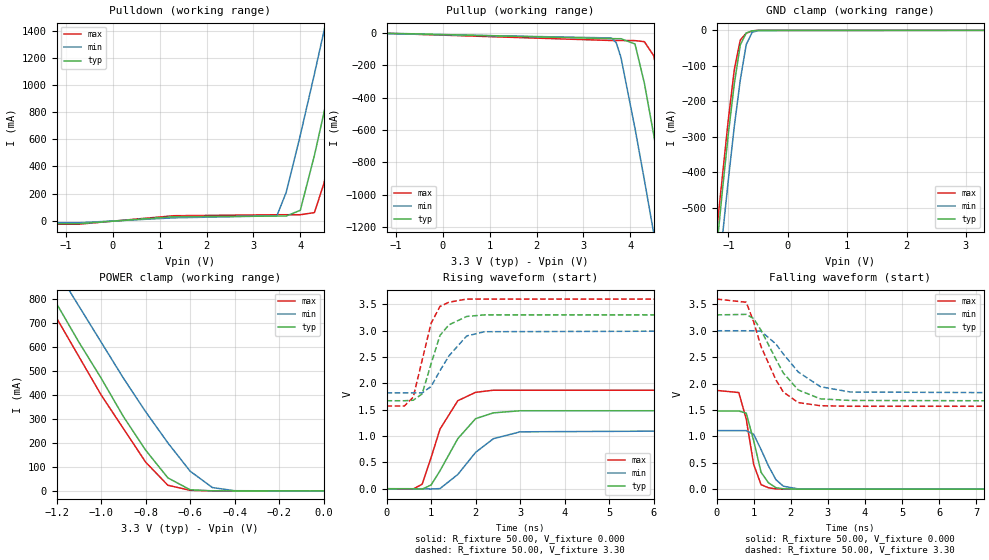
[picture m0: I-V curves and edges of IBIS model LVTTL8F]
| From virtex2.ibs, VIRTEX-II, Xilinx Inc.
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|   Model LVTTL8F
[Model]   LVTTL8F
Model_type   I/O
Polarity   Non-Inverting
Enable   Active-Low
Vinh = 2.0V
Vinl = 0.8V
Vmeas =   1.40V
Cref =  35.00pF
Rref =   1.00M
Vref =  0.000V
C_comp   7.00pF   6.00pF   8.00pF
[Temperature Range]   25.00   100.00   0.000
[Voltage Range]   3.30V   3.00V   3.60V
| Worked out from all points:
|   slope of the pulldown table from 0 to 0.495 V, typ, clamps not added: 32.6 ohm
|   slope of the pullup table from 0 to 0.495 V, typ, clamps not added: 42.6 ohm
|   GND clamp passes 1 mA (typ) near -0.57 V on its own axis
|   POWER clamp passes 1 mA (typ) near -0.52 V on its own axis
|   rising waveform, R_fixture 50.00, V_fixture 0.000: 20-80 % time 628ps typ, 738ps min, 546ps max; typ from 0 V to 1.48 V
|   rising waveform, R_fixture 50.00, V_fixture 3.30: 20-80 % time 395ps typ, 518ps min, 366ps max; typ from 1.67 V to 3.3 V
|   falling waveform, R_fixture 50.00, V_fixture 0.000: 20-80 % time 326ps typ, 463ps min, 316ps max; typ from 1.48 V to 0 V
|   falling waveform, R_fixture 50.00, V_fixture 3.30: 20-80 % time 792ps typ, 914ps min, 695ps max; typ from 3.3 V to 1.67 V
[Pulldown]
| voltage   I(typ)   I(min)   I(max)
-3.3V     -21.47mA   -14.42mA   -24.67mA
-700mV    -21.47mA   -14.42mA   -24.67mA
1.3V      29.85mA    21.41mA    36.81mA
3.5V      34.44mA    36.13mA    44.01mA
3.7V      34.53mA    210mA      44.1mA
4V        77.1mA     630mA      44.22mA
4.3V      480mA      1.08A      60mA
4.5V      790mA      1.39A      270mA
4.9V      1.44A      2.02A      900mA
5.1V      1.77A      2.33A      1.22A
5.3V      2.1A       2.65A      1.55A
6.6V      4.26A      4.71A      3.71A
[Pullup]
| voltage   I(typ)   I(min)   I(max)
-3.3V     15.18mA    8.8mA      18.53mA
3.6V      -33.89mA   -29.5mA    -45.21mA
3.7V      -34mA      -58.92mA   -45.36mA
3.8V      -34.18mA   -150mA     -45.5mA
4.1V      -66.66mA   -590mA     -45.96mA
4.3V      -310mA     -910mA     -52.6mA
4.5V      -630mA     -1.24A     -140mA
4.7V      -970mA     -1.58A     -420mA
4.9V      -1.31A     -1.92A     -750mA
5.1V      -1.66A     -2.26A     -1.1A
5.3V      -2.01A     -2.6A      -1.44A
6.6V      -4.31A     -4.84A     -3.74A
[GND_clamp]
| voltage   I(typ)   I(min)   I(max)
-3.3V     -4.3A      -4.31A     -4.26A
-1.2V     -620mA     -740mA     -570mA
-1.1V     -450mA     -580mA     -410mA
-1V       -290mA     -420mA     -250mA
-900mV    -150mA     -270mA     -110mA
-800mV    -41.03mA   -140mA     -27.28mA
-700mV    -7.6mA     -40.21mA   -8.18mA
-600mV    -1.42mA    -5.61mA    -1.62mA
-500mV    -130uA     -670uA     -130uA
3.3V      67.85pA    43.48uA    45.6pA
[POWER_clamp]
| voltage   I(typ)   I(min)   I(max)
-3.3V     4.25A      4.22A      4.2A
-1.3V     940mA      1.07A      880mA
-1.2V     780mA      920mA      720mA
-1.1V     620mA      770mA      560mA
-1V       470mA      620mA      400mA
-900mV    310mA      470mA      260mA
-800mV    170mA      330mA      120mA
-700mV    54.34mA    200mA      23.62mA
-600mV    4.76mA     82.21mA    2.52mA
-500mV    280uA      14.02mA    260uA
-400mV    16.9uA     860uA      14.85uA
0V        67.85pA    2.04nA     61.89pA
[Ramp]
| variable   typ   min   max
dV/dt_r   0.89/0.57n   0.67/0.72n   1.12/0.47n
dV/dt_f   0.98/0.74n   0.71/0.90n   1.22/0.62n
R_load = 50.00
[Rising Waveform]
R_fixture = 50.00
V_fixture = 0.000
| time   V(typ)   V(min)   V(max)
0s        0V         0V         0V
600ps     -810uV     13.1uV     -4.7mV
800ps     -8.37mV    -240uV     85.17mV
1ns       70.16mV    -5.78mV    590mV
1.2ns     340mV      2.48mV     1.13V
1.6ns     950mV      270mV      1.67V
2ns       1.33V      690mV      1.83V
2.4ns     1.44V      950mV      1.87V
3ns       1.48V      1.08V      1.87V
10ns      1.48V      1.11V      1.87V
[Rising Waveform]
R_fixture = 50.00
V_fixture = 3.30
V_fixture_min = 3.00
V_fixture_max = 3.60
| time   V(typ)   V(min)   V(max)
0s        1.67V      1.82V      1.57V
400ps     1.67V      1.82V      1.57V
600ps     1.68V      1.82V      1.74V
800ps     1.8V       1.82V      2.44V
1ns       2.37V      1.94V      3.14V
1.2ns     2.91V      2.24V      3.46V
1.4ns     3.11V      2.52V      3.54V
1.8ns     3.27V      2.9V       3.6V
2.2ns     3.3V       2.98V      3.6V
10ns      3.3V       3V         3.6V
[Falling Waveform]
R_fixture = 50.00
V_fixture = 0.000
| time   V(typ)   V(min)   V(max)
0s        1.48V      1.11V      1.87V
600ps     1.48V      1.11V      1.83V
800ps     1.44V      1.11V      1.33V
1ns       920mV      1.04V      470mV
1.2ns     320mV      750mV      85.23mV
1.4ns     120mV      440mV      26.62mV
1.6ns     28.37mV    180mV      4.57mV
1.8ns     6.29mV     56.22mV    1.09mV
2.2ns     730uV      5.4mV      220uV
10ns      2.47uV     3.89uV     1.44uV
[Falling Waveform]
R_fixture = 50.00
V_fixture = 3.30
V_fixture_min = 3.00
V_fixture_max = 3.60
| time   V(typ)   V(min)   V(max)
0s        3.3V       3V         3.6V
800ps     3.31V      3V         3.54V
1ns       3.23V      3V         3.17V
1.2ns     3.01V      2.99V      2.7V
1.6ns     2.46V      2.75V      2.07V
1.8ns     2.2V       2.56V      1.84V
2.2ns     1.88V      2.22V      1.64V
2.8ns     1.71V      1.94V      1.58V
3.6ns     1.68V      1.84V      1.57V
10ns      1.67V      1.82V      1.57V
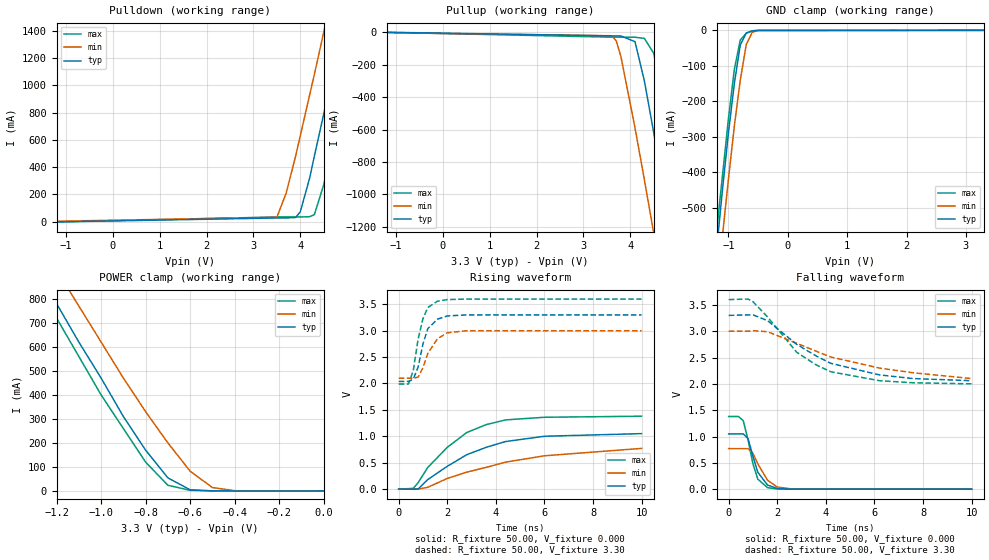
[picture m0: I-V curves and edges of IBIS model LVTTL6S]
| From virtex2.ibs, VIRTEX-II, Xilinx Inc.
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|   Model LVTTL6S
[Model]   LVTTL6S
Model_type   I/O
Polarity   Non-Inverting
Enable   Active-Low
Vinh = 2.0V
Vinl = 0.8V
Vmeas =   1.40V
Cref =  35.00pF
Rref =   1.00M
Vref =  0.000V
C_comp   7.00pF   6.00pF   8.00pF
[Temperature Range]   25.00   100.00   0.000
[Voltage Range]   3.30V   3.00V   3.60V
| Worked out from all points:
|   slope of the pulldown table from 0 to 0.495 V, typ, clamps not added: 43.1 ohm
|   slope of the pullup table from 0 to 0.495 V, typ, clamps not added: 63.8 ohm
|   GND clamp passes 1 mA (typ) near -0.57 V on its own axis
|   POWER clamp passes 1 mA (typ) near -0.52 V on its own axis
|   rising waveform, R_fixture 50.00, V_fixture 0.000: 20-80 % time 2.63ns typ, 4ns min, 1.94ns max; typ from 0 V to 1.05 V
|   rising waveform, R_fixture 50.00, V_fixture 3.30: 20-80 % time 432ps typ, 576ps min, 422ps max; typ from 2.04 V to 3.3 V
|   falling waveform, R_fixture 50.00, V_fixture 0.000: 20-80 % time 487ps typ, 573ps min, 435ps max; typ from 1.05 V to 0 V
|   falling waveform, R_fixture 50.00, V_fixture 3.30: 20-80 % time 2.79ns typ, 3.8ns min, 2.22ns max; typ from 3.3 V to 2.06 V
[Pulldown]
| voltage   I(typ)   I(min)   I(max)
-3.3V     -16.22mA   -10.87mA   -18.67mA
3.5V      25.91mA    30.57mA    33.14mA
3.7V      25.98mA    210mA      33.2mA
3.9V      29.56mA    480mA      33.26mA
4V        71.32mA    630mA      33.3mA
4.2V      320mA      930mA      35.28mA
4.3V      480mA      1.08A      50.75mA
4.5V      790mA      1.39A      270mA
4.9V      1.44A      2.01A      890mA
5.1V      1.77A      2.33A      1.22A
5.3V      2.1A       2.64A      1.54A
6.6V      4.26A      4.71A      3.71A
[Pullup]
| voltage   I(typ)   I(min)   I(max)
-3.3V     10.13mA    5.86mA     12.39mA
3.6V      -22.6mA    -21.51mA   -30.15mA
3.7V      -22.67mA   -52.6mA    -30.25mA
3.8V      -22.83mA   -150mA     -30.34mA
4.1V      -57.92mA   -590mA     -30.68mA
4.3V      -300mA     -910mA     -37.77mA
4.5V      -620mA     -1.24A     -130mA
4.7V      -960mA     -1.58A     -420mA
4.9V      -1.31A     -1.92A     -750mA
5.1V      -1.66A     -2.26A     -1.09A
5.3V      -2.01A     -2.6A      -1.44A
6.6V      -4.31A     -4.84A     -3.73A
[GND_clamp]
| voltage   I(typ)   I(min)   I(max)
-3.3V     -4.3A      -4.31A     -4.26A
-1.2V     -620mA     -740mA     -570mA
-1.1V     -450mA     -580mA     -410mA
-1V       -290mA     -420mA     -250mA
-900mV    -150mA     -270mA     -110mA
-800mV    -41.03mA   -140mA     -27.28mA
-700mV    -7.6mA     -40.21mA   -8.18mA
-600mV    -1.42mA    -5.61mA    -1.62mA
-500mV    -130uA     -670uA     -130uA
3.3V      67.85pA    43.48uA    45.6pA
[POWER_clamp]
| voltage   I(typ)   I(min)   I(max)
-3.3V     4.25A      4.22A      4.2A
-1.3V     940mA      1.07A      880mA
-1.2V     780mA      920mA      720mA
-1.1V     620mA      770mA      560mA
-1V       470mA      620mA      400mA
-900mV    310mA      470mA      260mA
-800mV    170mA      330mA      120mA
-700mV    54.34mA    200mA      23.62mA
-600mV    4.76mA     82.21mA    2.52mA
-500mV    280uA      14.02mA    260uA
-400mV    16.9uA     860uA      14.85uA
0V        67.85pA    2.04nA     61.89pA
[Ramp]
| variable   typ   min   max
dV/dt_r   0.63/2.59n   0.45/3.84n   0.83/1.93n
dV/dt_f   0.74/2.77n   0.51/3.42n   0.96/2.21n
R_load = 50.00
[Rising Waveform]
R_fixture = 50.00
V_fixture = 0.000
| time   V(typ)   V(min)   V(max)
0s        0V         0V         0V
600ps     -2.54mV    -130uV     11.29mV
800ps     1.12mV     -2.6mV     120mV
1.2ns     180mV      33.44mV    410mV
2ns       430mV      200mV      790mV
2.8ns     650mV      320mV      1.07V
3.6ns     790mV      410mV      1.22V
4.4ns     900mV      510mV      1.31V
6ns       1V         630mV      1.36V
10ns      1.05V      770mV      1.38V
[Rising Waveform]
R_fixture = 50.00
V_fixture = 3.30
V_fixture_min = 3.00
V_fixture_max = 3.60
| time   V(typ)   V(min)   V(max)
0s        2.04V      2.1V       1.99V
400ps     2.04V      2.1V       1.99V
600ps     2.08V      2.1V       2.24V
800ps     2.31V      2.12V      2.84V
1ns       2.75V      2.3V       3.23V
1.2ns     3.04V      2.57V      3.44V
1.6ns     3.22V      2.85V      3.56V
2ns       3.28V      2.96V      3.59V
2.8ns     3.3V       3V         3.6V
10ns      3.3V       3V         3.6V
[Falling Waveform]
R_fixture = 50.00
V_fixture = 0.000
| time   V(typ)   V(min)   V(max)
0s        1.05V      770mV      1.38V
400ps     1.05V      770mV      1.38V
600ps     1.05V      770mV      1.3V
800ps     960mV      770mV      930mV
1ns       620mV      680mV      480mV
1.2ns     320mV      480mV      190mV
1.6ns     78.29mV    170mV      28.18mV
2ns       11.87mV    40.34mV    2.99mV
2.6ns     1.33mV     4.3mV      900uV
10ns      23.21uV    61.06uV    9.13uV
[Falling Waveform]
R_fixture = 50.00
V_fixture = 3.30
V_fixture_min = 3.00
V_fixture_max = 3.60
| time   V(typ)   V(min)   V(max)
0s        3.3V       3V         3.6V
800ps     3.31V      3V         3.61V
1ns       3.31V      3.01V      3.56V
1.6ns     3.2V       2.99V      3.27V
2.8ns     2.75V      2.77V      2.6V
3.6ns     2.53V      2.62V      2.36V
4.2ns     2.39V      2.51V      2.23V
6.2ns     2.17V      2.3V       2.06V
7.6ns     2.1V       2.21V      2.02V
10ns      2.06V      2.1V       2V
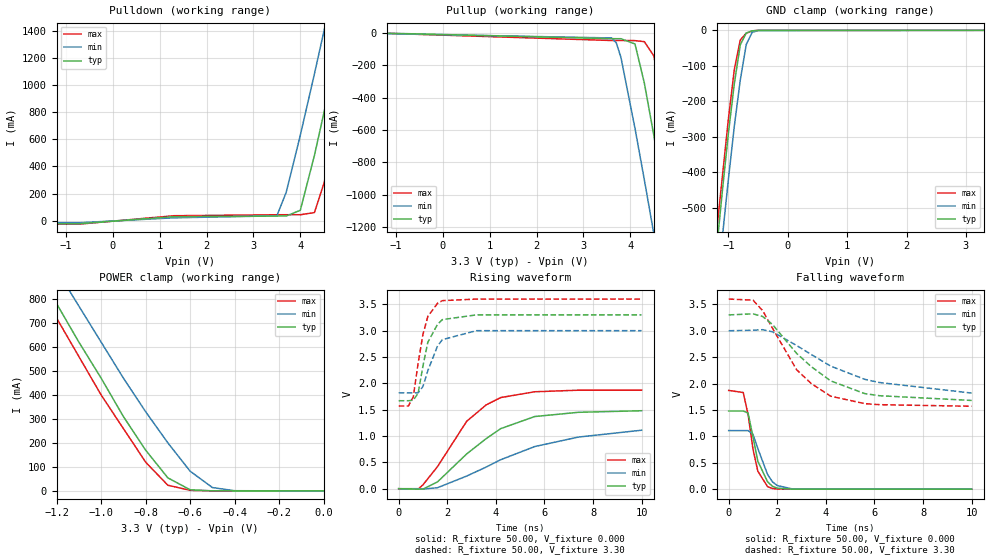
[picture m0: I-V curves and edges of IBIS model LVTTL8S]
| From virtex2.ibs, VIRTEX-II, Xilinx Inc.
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|   Model LVTTL8S
[Model]   LVTTL8S
Model_type   I/O
Polarity   Non-Inverting
Enable   Active-Low
Vinh = 2.0V
Vinl = 0.8V
Vmeas =   1.40V
Cref =  35.00pF
Rref =   1.00M
Vref =  0.000V
C_comp   7.00pF   6.00pF   8.00pF
[Temperature Range]   25.00   100.00   0.000
[Voltage Range]   3.30V   3.00V   3.60V
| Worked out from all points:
|   slope of the pulldown table from 0 to 0.495 V, typ, clamps not added: 32.6 ohm
|   slope of the pullup table from 0 to 0.495 V, typ, clamps not added: 42.6 ohm
|   GND clamp passes 1 mA (typ) near -0.57 V on its own axis
|   POWER clamp passes 1 mA (typ) near -0.52 V on its own axis
|   rising waveform, R_fixture 50.00, V_fixture 0.000: 20-80 % time 2.33ns typ, 3.65ns min, 1.81ns max; typ from 0 V to 1.48 V
|   rising waveform, R_fixture 50.00, V_fixture 3.30: 20-80 % time 546ps typ, 613ps min, 482ps max; typ from 1.67 V to 3.3 V
|   falling waveform, R_fixture 50.00, V_fixture 0.000: 20-80 % time 513ps typ, 570ps min, 425ps max; typ from 1.48 V to 0 V
|   falling waveform, R_fixture 50.00, V_fixture 3.30: 20-80 % time 2.27ns typ, 3.17ns min, 1.83ns max; typ from 3.3 V to 1.68 V
[Pulldown]
| voltage   I(typ)   I(min)   I(max)
-3.3V     -21.47mA   -14.42mA   -24.67mA
-700mV    -21.47mA   -14.42mA   -24.67mA
1.3V      29.85mA    21.41mA    36.81mA
3.5V      34.44mA    36.13mA    44.01mA
3.7V      34.53mA    210mA      44.1mA
4V        77.1mA     630mA      44.22mA
4.3V      480mA      1.08A      60mA
4.5V      790mA      1.39A      270mA
4.9V      1.44A      2.02A      900mA
5.1V      1.77A      2.33A      1.22A
5.3V      2.1A       2.65A      1.55A
6.6V      4.26A      4.71A      3.71A
[Pullup]
| voltage   I(typ)   I(min)   I(max)
-3.3V     15.18mA    8.8mA      18.53mA
3.6V      -33.89mA   -29.5mA    -45.21mA
3.7V      -34mA      -58.92mA   -45.36mA
3.8V      -34.18mA   -150mA     -45.5mA
4.1V      -66.66mA   -590mA     -45.96mA
4.3V      -310mA     -910mA     -52.6mA
4.5V      -630mA     -1.24A     -140mA
4.7V      -970mA     -1.58A     -420mA
4.9V      -1.31A     -1.92A     -750mA
5.1V      -1.66A     -2.26A     -1.1A
5.3V      -2.01A     -2.6A      -1.44A
6.6V      -4.31A     -4.84A     -3.74A
[GND_clamp]
| voltage   I(typ)   I(min)   I(max)
-3.3V     -4.3A      -4.31A     -4.26A
-1.2V     -620mA     -740mA     -570mA
-1.1V     -450mA     -580mA     -410mA
-1V       -290mA     -420mA     -250mA
-900mV    -150mA     -270mA     -110mA
-800mV    -41.03mA   -140mA     -27.28mA
-700mV    -7.6mA     -40.21mA   -8.18mA
-600mV    -1.42mA    -5.61mA    -1.62mA
-500mV    -130uA     -670uA     -130uA
3.3V      67.85pA    43.48uA    45.6pA
[POWER_clamp]
| voltage   I(typ)   I(min)   I(max)
-3.3V     4.25A      4.22A      4.2A
-1.3V     940mA      1.07A      880mA
-1.2V     780mA      920mA      720mA
-1.1V     620mA      770mA      560mA
-1V       470mA      620mA      400mA
-900mV    310mA      470mA      260mA
-800mV    170mA      330mA      120mA
-700mV    54.34mA    200mA      23.62mA
-600mV    4.76mA     82.21mA    2.52mA
-500mV    280uA      14.02mA    260uA
-400mV    16.9uA     860uA      14.85uA
0V        67.85pA    2.04nA     61.89pA
[Ramp]
| variable   typ   min   max
dV/dt_r   0.89/2.40n   0.64/3.39n   1.12/1.80n
dV/dt_f   0.97/2.37n   0.69/3.01n   1.21/1.81n
R_load = 50.00
[Rising Waveform]
R_fixture = 50.00
V_fixture = 0.000
| time   V(typ)   V(min)   V(max)
0s        0V         0V         0V
800ps     -7.93mV    -210uV     -9.09mV
1ns       -7.54mV    -6.07mV    72.8mV
1.6ns     130mV      18.15mV    420mV
2.8ns     660mV      240mV      1.28V
3.6ns     950mV      410mV      1.59V
4.2ns     1.14V      550mV      1.73V
5.6ns     1.37V      800mV      1.84V
7.4ns     1.45V      980mV      1.87V
10ns      1.48V      1.11V      1.87V
[Rising Waveform]
R_fixture = 50.00
V_fixture = 3.30
V_fixture_min = 3.00
V_fixture_max = 3.60
| time   V(typ)   V(min)   V(max)
0s        1.67V      1.82V      1.57V
400ps     1.67V      1.82V      1.57V
600ps     1.68V      1.82V      1.74V
800ps     1.81V      1.82V      2.38V
1ns       2.33V      1.94V      2.93V
1.2ns     2.78V      2.24V      3.27V
1.6ns     3.12V      2.71V      3.52V
1.8ns     3.21V      2.83V      3.57V
3.2ns     3.3V       3V         3.6V
10ns      3.3V       3V         3.6V
[Falling Waveform]
R_fixture = 50.00
V_fixture = 0.000
| time   V(typ)   V(min)   V(max)
0s        1.48V      1.11V      1.87V
600ps     1.48V      1.11V      1.83V
800ps     1.44V      1.11V      1.41V
1ns       990mV      1.04V      760mV
1.2ns     530mV      770mV      340mV
1.6ns     140mV      280mV      48.56mV
1.8ns     54.94mV    140mV      12.66mV
2ns       18.83mV    68.69mV    3.61mV
2.6ns     1.63mV     6.35mV     1.14mV
10ns      13.66uV    48.18uV    5.93uV
[Falling Waveform]
R_fixture = 50.00
V_fixture = 3.30
V_fixture_min = 3.00
V_fixture_max = 3.60
| time   V(typ)   V(min)   V(max)
0s        3.3V       3V         3.6V
1ns       3.32V      3.01V      3.58V
1.4ns     3.27V      3.02V      3.38V
1.8ns     3.12V      2.98V      3.05V
2.8ns     2.57V      2.72V      2.26V
3.4ns     2.32V      2.55V      2V
4.2ns     2.05V      2.33V      1.76V
5.6ns     1.81V      2.08V      1.62V
6.2ns     1.77V      2.02V      1.6V
10ns      1.68V      1.82V      1.57V
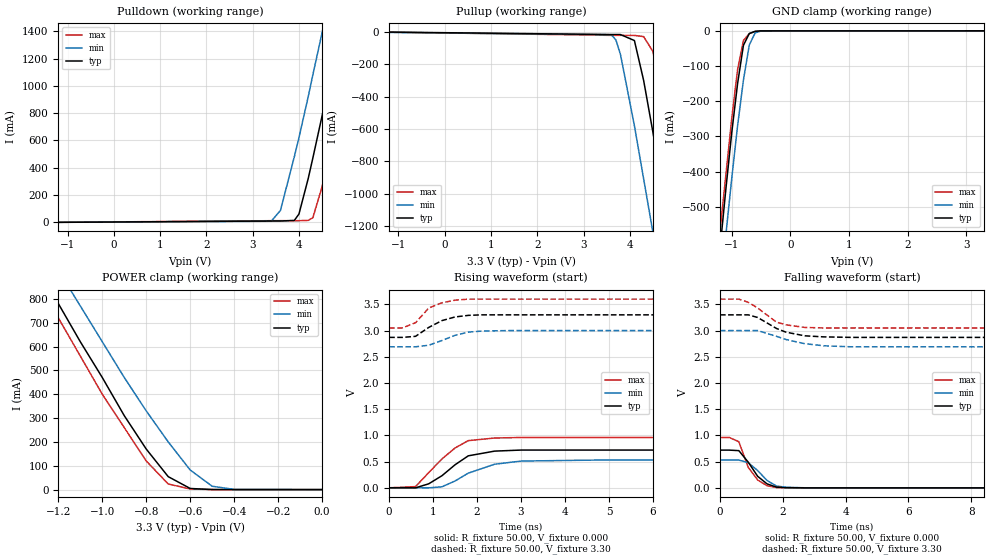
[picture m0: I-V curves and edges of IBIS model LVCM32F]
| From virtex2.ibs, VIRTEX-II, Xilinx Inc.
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|   Model LVCM32F
[Model]   LVCM32F
Model_type   I/O
Polarity   Non-Inverting
Enable   Active-Low
Vinh = 2.0V
Vinl = 0.8V
Vmeas =   1.65V
Cref =  35.00pF
Rref =   1.00M
Vref =  0.000V
C_comp   7.00pF   6.00pF   8.00pF
[Temperature Range]   25.00   100.00   0.000
[Voltage Range]   3.30V   3.00V   3.60V
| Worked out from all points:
|   slope of the pulldown table from 0 to 0.495 V, typ, clamps not added: 127 ohm
|   slope of the pullup table from 0 to 0.495 V, typ, clamps not added: 95.5 ohm
|   GND clamp passes 1 mA (typ) near -0.57 V on its own axis
|   POWER clamp passes 1 mA (typ) near -0.52 V on its own axis
|   rising waveform, R_fixture 50.00, V_fixture 0.000: 20-80 % time 708ps typ, 853ps min, 727ps max; typ from 0 V to 0.72 V
|   rising waveform, R_fixture 50.00, V_fixture 3.30: 20-80 % time 586ps typ, 633ps min, 469ps max; typ from 2.87 V to 3.3 V
|   falling waveform, R_fixture 50.00, V_fixture 0.000: 20-80 % time 575ps typ, 585ps min, 479ps max; typ from 0.72 V to 0 V
|   falling waveform, R_fixture 50.00, V_fixture 3.30: 20-80 % time 897ps typ, 1.09ns min, 764ps max; typ from 3.3 V to 2.87 V
[Pulldown]
| voltage   I(typ)   I(min)   I(max)
-3.3V     -5.48mA    -3.66mA    -6.34mA
3.4V      8.68mA     7.12mA     11.12mA
3.6V      8.7mA      86.09mA    11.15mA
3.9V      13.03mA    480mA      11.18mA
4V        59.94mA    620mA      11.2mA
4.2V      320mA      920mA      13.51mA
4.3V      470mA      1.08A      32.54mA
4.5V      780mA      1.39A      260mA
4.9V      1.43A      2.01A      880mA
5.1V      1.76A      2.32A      1.21A
5.3V      2.09A      2.64A      1.54A
6.6V      4.26A      4.7A       3.7A
[Pullup]
| voltage   I(typ)   I(min)   I(max)
-3.3V     6.76mA     3.9mA      8.28mA
3.6V      -15.07mA   -16.2mA    -20.1mA
3.7V      -15.12mA   -48.43mA   -20.17mA
3.8V      -15.26mA   -140mA     -20.23mA
4.1V      -52.21mA   -580mA     -20.5mA
4.3V      -300mA     -910mA     -27.9mA
4.5V      -620mA     -1.24A     -120mA
4.7V      -960mA     -1.58A     -410mA
4.9V      -1.3A      -1.91A     -750mA
5.1V      -1.65A     -2.25A     -1.09A
5.3V      -2A        -2.6A      -1.43A
6.6V      -4.31A     -4.84A     -3.73A
[GND_clamp]
| voltage   I(typ)   I(min)   I(max)
-3.3V     -4.3A      -4.31A     -4.26A
-1.2V     -620mA     -740mA     -570mA
-1.1V     -450mA     -580mA     -410mA
-1V       -290mA     -420mA     -250mA
-900mV    -150mA     -270mA     -110mA
-800mV    -41.03mA   -140mA     -27.28mA
-700mV    -7.6mA     -40.21mA   -8.18mA
-600mV    -1.42mA    -5.61mA    -1.62mA
-500mV    -130uA     -670uA     -130uA
3.3V      67.85pA    43.48uA    45.6pA
[POWER_clamp]
| voltage   I(typ)   I(min)   I(max)
-3.3V     4.25A      4.22A      4.2A
-1.3V     940mA      1.07A      880mA
-1.2V     780mA      920mA      720mA
-1.1V     620mA      770mA      560mA
-1V       470mA      620mA      400mA
-900mV    310mA      470mA      260mA
-800mV    170mA      330mA      120mA
-700mV    54.34mA    200mA      23.62mA
-600mV    4.76mA     82.21mA    2.52mA
-500mV    280uA      14.02mA    260uA
-400mV    16.9uA     860uA      14.85uA
0V        67.85pA    2.04nA     61.89pA
[Ramp]
| variable   typ   min   max
dV/dt_r   0.43/0.71n   0.32/0.88n   0.58/0.61n
dV/dt_f   0.26/0.94n   0.19/1.15n   0.33/0.82n
R_load = 50.00
[Rising Waveform]
R_fixture = 50.00
V_fixture = 0.000
| time   V(typ)   V(min)   V(max)
0s        0V         530nV      0V
600ps     -960uV     -37.85uV   22.46mV
900ps     76.21mV    -1.2mV     290mV
1.2ns     230mV      19.07mV    550mV
1.5ns     440mV      130mV      760mV
1.8ns     610mV      280mV      900mV
2.4ns     700mV      450mV      950mV
3ns       720mV      510mV      960mV
4.8ns     720mV      530mV      960mV
15ns      720mV      530mV      960mV
[Rising Waveform]
R_fixture = 50.00
V_fixture = 3.30
V_fixture_min = 3.00
V_fixture_max = 3.60
| time   V(typ)   V(min)   V(max)
0s        2.87V      2.69V      3.05V
300ps     2.87V      2.69V      3.05V
600ps     2.89V      2.69V      3.15V
900ps     3.06V      2.72V      3.43V
1.2ns     3.19V      2.81V      3.53V
1.5ns     3.26V      2.91V      3.58V
1.8ns     3.29V      2.97V      3.6V
2.1ns     3.3V       2.99V      3.6V
2.7ns     3.3V       3V         3.6V
15ns      3.3V       3V         3.6V
[Falling Waveform]
R_fixture = 50.00
V_fixture = 0.000
| time   V(typ)   V(min)   V(max)
0s        720mV      530mV      960mV
300ps     720mV      530mV      960mV
600ps     710mV      530mV      880mV
900ps     490mV      480mV      390mV
1.2ns     220mV      330mV      150mV
1.5ns     75.36mV    140mV      40.5mV
1.8ns     13.79mV    34.56mV    5.89mV
2.1ns     3.44mV     11.5mV     1.23mV
2.7ns     300uV      1.21mV     100uV
15ns      1.7uV      3.61uV     1.99uV
[Falling Waveform]
R_fixture = 50.00
V_fixture = 3.30
V_fixture_min = 3.00
V_fixture_max = 3.60
| time   V(typ)   V(min)   V(max)
0s        3.3V       3V         3.6V
600ps     3.3V       3V         3.6V
900ps     3.3V       3V         3.54V
1.2ns     3.25V      3V         3.43V
1.8ns     3.04V      2.89V      3.16V
2.1ns     2.97V      2.83V      3.11V
2.7ns     2.9V       2.75V      3.06V
3.3ns     2.88V      2.71V      3.05V
4.2ns     2.87V      2.69V      3.05V
15ns      2.87V      2.69V      3.05V
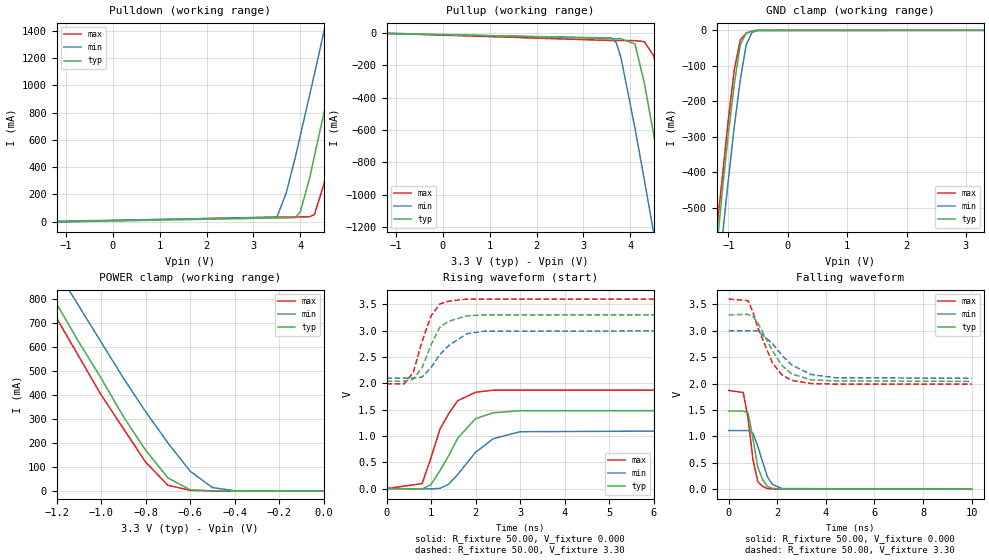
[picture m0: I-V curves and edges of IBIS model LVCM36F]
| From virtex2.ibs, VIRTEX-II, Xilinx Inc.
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|   Model LVCM36F
[Model]   LVCM36F
Model_type   I/O
Polarity   Non-Inverting
Enable   Active-Low
Vinh = 2.0V
Vinl = 0.8V
Vmeas =   1.65V
Cref =  35.00pF
Rref =   1.00M
Vref =  0.000V
C_comp   7.00pF   6.00pF   8.00pF
[Temperature Range]   25.00   100.00   0.000
[Voltage Range]   3.30V   3.00V   3.60V
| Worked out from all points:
|   slope of the pulldown table from 0 to 0.495 V, typ, clamps not added: 43.1 ohm
|   slope of the pullup table from 0 to 0.495 V, typ, clamps not added: 42.6 ohm
|   GND clamp passes 1 mA (typ) near -0.57 V on its own axis
|   POWER clamp passes 1 mA (typ) near -0.52 V on its own axis
|   rising waveform, R_fixture 50.00, V_fixture 0.000: 20-80 % time 628ps typ, 740ps min, 542ps max; typ from 0 V to 1.48 V
|   rising waveform, R_fixture 50.00, V_fixture 3.30: 20-80 % time 394ps typ, 556ps min, 365ps max; typ from 2.04 V to 3.3 V
|   falling waveform, R_fixture 50.00, V_fixture 0.000: 20-80 % time 392ps typ, 474ps min, 352ps max; typ from 1.48 V to 0 V
|   falling waveform, R_fixture 50.00, V_fixture 3.30: 20-80 % time 971ps typ, 1.11ns min, 862ps max; typ from 3.3 V to 2.04 V
[Pulldown]
| voltage   I(typ)   I(min)   I(max)
-3.3V     -16.22mA   -10.87mA   -18.67mA
3.5V      25.91mA    30.57mA    33.14mA
3.7V      25.98mA    210mA      33.2mA
3.9V      29.56mA    480mA      33.26mA
4V        71.32mA    630mA      33.3mA
4.2V      320mA      930mA      35.28mA
4.3V      480mA      1.08A      50.75mA
4.5V      790mA      1.39A      270mA
4.9V      1.44A      2.01A      890mA
5.1V      1.77A      2.33A      1.22A
5.3V      2.1A       2.64A      1.54A
6.6V      4.26A      4.71A      3.71A
[Pullup]
| voltage   I(typ)   I(min)   I(max)
-3.3V     15.18mA    8.8mA      18.53mA
3.6V      -33.89mA   -29.5mA    -45.21mA
3.7V      -34mA      -58.92mA   -45.36mA
3.8V      -34.18mA   -150mA     -45.5mA
4.1V      -66.66mA   -590mA     -45.96mA
4.3V      -310mA     -910mA     -52.6mA
4.5V      -630mA     -1.24A     -140mA
4.7V      -970mA     -1.58A     -420mA
4.9V      -1.31A     -1.92A     -750mA
5.1V      -1.66A     -2.26A     -1.1A
5.3V      -2.01A     -2.6A      -1.44A
6.6V      -4.31A     -4.84A     -3.74A
[GND_clamp]
| voltage   I(typ)   I(min)   I(max)
-3.3V     -4.3A      -4.31A     -4.26A
-1.2V     -620mA     -740mA     -570mA
-1.1V     -450mA     -580mA     -410mA
-1V       -290mA     -420mA     -250mA
-900mV    -150mA     -270mA     -110mA
-800mV    -41.03mA   -140mA     -27.28mA
-700mV    -7.6mA     -40.21mA   -8.18mA
-600mV    -1.42mA    -5.61mA    -1.62mA
-500mV    -130uA     -670uA     -130uA
3.3V      67.85pA    43.48uA    45.6pA
[POWER_clamp]
| voltage   I(typ)   I(min)   I(max)
-3.3V     4.25A      4.22A      4.2A
-1.3V     940mA      1.07A      880mA
-1.2V     780mA      920mA      720mA
-1.1V     620mA      770mA      560mA
-1V       470mA      620mA      400mA
-900mV    310mA      470mA      260mA
-800mV    170mA      330mA      120mA
-700mV    54.34mA    200mA      23.62mA
-600mV    4.76mA     82.21mA    2.52mA
-500mV    280uA      14.02mA    260uA
-400mV    16.9uA     860uA      14.85uA
0V        67.85pA    2.04nA     61.89pA
[Ramp]
| variable   typ   min   max
dV/dt_r   0.89/0.57n   0.67/0.72n   1.12/0.47n
dV/dt_f   0.75/0.93n   0.54/1.14n   0.96/0.80n
R_load = 50.00
[Rising Waveform]
R_fixture = 50.00
V_fixture = 0.000
| time   V(typ)   V(min)   V(max)
0s        0V         0V         0V
800ps     -10.44mV   -2.1mV     94.79mV
1ns       78.25mV    -6.95mV    590mV
1.2ns     340mV      5.59mV     1.13V
1.4ns     630mV      87.41mV    1.43V
1.6ns     960mV      270mV      1.67V
2ns       1.33V      690mV      1.83V
2.4ns     1.44V      950mV      1.87V
3ns       1.48V      1.08V      1.87V
10ns      1.48V      1.11V      1.87V
[Rising Waveform]
R_fixture = 50.00
V_fixture = 3.30
V_fixture_min = 3.00
V_fixture_max = 3.60
| time   V(typ)   V(min)   V(max)
0s        2.04V      2.1V       1.99V
400ps     2.04V      2.1V       1.99V
600ps     2.08V      2.1V       2.21V
800ps     2.3V       2.12V      2.8V
1ns       2.73V      2.3V       3.28V
1.2ns     3.07V      2.55V      3.51V
1.4ns     3.18V      2.72V      3.56V
1.8ns     3.28V      2.94V      3.6V
2.2ns     3.3V       2.99V      3.6V
10ns      3.3V       3V         3.6V
[Falling Waveform]
R_fixture = 50.00
V_fixture = 0.000
| time   V(typ)   V(min)   V(max)
0s        1.48V      1.11V      1.87V
600ps     1.48V      1.11V      1.83V
800ps     1.44V      1.11V      1.34V
1ns       960mV      1.06V      560mV
1.2ns     410mV      810mV      140mV
1.4ns     180mV      510mV      50.01mV
1.6ns     50.79mV    230mV      12.81mV
1.8ns     15.24mV    89.15mV    2.85mV
2.2ns     1.52mV     11.65mV    490uV
10ns      3.19uV     4.31uV     2.41uV
[Falling Waveform]
R_fixture = 50.00
V_fixture = 3.30
V_fixture_min = 3.00
V_fixture_max = 3.60
| time   V(typ)   V(min)   V(max)
0s        3.3V       3V         3.6V
800ps     3.31V      3V         3.57V
1ns       3.27V      3V         3.35V
1.2ns     3.15V      3V         3.06V
1.8ns     2.62V      2.76V      2.39V
2.2ns     2.34V      2.53V      2.16V
2.6ns     2.18V      2.35V      2.06V
3.4ns     2.07V      2.17V      2V
4.4ns     2.05V      2.11V      1.99V
10ns      2.04V      2.1V       1.99V
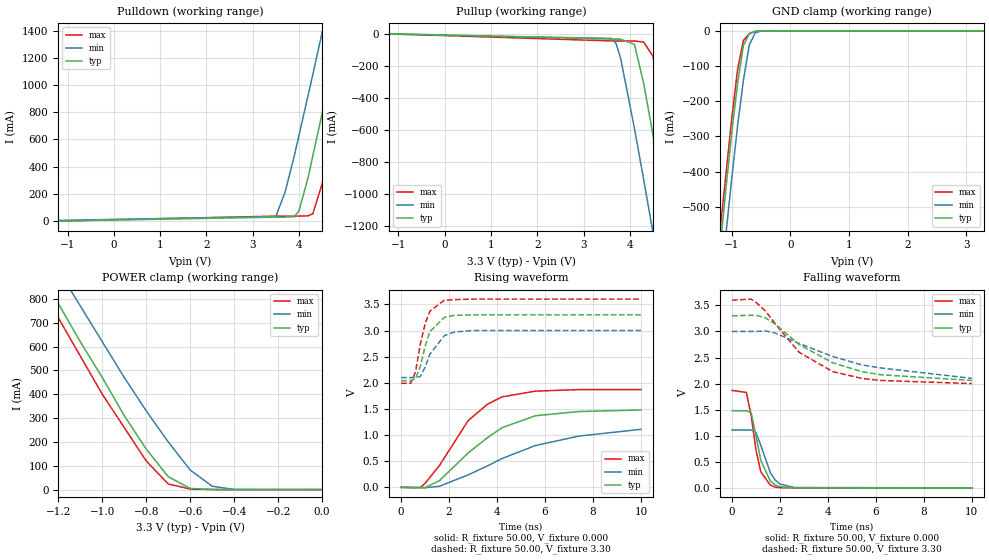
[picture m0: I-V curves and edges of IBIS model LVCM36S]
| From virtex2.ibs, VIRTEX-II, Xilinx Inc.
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|   Model LVCM36S
[Model]   LVCM36S
Model_type   I/O
Polarity   Non-Inverting
Enable   Active-Low
Vinh = 2.0V
Vinl = 0.8V
Vmeas =   1.65V
Cref =  35.00pF
Rref =   1.00M
Vref =  0.000V
C_comp   7.00pF   6.00pF   8.00pF
[Temperature Range]   25.00   100.00   0.000
[Voltage Range]   3.30V   3.00V   3.60V
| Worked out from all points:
|   slope of the pulldown table from 0 to 0.495 V, typ, clamps not added: 43.1 ohm
|   slope of the pullup table from 0 to 0.495 V, typ, clamps not added: 42.6 ohm
|   GND clamp passes 1 mA (typ) near -0.57 V on its own axis
|   POWER clamp passes 1 mA (typ) near -0.52 V on its own axis
|   rising waveform, R_fixture 50.00, V_fixture 0.000: 20-80 % time 2.33ns typ, 3.65ns min, 1.8ns max; typ from 0 V to 1.48 V
|   rising waveform, R_fixture 50.00, V_fixture 3.30: 20-80 % time 539ps typ, 622ps min, 485ps max; typ from 2.04 V to 3.3 V
|   falling waveform, R_fixture 50.00, V_fixture 0.000: 20-80 % time 488ps typ, 554ps min, 418ps max; typ from 1.48 V to 0 V
|   falling waveform, R_fixture 50.00, V_fixture 3.30: 20-80 % time 2.79ns typ, 3.8ns min, 2.22ns max; typ from 3.3 V to 2.06 V
[Pulldown]
| voltage   I(typ)   I(min)   I(max)
-3.3V     -16.22mA   -10.87mA   -18.67mA
3.5V      25.91mA    30.57mA    33.14mA
3.7V      25.98mA    210mA      33.2mA
3.9V      29.56mA    480mA      33.26mA
4V        71.32mA    630mA      33.3mA
4.2V      320mA      930mA      35.28mA
4.3V      480mA      1.08A      50.75mA
4.5V      790mA      1.39A      270mA
4.9V      1.44A      2.01A      890mA
5.1V      1.77A      2.33A      1.22A
5.3V      2.1A       2.64A      1.54A
6.6V      4.26A      4.71A      3.71A
[Pullup]
| voltage   I(typ)   I(min)   I(max)
-3.3V     15.18mA    8.8mA      18.53mA
3.6V      -33.89mA   -29.5mA    -45.21mA
3.7V      -34mA      -58.92mA   -45.36mA
3.8V      -34.18mA   -150mA     -45.5mA
4.1V      -66.66mA   -590mA     -45.96mA
4.3V      -310mA     -910mA     -52.6mA
4.5V      -630mA     -1.24A     -140mA
4.7V      -970mA     -1.58A     -420mA
4.9V      -1.31A     -1.92A     -750mA
5.1V      -1.66A     -2.26A     -1.1A
5.3V      -2.01A     -2.6A      -1.44A
6.6V      -4.31A     -4.84A     -3.74A
[GND_clamp]
| voltage   I(typ)   I(min)   I(max)
-3.3V     -4.3A      -4.31A     -4.26A
-1.2V     -620mA     -740mA     -570mA
-1.1V     -450mA     -580mA     -410mA
-1V       -290mA     -420mA     -250mA
-900mV    -150mA     -270mA     -110mA
-800mV    -41.03mA   -140mA     -27.28mA
-700mV    -7.6mA     -40.21mA   -8.18mA
-600mV    -1.42mA    -5.61mA    -1.62mA
-500mV    -130uA     -670uA     -130uA
3.3V      67.85pA    43.48uA    45.6pA
[POWER_clamp]
| voltage   I(typ)   I(min)   I(max)
-3.3V     4.25A      4.22A      4.2A
-1.3V     940mA      1.07A      880mA
-1.2V     780mA      920mA      720mA
-1.1V     620mA      770mA      560mA
-1V       470mA      620mA      400mA
-900mV    310mA      470mA      260mA
-800mV    170mA      330mA      120mA
-700mV    54.34mA    200mA      23.62mA
-600mV    4.76mA     82.21mA    2.52mA
-500mV    280uA      14.02mA    260uA
-400mV    16.9uA     860uA      14.85uA
0V        67.85pA    2.04nA     61.89pA
[Ramp]
| variable   typ   min   max
dV/dt_r   0.89/2.40n   0.64/3.39n   1.12/1.80n
dV/dt_f   0.74/2.77n   0.51/3.41n   0.96/2.21n
R_load = 50.00
[Rising Waveform]
R_fixture = 50.00
V_fixture = 0.000
| time   V(typ)   V(min)   V(max)
0s        0V         0V         0V
800ps     -9.5mV     -2.14mV    -4.19mV
1ns       -3.87mV    -7.2mV     77.09mV
1.6ns     130mV      21.52mV    420mV
2.8ns     660mV      240mV      1.28V
3.6ns     950mV      410mV      1.59V
4.2ns     1.14V      550mV      1.73V
5.6ns     1.37V      800mV      1.84V
7.4ns     1.45V      980mV      1.87V
10ns      1.48V      1.11V      1.87V
[Rising Waveform]
R_fixture = 50.00
V_fixture = 3.30
V_fixture_min = 3.00
V_fixture_max = 3.60
| time   V(typ)   V(min)   V(max)
0s        2.04V      2.1V       1.99V
400ps     2.04V      2.1V       1.99V
600ps     2.08V      2.1V       2.21V
800ps     2.31V      2.12V      2.74V
1ns       2.7V       2.3V       3.13V
1.2ns     2.98V      2.55V      3.37V
1.8ns     3.25V      2.9V       3.58V
2.2ns     3.29V      2.97V      3.59V
3ns       3.3V       3V         3.6V
10ns      3.3V       3V         3.6V
[Falling Waveform]
R_fixture = 50.00
V_fixture = 0.000
| time   V(typ)   V(min)   V(max)
0s        1.48V      1.11V      1.87V
600ps     1.48V      1.11V      1.83V
800ps     1.44V      1.11V      1.39V
1ns       1V         1.06V      730mV
1.2ns     530mV      820mV      310mV
1.6ns     130mV      290mV      51.74mV
1.8ns     54.49mV    150mV      14.4mV
2ns       19.74mV    72.33mV    4.33mV
2.6ns     1.56mV     6.92mV     930uV
10ns      24.04uV    62.1uV     10.97uV
[Falling Waveform]
R_fixture = 50.00
V_fixture = 3.30
V_fixture_min = 3.00
V_fixture_max = 3.60
| time   V(typ)   V(min)   V(max)
0s        3.3V       3V         3.6V
800ps     3.31V      3V         3.62V
1ns       3.31V      3V         3.56V
1.4ns     3.26V      3.01V      3.39V
1.8ns     3.14V      2.97V      3.15V
2.8ns     2.75V      2.77V      2.6V
4.2ns     2.4V       2.52V      2.23V
5.4ns     2.23V      2.36V      2.1V
6.2ns     2.17V      2.3V       2.06V
10ns      2.06V      2.1V       2V
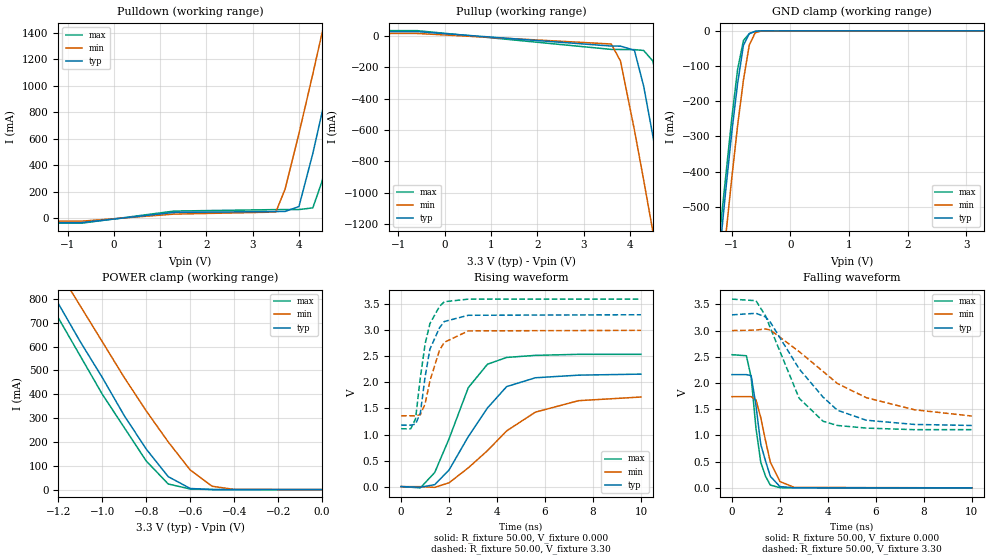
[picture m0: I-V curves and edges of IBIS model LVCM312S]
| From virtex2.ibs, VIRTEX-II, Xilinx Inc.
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|   Model LVCM312S
[Model]   LVCM312S
Model_type   I/O
Polarity   Non-Inverting
Enable   Active-Low
Vinh = 2.0V
Vinl = 0.8V
Vmeas =   1.65V
Cref =  35.00pF
Rref =   1.00M
Vref =  0.000V
C_comp   7.00pF   6.00pF   8.00pF
[Temperature Range]   25.00   100.00   0.000
[Voltage Range]   3.30V   3.00V   3.60V
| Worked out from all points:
|   slope of the pulldown table from 0 to 0.495 V, typ, clamps not added: 21.8 ohm
|   slope of the pullup table from 0 to 0.495 V, typ, clamps not added: 22.7 ohm
|   GND clamp passes 1 mA (typ) near -0.57 V on its own axis
|   POWER clamp passes 1 mA (typ) near -0.52 V on its own axis
|   rising waveform, R_fixture 50.00, V_fixture 0.000: 20-80 % time 1.84ns typ, 2.65ns min, 1.3ns max; typ from 0 V to 2.16 V
|   rising waveform, R_fixture 50.00, V_fixture 3.30: 20-80 % time 561ps typ, 625ps min, 508ps max; typ from 1.18 V to 3.3 V
|   falling waveform, R_fixture 50.00, V_fixture 0.000: 20-80 % time 509ps typ, 554ps min, 378ps max; typ from 2.16 V to 0 V
|   falling waveform, R_fixture 50.00, V_fixture 3.30: 20-80 % time 2.06ns typ, 3.11ns min, 1.39ns max; typ from 3.3 V to 1.19 V
[Pulldown]
| voltage   I(typ)   I(min)   I(max)
-3.3V     -32.1mA    -21.58mA   -36.83mA
-700mV    -32.1mA    -21.58mA   -36.83mA
1.3V      44.67mA    32.07mA    55.03mA
3.5V      51.66mA    47.4mA     66.01mA
3.7V      51.79mA    220mA      66.14mA
4V        89.06mA    640mA      66.32mA
4.3V      490mA      1.09A      79.21mA
4.5V      800mA      1.4A       280mA
4.9V      1.45A      2.02A      900mA
5.1V      1.78A      2.34A      1.23A
5.3V      2.11A      2.65A      1.56A
6.6V      4.27A      4.71A      3.72A
[Pullup]
| voltage   I(typ)   I(min)   I(max)
-3.3V     28.6mA     16.68mA    34.69mA
-600mV    28.6mA     16.68mA    34.69mA
3.6V      -63.99mA   -50.9mA    -85.36mA
3.8V      -64.43mA   -160mA     -85.91mA
4.1V      -90.87mA   -600mA     -86.68mA
4.3V      -320mA     -920mA     -92.25mA
4.5V      -640mA     -1.25A     -160mA
4.7V      -980mA     -1.59A     -440mA
4.9V      -1.32A     -1.93A     -770mA
5.1V      -1.67A     -2.27A     -1.11A
5.3V      -2.02A     -2.61A     -1.46A
6.6V      -4.32A     -4.85A     -3.75A
[GND_clamp]
| voltage   I(typ)   I(min)   I(max)
-3.3V     -4.3A      -4.31A     -4.26A
-1.2V     -620mA     -740mA     -570mA
-1.1V     -450mA     -580mA     -410mA
-1V       -290mA     -420mA     -250mA
-900mV    -150mA     -270mA     -110mA
-800mV    -41.03mA   -140mA     -27.28mA
-700mV    -7.6mA     -40.21mA   -8.18mA
-600mV    -1.42mA    -5.61mA    -1.62mA
-500mV    -130uA     -670uA     -130uA
3.3V      67.85pA    43.48uA    45.6pA
[POWER_clamp]
| voltage   I(typ)   I(min)   I(max)
-3.3V     4.25A      4.22A      4.2A
-1.3V     940mA      1.07A      880mA
-1.2V     780mA      920mA      720mA
-1.1V     620mA      770mA      560mA
-1V       470mA      620mA      400mA
-900mV    310mA      470mA      260mA
-800mV    170mA      330mA      120mA
-700mV    54.34mA    200mA      23.62mA
-600mV    4.76mA     82.21mA    2.52mA
-500mV    280uA      14.02mA    260uA
-400mV    16.9uA     860uA      14.85uA
0V        67.85pA    2.04nA     61.89pA
[Ramp]
| variable   typ   min   max
dV/dt_r   1.29/1.82n   1.03/2.65n   1.52/1.35n
dV/dt_f   1.27/2.07n   0.96/3.00n   1.50/1.44n
R_load = 50.00
[Rising Waveform]
R_fixture = 50.00
V_fixture = 0.000
| time   V(typ)   V(min)   V(max)
0s        0V         0V         0V
800ps     -11.88mV   -1.35mV    -24.42mV
1.4ns     36.64mV    -14.92mV   270mV
2ns       320mV      73.3mV     920mV
2.8ns     960mV      360mV      1.9V
3.6ns     1.51V      690mV      2.35V
4.4ns     1.92V      1.07V      2.48V
5.6ns     2.09V      1.43V      2.52V
7.4ns     2.14V      1.65V      2.54V
10ns      2.16V      1.72V      2.54V
[Rising Waveform]
R_fixture = 50.00
V_fixture = 3.30
V_fixture_min = 3.00
V_fixture_max = 3.60
| time   V(typ)   V(min)   V(max)
0s        1.18V      1.36V      1.11V
400ps     1.18V      1.36V      1.11V
600ps     1.2V       1.36V      1.3V
800ps     1.41V      1.38V      2.09V
1ns       2.11V      1.59V      2.74V
1.2ns     2.64V      2.03V      3.13V
1.6ns     3.05V      2.62V      3.46V
1.8ns     3.17V      2.77V      3.55V
2.8ns     3.29V      2.99V      3.6V
10ns      3.3V       3V         3.6V
[Falling Waveform]
R_fixture = 50.00
V_fixture = 0.000
| time   V(typ)   V(min)   V(max)
0s        2.16V      1.74V      2.54V
600ps     2.16V      1.74V      2.52V
800ps     2.14V      1.74V      2.11V
1ns       1.57V      1.68V      1.14V
1.2ns     830mV      1.34V      490mV
1.4ns     510mV      900mV      220mV
1.6ns     220mV      490mV      53.12mV
2ns       24.41mV    120mV      2.83mV
2.6ns     1.71mV     8.63mV     1.26mV
10ns      22.43uV    71.62uV    9.12uV
[Falling Waveform]
R_fixture = 50.00
V_fixture = 3.30
V_fixture_min = 3.00
V_fixture_max = 3.60
| time   V(typ)   V(min)   V(max)
0s        3.3V       3V         3.6V
1ns       3.33V      3.01V      3.57V
1.4ns     3.26V      3.03V      3.28V
1.6ns     3.16V      3.01V      3.05V
2.8ns     2.27V      2.6V       1.71V
3.8ns     1.73V      2.22V      1.27V
4.4ns     1.48V      1.99V      1.19V
5.6ns     1.29V      1.72V      1.14V
7.6ns     1.21V      1.49V      1.11V
10ns      1.19V      1.37V      1.11V
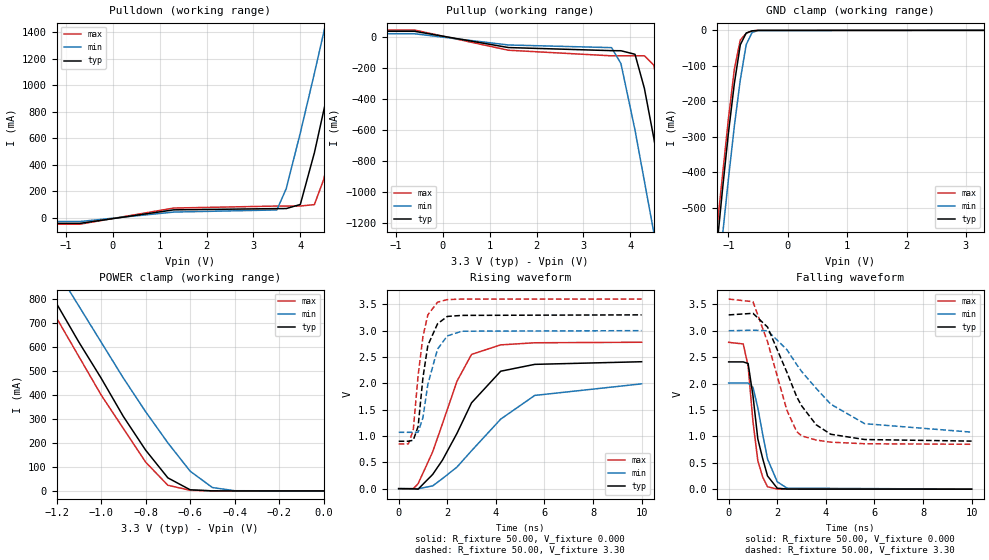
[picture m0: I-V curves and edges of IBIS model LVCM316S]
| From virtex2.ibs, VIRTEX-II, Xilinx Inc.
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|   Model LVCM316S
[Model]   LVCM316S
Model_type   I/O
Polarity   Non-Inverting
Enable   Active-Low
Vinh = 2.0V
Vinl = 0.8V
Vmeas =   1.65V
Cref =  35.00pF
Rref =   1.00M
Vref =  0.000V
C_comp   7.00pF   6.00pF   8.00pF
[Temperature Range]   25.00   100.00   0.000
[Voltage Range]   3.30V   3.00V   3.60V
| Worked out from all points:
|   slope of the pulldown table from 0 to 0.495 V, typ, clamps not added: 16.5 ohm
|   slope of the pullup table from 0 to 0.495 V, typ, clamps not added: 16.9 ohm
|   GND clamp passes 1 mA (typ) near -0.57 V on its own axis
|   POWER clamp passes 1 mA (typ) near -0.52 V on its own axis
|   rising waveform, R_fixture 50.00, V_fixture 0.000: 20-80 % time 1.76ns typ, 2.58ns min, 1.34ns max; typ from 0 V to 2.41 V
|   rising waveform, R_fixture 50.00, V_fixture 3.30: 20-80 % time 440ps typ, 542ps min, 422ps max; typ from 0.9 V to 3.3 V
|   falling waveform, R_fixture 50.00, V_fixture 0.000: 20-80 % time 511ps typ, 559ps min, 375ps max; typ from 2.41 V to 0 V
|   falling waveform, R_fixture 50.00, V_fixture 3.30: 20-80 % time 1.45ns typ, 2.18ns min, 1.04ns max; typ from 3.3 V to 0.91 V
[Pulldown]
| voltage   I(typ)   I(min)   I(max)
-3.3V     -42.66mA   -28.71mA   -48.88mA
-700mV    -42.66mA   -28.71mA   -48.88mA
1.3V      59.43mA    42.7mA     73.14mA
3.5V      68.88mA    58.81mA    88.01mA
3.7V      69.04mA    220mA      88.18mA
4V        100mA      640mA      88.42mA
4.3V      490mA      1.09A      98.99mA
4.5V      810mA      1.4A       290mA
4.9V      1.45A      2.03A      910mA
5.1V      1.78A      2.34A      1.24A
5.3V      2.11A      2.66A      1.56A
6.6V      4.28A      4.72A      3.72A
[Pullup]
| voltage   I(typ)   I(min)   I(max)
-3.3V     38.58mA    22.62mA    46.62mA
-600mV    38.58mA    22.62mA    46.62mA
1.4V      -66.48mA   -49.89mA   -83.88mA
3.6V      -86.56mA   -67.02mA   -120mA
3.8V      -87.11mA   -170mA     -120mA
4.1V      -110mA     -600mA     -120mA
4.3V      -330mA     -930mA     -120mA
4.5V      -650mA     -1.26A     -180mA
4.9V      -1.33A     -1.93A     -780mA
5.1V      -1.68A     -2.27A     -1.12A
5.3V      -2.03A     -2.61A     -1.46A
6.6V      -4.33A     -4.85A     -3.76A
[GND_clamp]
| voltage   I(typ)   I(min)   I(max)
-3.3V     -4.3A      -4.31A     -4.26A
-1.2V     -620mA     -740mA     -570mA
-1.1V     -450mA     -580mA     -410mA
-1V       -290mA     -420mA     -250mA
-900mV    -150mA     -270mA     -110mA
-800mV    -41.03mA   -140mA     -27.28mA
-700mV    -7.6mA     -40.21mA   -8.18mA
-600mV    -1.42mA    -5.61mA    -1.62mA
-500mV    -130uA     -670uA     -130uA
3.3V      67.85pA    43.48uA    45.6pA
[POWER_clamp]
| voltage   I(typ)   I(min)   I(max)
-3.3V     4.25A      4.22A      4.2A
-1.3V     940mA      1.07A      880mA
-1.2V     780mA      920mA      720mA
-1.1V     620mA      770mA      560mA
-1V       470mA      620mA      400mA
-900mV    310mA      470mA      260mA
-800mV    170mA      330mA      120mA
-700mV    54.34mA    200mA      23.62mA
-600mV    4.76mA     82.21mA    2.52mA
-500mV    280uA      14.02mA    260uA
-400mV    16.9uA     860uA      14.85uA
0V        67.85pA    2.04nA     61.89pA
[Ramp]
| variable   typ   min   max
dV/dt_r   1.45/1.75n   1.19/2.59n   1.67/1.29n
dV/dt_f   1.44/1.44n   1.15/2.23n   1.65/1.03n
R_load = 50.00
[Rising Waveform]
R_fixture = 50.00
V_fixture = 0.000
| time   V(typ)   V(min)   V(max)
0s        0V         0V         0V
600ps     -3.12mV    62.66uV    -800uV
800ps     -9.93mV    -1.91mV    93.62mV
1.4ns     270mV      52.35mV    700mV
1.8ns     540mV      190mV      1.23V
2.4ns     1.05V      410mV      2.04V
3ns       1.63V      720mV      2.55V
4.2ns     2.23V      1.32V      2.73V
5.6ns     2.36V      1.77V      2.77V
10ns      2.41V      1.99V      2.78V
[Rising Waveform]
R_fixture = 50.00
V_fixture = 3.30
V_fixture_min = 3.00
V_fixture_max = 3.60
| time   V(typ)   V(min)   V(max)
0s        900mV      1.07V      850mV
400ps     900mV      1.07V      850mV
600ps     920mV      1.07V      1.11V
800ps     1.18V      1.07V      2.15V
1ns       2.11V      1.35V      2.89V
1.2ns     2.72V      1.98V      3.3V
1.6ns     3.13V      2.65V      3.54V
2ns       3.27V      2.9V       3.59V
2.6ns     3.29V      2.99V      3.6V
10ns      3.3V       3V         3.6V
[Falling Waveform]
R_fixture = 50.00
V_fixture = 0.000
| time   V(typ)   V(min)   V(max)
0s        2.41V      2.01V      2.78V
600ps     2.41V      2.01V      2.75V
800ps     2.38V      2.01V      2.33V
1ns       1.77V      1.93V      1.28V
1.2ns     950mV      1.54V      540mV
1.4ns     580mV      1.04V      230mV
1.6ns     250mV      570mV      45.27mV
2ns       18.08mV    140mV      2.31mV
2.4ns     2.34mV     19.46mV    1.65mV
10ns      8.97uV     41.44uV    2.9uV
[Falling Waveform]
R_fixture = 50.00
V_fixture = 3.30
V_fixture_min = 3.00
V_fixture_max = 3.60
| time   V(typ)   V(min)   V(max)
0s        3.3V       3V         3.6V
1ns       3.33V      3.01V      3.55V
1.6ns     3.07V      3V         2.79V
2.4ns     2.21V      2.64V      1.49V
2.8ns     1.75V      2.36V      1.09V
3ns       1.58V      2.23V      1.01V
3.6ns     1.22V      1.91V      930mV
4.2ns     1.04V      1.61V      890mV
5.6ns     940mV      1.24V      860mV
10ns      910mV      1.08V      850mV
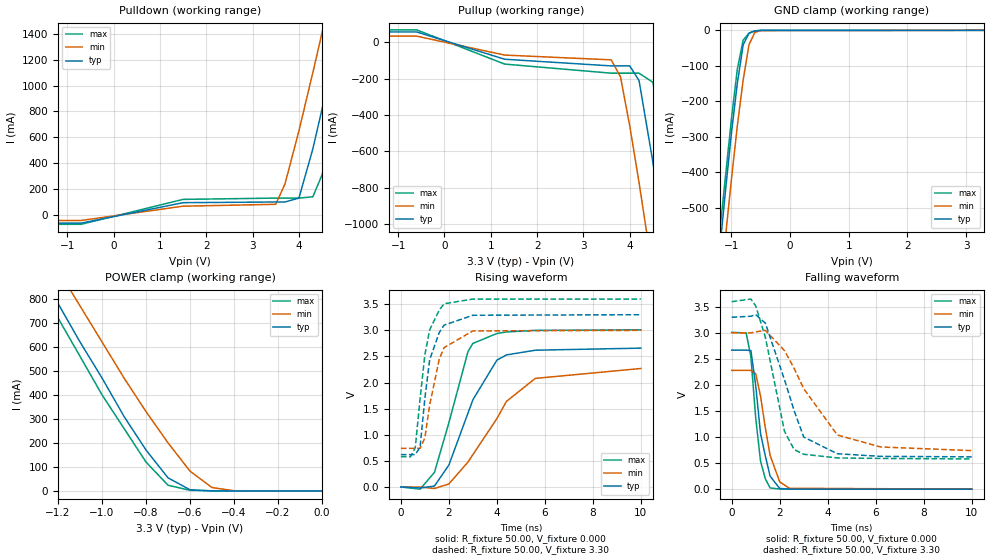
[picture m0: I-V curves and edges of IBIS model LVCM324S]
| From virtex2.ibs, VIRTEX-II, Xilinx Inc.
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|   Model LVCM324S
[Model]   LVCM324S
Model_type   I/O
Polarity   Non-Inverting
Enable   Active-Low
Vinh = 2.0V
Vinl = 0.8V
Vmeas =   1.65V
Cref =  35.00pF
Rref =   1.00M
Vref =  0.000V
C_comp   7.00pF   6.00pF   8.00pF
[Temperature Range]   25.00   100.00   0.000
[Voltage Range]   3.30V   3.00V   3.60V
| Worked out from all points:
|   slope of the pulldown table from 0 to 0.495 V, typ, clamps not added: 11.1 ohm
|   slope of the pullup table from 0 to 0.495 V, typ, clamps not added: 11.5 ohm
|   GND clamp passes 1 mA (typ) near -0.57 V on its own axis
|   POWER clamp passes 1 mA (typ) near -0.52 V on its own axis
|   rising waveform, R_fixture 50.00, V_fixture 0.000: 20-80 % time 1.39ns typ, 2.07ns min, 1.05ns max; typ from 0 V to 2.66 V
|   rising waveform, R_fixture 50.00, V_fixture 3.30: 20-80 % time 552ps typ, 609ps min, 502ps max; typ from 0.62 V to 3.3 V
|   falling waveform, R_fixture 50.00, V_fixture 0.000: 20-80 % time 498ps typ, 537ps min, 362ps max; typ from 2.67 V to 0 V
|   falling waveform, R_fixture 50.00, V_fixture 3.30: 20-80 % time 1.08ns typ, 1.77ns min, 811ps max; typ from 3.3 V to 0.62 V
[Pulldown]
| voltage   I(typ)   I(min)   I(max)
-3.3V     -63.55mA   -42.85mA   -72.64mA
-700mV    -63.55mA   -42.85mA   -72.64mA
1.5V      94.54mA    67.4mA     120mA
3.5V      100mA      82mA       130mA
3.7V      100mA      240mA      130mA
4V        130mA      650mA      130mA
4.3V      510mA      1.1A       140mA
4.5V      820mA      1.41A      310mA
4.9V      1.47A      2.04A      930mA
5.1V      1.79A      2.35A      1.25A
5.3V      2.12A      2.67A      1.58A
6.6V      4.29A      4.73A      3.74A
[Pullup]
| voltage   I(typ)   I(min)   I(max)
-3.3V     56.69mA    33.54mA    68.06mA
-600mV    56.69mA    33.54mA    68.06mA
1.3V      -93.32mA   -70.46mA   -120mA
3.6V      -130mA     -96.72mA   -170mA
3.8V      -130mA     -190mA     -170mA
4V        -130mA     -460mA     -170mA
4.2V      -210mA     -770mA     -170mA
4.5V      -660mA     -1.27A     -220mA
4.9V      -1.34A     -1.94A     -800mA
5.1V      -1.69A     -2.28A     -1.14A
5.3V      -2.04A     -2.62A     -1.48A
6.6V      -4.34A     -4.86A     -3.78A
[GND_clamp]
| voltage   I(typ)   I(min)   I(max)
-3.3V     -4.3A      -4.31A     -4.26A
-1.2V     -620mA     -740mA     -570mA
-1.1V     -450mA     -580mA     -410mA
-1V       -290mA     -420mA     -250mA
-900mV    -150mA     -270mA     -110mA
-800mV    -41.03mA   -140mA     -27.28mA
-700mV    -7.6mA     -40.21mA   -8.18mA
-600mV    -1.42mA    -5.61mA    -1.62mA
-500mV    -130uA     -670uA     -130uA
3.3V      67.85pA    43.48uA    45.6pA
[POWER_clamp]
| voltage   I(typ)   I(min)   I(max)
-3.3V     4.25A      4.22A      4.2A
-1.3V     940mA      1.07A      880mA
-1.2V     780mA      920mA      720mA
-1.1V     620mA      770mA      560mA
-1V       470mA      620mA      400mA
-900mV    310mA      470mA      260mA
-800mV    170mA      330mA      120mA
-700mV    54.34mA    200mA      23.62mA
-600mV    4.76mA     82.21mA    2.52mA
-500mV    280uA      14.02mA    260uA
-400mV    16.9uA     860uA      14.85uA
0V        67.85pA    2.04nA     61.89pA
[Ramp]
| variable   typ   min   max
dV/dt_r   1.60/1.38n   1.36/2.04n   1.81/1.05n
dV/dt_f   1.61/1.12n   1.35/1.79n   1.81/0.79n
R_load = 50.00
[Rising Waveform]
R_fixture = 50.00
V_fixture = 0.000
| time   V(typ)   V(min)   V(max)
0s        0V         0V         0V
800ps     -19.85mV   -1.25mV    -42.15mV
1.4ns     17.82mV    -29.32mV   280mV
2ns       420mV      57.55mV    1.23V
2.8ns     1.42V      480mV      2.6V
3ns       1.67V      620mV      2.75V
4ns       2.43V      1.31V      2.94V
4.4ns     2.53V      1.64V      2.97V
5.6ns     2.62V      2.08V      3V
10ns      2.66V      2.27V      3.01V
[Rising Waveform]
R_fixture = 50.00
V_fixture = 3.30
V_fixture_min = 3.00
V_fixture_max = 3.60
| time   V(typ)   V(min)   V(max)
0s        620mV      740mV      580mV
400ps     620mV      740mV      580mV
600ps     620mV      740mV      750mV
800ps     760mV      740mV      1.69V
1ns       1.7V       940mV      2.53V
1.2ns     2.44V      1.57V      3.01V
1.6ns     2.96V      2.45V      3.39V
1.8ns     3.1V       2.67V      3.51V
3ns       3.29V      2.99V      3.6V
10ns      3.3V       3V         3.6V
[Falling Waveform]
R_fixture = 50.00
V_fixture = 0.000
| time   V(typ)   V(min)   V(max)
0s        2.67V      2.28V      3.01V
600ps     2.67V      2.28V      3V
800ps     2.66V      2.28V      2.54V
1ns       1.99V      2.22V      1.37V
1.2ns     1.07V      1.79V      540mV
1.4ns     640mV      1.18V      200mV
1.6ns     250mV      650mV      23.38mV
2ns       13.27mV    140mV      2.51mV
2.4ns     2.41mV     17.31mV    1.76mV
10ns      10.93uV    52.65uV    1.9uV
[Falling Waveform]
R_fixture = 50.00
V_fixture = 3.30
V_fixture_min = 3.00
V_fixture_max = 3.60
| time   V(typ)   V(min)   V(max)
0s        3.3V       3V         3.6V
800ps     3.32V      3V         3.65V
1ns       3.35V      3.02V      3.52V
1.4ns     3.19V      3.05V      2.92V
2.2ns     2.1V       2.66V      1.11V
2.6ns     1.51V      2.32V      760mV
3ns       1V         1.93V      670mV
4.4ns     680mV      1.04V      600mV
6.2ns     630mV      810mV      590mV
10ns      620mV      740mV      580mV
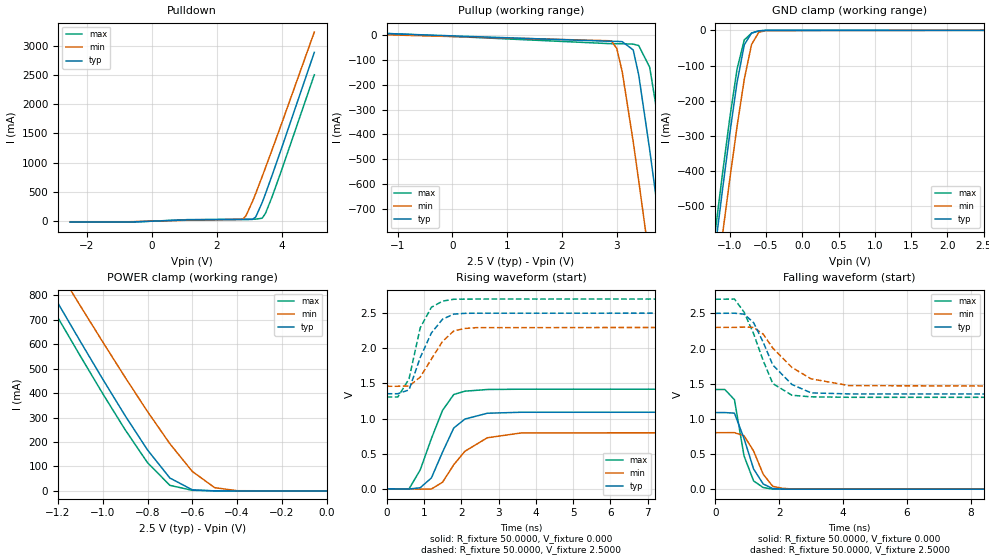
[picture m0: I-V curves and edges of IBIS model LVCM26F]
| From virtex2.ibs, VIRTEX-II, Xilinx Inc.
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|   Model LVCM26F
[Model]   LVCM26F
Model_type   I/O
Polarity   Non-Inverting
Enable   Active-Low
Vinh = 1.7V
Vinl = 0.7V
Vmeas =   1.2500V
Cref =  35.0000pF
Rref =   1.0000M
Vref =  0.000V
C_comp   7.0000pF   6.0000pF   8.0000pF
[Temperature Range]   25.0000   100.0000   0.000
[Voltage Range]   2.5000V   2.3000V   2.7000V
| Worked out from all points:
|   slope of the pulldown table from 0 to 0.375 V, typ, clamps not added: 41.5 ohm
|   slope of the pullup table from 0 to 0.375 V, typ, clamps not added: 42.4 ohm
|   GND clamp passes 1 mA (typ) near -0.57 V on its own axis
|   POWER clamp passes 1 mA (typ) near -0.52 V on its own axis
|   rising waveform, R_fixture 50.0000, V_fixture 0.000: 20-80 % time 562ps typ, 783ps min, 611ps max; typ from 0 V to 1.09 V
|   rising waveform, R_fixture 50.0000, V_fixture 2.5000: 20-80 % time 566ps typ, 623ps min, 425ps max; typ from 1.35 V to 2.5 V
|   falling waveform, R_fixture 50.0000, V_fixture 0.000: 20-80 % time 522ps typ, 528ps min, 407ps max; typ from 1.09 V to 0 V
|   falling waveform, R_fixture 50.0000, V_fixture 2.5000: 20-80 % time 810ps typ, 1.13ns min, 728ps max; typ from 2.5 V to 1.35 V
[Pulldown]
| voltage   I(typ)   I(min)   I(max)
-2.5V     -16.21mA   -10.87mA   -18.67mA
-700mV    -16.21mA   -10.87mA   -18.67mA
1.1V      20.58mA    14.86mA    25.12mA
2.8V      25.66mA    29.83mA    32.86mA
2.9V      25.71mA    91.52mA    32.91mA
3.1V      29.18mA    333.2mA    33mA
3.2V      69.77mA    472.6mA    33.21mA
3.4V      318.6mA    764mA      49.91mA
3.5V      467.1mA    913mA      133mA
3.7V      777.1mA    1.214A     410.9mA
4V        1.255A     1.673A     878.3mA
5V        2.883A     3.23A      2.5A
[Pullup]
| voltage   I(typ)   I(min)   I(max)
-2.5V     16.1mA     9.12mA     20.2mA
2.9V      -24.93mA   -22.85mA   -34.49mA
3V        -25.12mA   -53.66mA   -34.63mA
3.1V      -26.25mA   -148mA     -34.77mA
3.3V      -59.69mA   -430mA     -36.19mA
3.4V      -160.1mA   -586.4mA   -41.95mA
3.6V      -461.1mA   -910.5mA   -129mA
3.7V      -625.5mA   -1.075A    -263.3mA
3.8V      -793.6mA   -1.242A    -418.8mA
4V        -1.135A    -1.578A    -750.4mA
4.2V      -1.482A    -1.917A    -1.092A
5V        -2.889A    -3.286A    -2.494A
[GND_clamp]
| voltage   I(typ)   I(min)   I(max)
-2.5V     -2.881A    -2.936A    -2.838A
-1.2V     -617mA     -740.6mA   -570.6mA
-1.1V     -452.1mA   -579.7mA   -406.1mA
-1V       -293.4mA   -423mA     -249mA
-900mV    -148mA     -273.4mA   -110.1mA
-800mV    -41mA      -138.5mA   -27.22mA
-700mV    -7.569mA   -40.19mA   -8.128mA
-600mV    -1.403mA   -5.589mA   -1.597mA
-500mV    -127.6uA   -662.5uA   -122uA
2.5V      397.5nA    2.548uA    351.3nA
[POWER_clamp]
| voltage   I(typ)   I(min)   I(max)
-2.5V     2.874A     2.908A     2.816A
-1.3V     925.8mA    1.055A     866.1mA
-1.2V     767.5mA    905.5mA    707.7mA
-1.1V     610.9mA    756.3mA    551.2mA
-1V       456.9mA    609.1mA    397.6mA
-900mV    307.7mA    464.5mA    250.2mA
-800mV    167.5mA    324.6mA    115.6mA
-700mV    52.75mA    192.9mA    22.81mA
-600mV    4.571mA    79.88mA    2.444mA
-500mV    271.3uA    13.45mA    251.8uA
-400mV    16.93uA    820.9uA    15.04uA
0V        397.5nA    368nA      428.7nA
[Ramp]
| variable   typ   min   max
dV/dt_r   0.6534/0.6331n   0.4820/0.8027n   0.8502/0.5138n
dV/dt_f   0.6882/0.8758n   0.5046/1.1556n   0.8364/0.6892n
R_load = 50.0000
[Rising Waveform]
R_fixture = 50.0000
V_fixture = 0.000
| time   V(typ)   V(min)   V(max)
0s        11.3uV     12.6uV     11.14uV
600ps     -3.578mV   -338.4uV   -1.901mV
900ps     14.89mV    -5.59mV    268.1mV
1.2ns     153.8mV    -3.37mV    715mV
1.5ns     523.3mV    93.79mV    1.117V
1.8ns     865.2mV    342.8mV    1.342V
2.1ns     992.4mV    534.2mV    1.389V
2.7ns     1.075V     726.1mV    1.413V
3.6ns     1.089V     794.3mV    1.417V
15ns      1.089V     803.3mV    1.417V
[Rising Waveform]
R_fixture = 50.0000
V_fixture = 2.5000
V_fixture_min = 2.3000
V_fixture_max = 2.7000
| time   V(typ)   V(min)   V(max)
0s        1.353V     1.459V     1.306V
300ps     1.353V     1.459V     1.306V
600ps     1.407V     1.462V     1.564V
900ps     1.867V     1.589V     2.291V
1.2ns     2.218V     1.846V     2.583V
1.5ns     2.414V     2.098V     2.671V
1.8ns     2.486V     2.247V     2.697V
2.1ns     2.497V     2.282V     2.699V
2.4ns     2.499V     2.293V     2.7V
15ns      2.5V       2.3V       2.7V
[Falling Waveform]
R_fixture = 50.0000
V_fixture = 0.000
| time   V(typ)   V(min)   V(max)
0s        1.089V     803.3mV    1.417V
300ps     1.089V     803.3mV    1.417V
600ps     1.081V     803.5mV    1.272V
900ps     719.9mV    760.2mV    472.3mV
1.2ns     285.9mV    541.3mV    116.5mV
1.5ns     73.58mV    211.5mV    23.04mV
1.8ns     7.973mV    39.92mV    683.1uV
2.1ns     1.859mV    12.6mV     553.3uV
2.4ns     513.9uV    2.412mV    284.5uV
15ns      4.45uV     -14.4uV    4.513uV
[Falling Waveform]
R_fixture = 50.0000
V_fixture = 2.5000
V_fixture_min = 2.3000
V_fixture_max = 2.7000
| time   V(typ)   V(min)   V(max)
0s        2.5V       2.3V       2.7V
600ps     2.502V     2.3V       2.703V
900ps     2.489V     2.304V     2.519V
1.2ns     2.368V     2.301V     2.209V
1.5ns     2.088V     2.204V     1.826V
1.8ns     1.765V     2.006V     1.502V
2.4ns     1.488V     1.73V      1.335V
3ns       1.369V     1.568V     1.313V
4.2ns     1.354V     1.472V     1.306V
15ns      1.353V     1.459V     1.306V
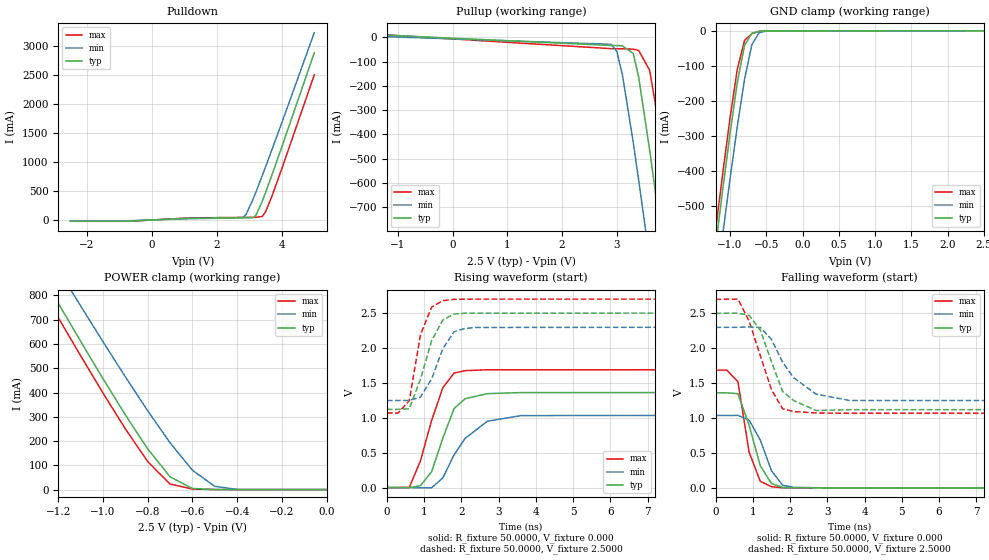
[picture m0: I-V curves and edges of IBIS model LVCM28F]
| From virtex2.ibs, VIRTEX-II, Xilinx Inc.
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|   Model LVCM28F
[Model]   LVCM28F
Model_type   I/O
Polarity   Non-Inverting
Enable   Active-Low
Vinh = 1.7V
Vinl = 0.7V
Vmeas =   1.2500V
Cref =  35.0000pF
Rref =   1.0000M
Vref =  0.000V
C_comp   7.0000pF   6.0000pF   8.0000pF
[Temperature Range]   25.0000   100.0000   0.000
[Voltage Range]   2.5000V   2.3000V   2.7000V
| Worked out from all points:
|   slope of the pulldown table from 0 to 0.375 V, typ, clamps not added: 31.3 ohm
|   slope of the pullup table from 0 to 0.375 V, typ, clamps not added: 31.2 ohm
|   GND clamp passes 1 mA (typ) near -0.57 V on its own axis
|   POWER clamp passes 1 mA (typ) near -0.52 V on its own axis
|   rising waveform, R_fixture 50.0000, V_fixture 0.000: 20-80 % time 543ps typ, 773ps min, 585ps max; typ from 0 V to 1.36 V
|   rising waveform, R_fixture 50.0000, V_fixture 2.5000: 20-80 % time 531ps typ, 537ps min, 392ps max; typ from 1.12 V to 2.5 V
|   falling waveform, R_fixture 50.0000, V_fixture 0.000: 20-80 % time 479ps typ, 506ps min, 375ps max; typ from 1.36 V to 0 V
|   falling waveform, R_fixture 50.0000, V_fixture 2.5000: 20-80 % time 565ps typ, 821ps min, 604ps max; typ from 2.5 V to 1.12 V
[Pulldown]
| voltage   I(typ)   I(min)   I(max)
-2.5V     -21.47mA   -14.42mA   -24.67mA
-700mV    -21.47mA   -14.42mA   -24.67mA
1.1V      27.29mA    19.74mA    33.24mA
2.8V      34.1mA     35.31mA    43.63mA
2.9V      34.17mA    95.43mA    43.7mA
3.1V      37.36mA    336mA      43.83mA
3.2V      75.55mA    475.3mA    44.03mA
3.4V      322.2mA    766.6mA    59.14mA
3.5V      470.5mA    915.6mA    138.9mA
3.7V      780.3mA    1.217A     415.2mA
4V        1.258A     1.675A     882.3mA
5V        2.886A     3.233A     2.504A
[Pullup]
| voltage   I(typ)   I(min)   I(max)
-2.5V     21.93mA    12.45mA    27.44mA
2.9V      -33.99mA   -29.15mA   -47.02mA
3V        -34.2mA    -58.65mA   -47.22mA
3.1V      -35.3mA    -151.4mA   -47.4mA
3.3V      -66.72mA   -432.6mA   -48.79mA
3.4V      -164.6mA   -588.9mA   -54.27mA
3.6V      -464.4mA   -912.8mA   -136.1mA
3.7V      -628.6mA   -1.078A    -268.6mA
3.8V      -796.6mA   -1.244A    -423.5mA
4V        -1.138A    -1.58A     -754.7mA
4.2V      -1.485A    -1.919A    -1.096A
5V        -2.892A    -3.288A    -2.498A
[GND_clamp]
| voltage   I(typ)   I(min)   I(max)
-2.5V     -2.881A    -2.936A    -2.838A
-1.2V     -617mA     -740.6mA   -570.6mA
-1.1V     -452.1mA   -579.7mA   -406.1mA
-1V       -293.4mA   -423mA     -249mA
-900mV    -148mA     -273.4mA   -110.1mA
-800mV    -41mA      -138.5mA   -27.22mA
-700mV    -7.569mA   -40.19mA   -8.128mA
-600mV    -1.403mA   -5.589mA   -1.597mA
-500mV    -127.6uA   -662.5uA   -122uA
2.5V      397.5nA    2.548uA    351.3nA
[POWER_clamp]
| voltage   I(typ)   I(min)   I(max)
-2.5V     2.874A     2.908A     2.816A
-1.3V     925.8mA    1.055A     866.1mA
-1.2V     767.5mA    905.5mA    707.7mA
-1.1V     610.9mA    756.3mA    551.2mA
-1V       456.9mA    609.1mA    397.6mA
-900mV    307.7mA    464.5mA    250.2mA
-800mV    167.5mA    324.6mA    115.6mA
-700mV    52.75mA    192.9mA    22.81mA
-600mV    4.571mA    79.88mA    2.444mA
-500mV    271.3uA    13.45mA    251.8uA
-400mV    16.93uA    820.9uA    15.04uA
0V        397.5nA    368nA      428.7nA
[Ramp]
| variable   typ   min   max
dV/dt_r   0.8172/0.5884n   0.6222/0.7968n   1.0122/0.4596n
dV/dt_f   0.8280/0.6344n   0.6312/0.8589n   0.9792/0.5133n
R_load = 50.0000
[Rising Waveform]
R_fixture = 50.0000
V_fixture = 0.000
| time   V(typ)   V(min)   V(max)
0s        9.398uV    10.7uV     9.175uV
600ps     -2.139mV   73.39uV    2.213mV
900ps     26.68mV    -4.363mV   383.7mV
1.2ns     228.7mV    -2.34mV    962.8mV
1.5ns     707mV      137.8mV    1.43V
1.8ns     1.131V     467.1mV    1.64V
2.1ns     1.273V     706.1mV    1.675V
2.7ns     1.346V     951.1mV    1.688V
3.6ns     1.361V     1.031V     1.687V
15ns      1.362V     1.037V     1.687V
[Rising Waveform]
R_fixture = 50.0000
V_fixture = 2.5000
V_fixture_min = 2.3000
V_fixture_max = 2.7000
| time   V(typ)   V(min)   V(max)
0s        1.12V      1.248V     1.068V
300ps     1.12V      1.248V     1.068V
600ps     1.129V     1.248V     1.246V
900ps     1.552V     1.297V     2.189V
1.2ns     2.105V     1.557V     2.586V
1.5ns     2.4V       1.989V     2.678V
1.8ns     2.487V     2.233V     2.697V
2.1ns     2.498V     2.28V      2.699V
2.4ns     2.499V     2.294V     2.7V
15ns      2.5V       2.3V       2.7V
[Falling Waveform]
R_fixture = 50.0000
V_fixture = 0.000
| time   V(typ)   V(min)   V(max)
0s        1.362V     1.037V     1.687V
300ps     1.362V     1.037V     1.687V
600ps     1.349V     1.038V     1.521V
900ps     898.2mV    971.6mV    512.9mV
1.2ns     315.9mV    686mV      93.49mV
1.5ns     63.08mV    245.9mV    16.31mV
1.8ns     6.221mV    36.76mV    1.592mV
2.1ns     678.5uV    7.669mV    39.65uV
3ns       56.92uV    140.5uV    33.45uV
15ns      2.1uV      -14.42uV   3.639uV
[Falling Waveform]
R_fixture = 50.0000
V_fixture = 2.5000
V_fixture_min = 2.3000
V_fixture_max = 2.7000
| time   V(typ)   V(min)   V(max)
0s        2.5V       2.3V       2.7V
600ps     2.502V     2.3V       2.704V
900ps     2.473V     2.306V     2.391V
1.2ns     2.261V     2.299V     1.896V
1.5ns     1.808V     2.128V     1.408V
1.8ns     1.381V     1.8V       1.134V
2.1ns     1.25V      1.576V     1.093V
2.7ns     1.108V     1.342V     1.073V
3.6ns     1.12V      1.252V     1.069V
15ns      1.12V      1.248V     1.068V
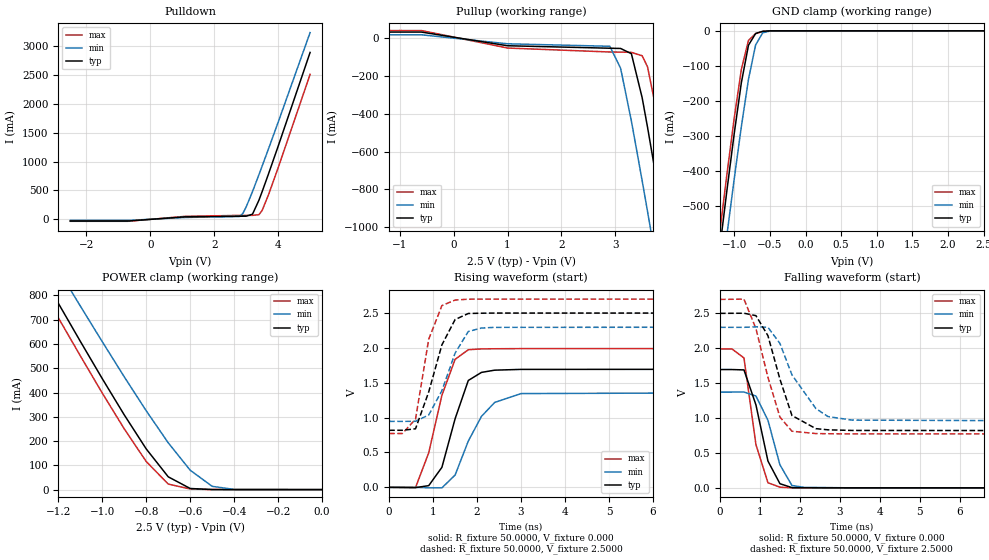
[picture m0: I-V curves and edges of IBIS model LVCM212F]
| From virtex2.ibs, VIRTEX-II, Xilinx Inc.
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|   Model LVCM212F
[Model]   LVCM212F
Model_type   I/O
Polarity   Non-Inverting
Enable   Active-Low
Vinh = 1.7V
Vinl = 0.7V
Vmeas =   1.2500V
Cref =  35.0000pF
Rref =   1.0000M
Vref =  0.000V
C_comp   7.0000pF   6.0000pF   8.0000pF
[Temperature Range]   25.0000   100.0000   0.000
[Voltage Range]   2.5000V   2.3000V   2.7000V
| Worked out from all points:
|   slope of the pulldown table from 0 to 0.375 V, typ, clamps not added: 21 ohm
|   slope of the pullup table from 0 to 0.375 V, typ, clamps not added: 20.5 ohm
|   GND clamp passes 1 mA (typ) near -0.57 V on its own axis
|   POWER clamp passes 1 mA (typ) near -0.52 V on its own axis
|   rising waveform, R_fixture 50.0000, V_fixture 0.000: 20-80 % time 481ps typ, 659ps min, 517ps max; typ from 0 V to 1.7 V
|   rising waveform, R_fixture 50.0000, V_fixture 2.5000: 20-80 % time 521ps typ, 547ps min, 371ps max; typ from 0.819 V to 2.5 V
|   falling waveform, R_fixture 50.0000, V_fixture 0.000: 20-80 % time 442ps typ, 468ps min, 356ps max; typ from 1.7 V to 0 V
|   falling waveform, R_fixture 50.0000, V_fixture 2.5000: 20-80 % time 524ps typ, 740ps min, 548ps max; typ from 2.5 V to 0.819 V
[Pulldown]
| voltage   I(typ)   I(min)   I(max)
-2.5V     -32.1mA    -21.59mA   -36.83mA
-700mV    -32.1mA    -21.59mA   -36.83mA
1.1V      40.81mA    29.56mA    49.67mA
2.8V      51.15mA    46.45mA    65.44mA
2.9V      51.25mA    103.4mA    65.54mA
3V        51.47mA    211.8mA    65.63mA
3.2V      87.53mA    480.7mA    65.92mA
3.4V      329.5mA    771.7mA    78.28mA
3.5V      477.3mA    920.6mA    151mA
3.7V      786.8mA    1.222A     424.4mA
4V        1.264A     1.68A      890.4mA
5V        2.892A     3.237A     2.511A
[Pullup]
| voltage   I(typ)   I(min)   I(max)
-2.5V     33.53mA    19.14mA    41.73mA
-600mV    33.53mA    19.14mA    41.73mA
1V        -38.92mA   -28.63mA   -51.12mA
2.9V      -52.1mA    -41.79mA   -72.07mA
3.1V      -53.39mA   -158.4mA   -72.65mA
3.3V      -81.13mA   -437.8mA   -74mA
3.5V      -314.2mA   -754.1mA   -92.11mA
3.6V      -471mA     -917.4mA   -151mA
3.8V      -802.6mA   -1.249A    -432.8mA
4V        -1.144A    -1.585A    -763.1mA
4.2V      -1.491A    -1.923A    -1.105A
5V        -2.897A    -3.292A    -2.506A
[GND_clamp]
| voltage   I(typ)   I(min)   I(max)
-2.5V     -2.881A    -2.936A    -2.838A
-1.2V     -617mA     -740.6mA   -570.6mA
-1.1V     -452.1mA   -579.7mA   -406.1mA
-1V       -293.4mA   -423mA     -249mA
-900mV    -148mA     -273.4mA   -110.1mA
-800mV    -41mA      -138.5mA   -27.22mA
-700mV    -7.569mA   -40.19mA   -8.128mA
-600mV    -1.403mA   -5.589mA   -1.597mA
-500mV    -127.6uA   -662.5uA   -122uA
2.5V      397.5nA    2.548uA    351.3nA
[POWER_clamp]
| voltage   I(typ)   I(min)   I(max)
-2.5V     2.874A     2.908A     2.816A
-1.3V     925.8mA    1.055A     866.1mA
-1.2V     767.5mA    905.5mA    707.7mA
-1.1V     610.9mA    756.3mA    551.2mA
-1V       456.9mA    609.1mA    397.6mA
-900mV    307.7mA    464.5mA    250.2mA
-800mV    167.5mA    324.6mA    115.6mA
-700mV    52.75mA    192.9mA    22.81mA
-600mV    4.571mA    79.88mA    2.444mA
-500mV    271.3uA    13.45mA    251.8uA
-400mV    16.93uA    820.9uA    15.04uA
0V        397.5nA    368nA      428.7nA
[Ramp]
| variable   typ   min   max
dV/dt_r   1.0170/0.4770n   0.8232/0.6666n   1.1940/0.3612n
dV/dt_f   1.0088/0.5396n   0.8122/0.7968n   1.1564/0.4130n
R_load = 50.0000
[Rising Waveform]
R_fixture = 50.0000
V_fixture = 0.000
| time   V(typ)   V(min)   V(max)
0s        6.981uV    8.2uV      6.726uV
600ps     -3.811mV   -142.7uV   -2.743mV
900ps     24.37mV    -6.917mV   495.5mV
1.2ns     287.3mV    -7.417mV   1.321V
1.5ns     983.5mV    176.2mV    1.836V
1.8ns     1.533V     663.2mV    1.974V
2.1ns     1.649V     1.018V     1.986V
2.4ns     1.681V     1.218V     1.988V
3ns       1.692V     1.345V     1.99V
15ns      1.695V     1.372V     1.99V
[Rising Waveform]
R_fixture = 50.0000
V_fixture = 2.5000
V_fixture_min = 2.3000
V_fixture_max = 2.7000
| time   V(typ)   V(min)   V(max)
0s        818.6mV    946.4mV    772.7mV
300ps     818.6mV    946.4mV    772.7mV
600ps     839.9mV    947.5mV    977.6mV
900ps     1.369V     1.038V     2.125V
1.2ns     2.044V     1.387V     2.607V
1.5ns     2.407V     1.925V     2.687V
1.8ns     2.494V     2.236V     2.699V
2.1ns     2.498V     2.285V     2.7V
2.4ns     2.5V       2.295V     2.7V
15ns      2.5V       2.3V       2.7V
[Falling Waveform]
R_fixture = 50.0000
V_fixture = 0.000
| time   V(typ)   V(min)   V(max)
0s        1.695V     1.372V     1.99V
300ps     1.695V     1.372V     1.99V
600ps     1.69V      1.373V     1.861V
900ps     1.188V     1.315V     618mV
1.2ns     384.1mV    968mV      73.47mV
1.5ns     59.43mV    329.7mV    9.877mV
1.8ns     3.422mV    34.41mV    764uV
2.1ns     1.245mV    7.165mV    432uV
3.3ns     73.81uV    240.1uV    10.53uV
15ns      -27.68uV   11.24uV    9.542uV
[Falling Waveform]
R_fixture = 50.0000
V_fixture = 2.5000
V_fixture_min = 2.3000
V_fixture_max = 2.7000
| time   V(typ)   V(min)   V(max)
0s        2.5V       2.3V       2.7V
600ps     2.502V     2.3V       2.704V
900ps     2.467V     2.307V     2.281V
1.2ns     2.18V      2.3V       1.584V
1.5ns     1.557V     2.069V     1.014V
1.8ns     1.037V     1.619V     811.4mV
2.4ns     848.2mV    1.136V     777.7mV
2.7ns     831.6mV    1.022V     775.4mV
3.3ns     822.5mV    970.7mV    772.9mV
15ns      818.6mV    946.4mV    772.7mV
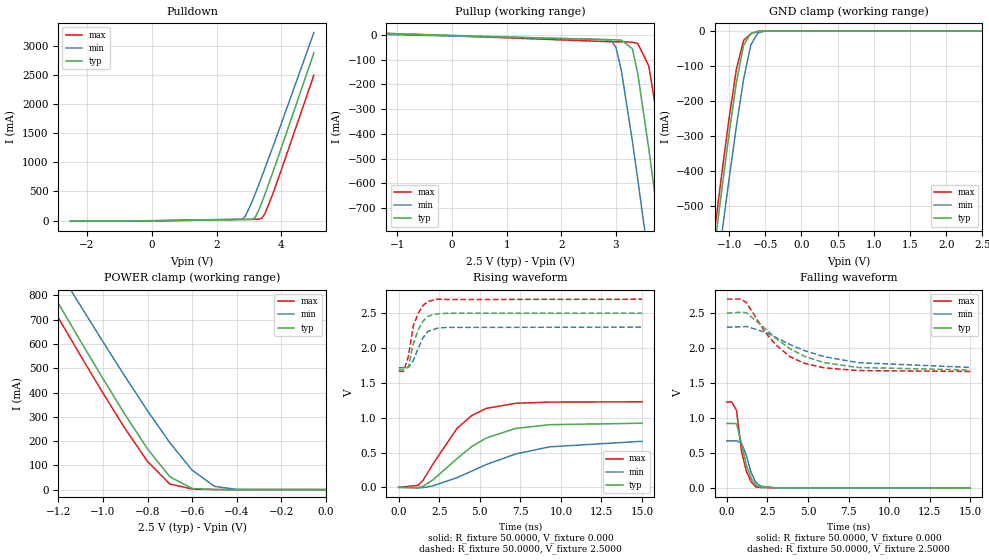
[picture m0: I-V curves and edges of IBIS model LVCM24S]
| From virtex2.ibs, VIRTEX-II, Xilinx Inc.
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|   Model LVCM24S
[Model]   LVCM24S
Model_type   I/O
Polarity   Non-Inverting
Enable   Active-Low
Vinh = 1.7V
Vinl = 0.7V
Vmeas =   1.2500V
Cref =  35.0000pF
Rref =   1.0000M
Vref =  0.000V
C_comp   7.0000pF   6.0000pF   8.0000pF
[Temperature Range]   25.0000   100.0000   0.000
[Voltage Range]   2.5000V   2.3000V   2.7000V
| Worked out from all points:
|   slope of the pulldown table from 0 to 0.375 V, typ, clamps not added: 62.4 ohm
|   slope of the pullup table from 0 to 0.375 V, typ, clamps not added: 51.8 ohm
|   GND clamp passes 1 mA (typ) near -0.57 V on its own axis
|   POWER clamp passes 1 mA (typ) near -0.52 V on its own axis
|   rising waveform, R_fixture 50.0000, V_fixture 0.000: 20-80 % time 3.12ns typ, 4.53ns min, 2.36ns max; typ from 0 V to 0.921 V
|   rising waveform, R_fixture 50.0000, V_fixture 2.5000: 20-80 % time 679ps typ, 695ps min, 599ps max; typ from 1.68 V to 2.5 V
|   falling waveform, R_fixture 50.0000, V_fixture 0.000: 20-80 % time 630ps typ, 591ps min, 528ps max; typ from 0.921 V to 0 V
|   falling waveform, R_fixture 50.0000, V_fixture 2.5000: 20-80 % time 3.05ns typ, 4.04ns min, 2.29ns max; typ from 2.5 V to 1.69 V
[Pulldown]
| voltage   I(typ)   I(min)   I(max)
-2.5V     -10.76mA   -7.231mA   -12.39mA
-700mV    -10.76mA   -7.231mA   -12.39mA
2.8V      17.05mA    24.31mA    21.82mA
2.9V      17.09mA    87.6mA     21.85mA
3.1V      20.89mA    330.3mA    21.92mA
3.2V      63.97mA    469.9mA    22.14mA
3.3V      176mA      614.3mA    24.01mA
3.4V      314.9mA    761.4mA    40.63mA
3.5V      463.7mA    910.5mA    127.1mA
3.7V      773.9mA    1.212A     406.4mA
4V        1.252A     1.67A      874.2mA
5V        2.88A      3.228A     2.496A
[Pullup]
| voltage   I(typ)   I(min)   I(max)
-2.5V     13.18mA    7.45mA     16.56mA
2.9V      -20.4mA    -19.7mA    -28.22mA
3V        -20.57mA   -51.18mA   -28.34mA
3.1V      -21.73mA   -146.2mA   -28.45mA
3.3V      -56.22mA   -428.7mA   -29.9mA
3.4V      -157.9mA   -585.2mA   -35.79mA
3.6V      -459.5mA   -909.3mA   -125.5mA
3.7V      -624mA     -1.074A    -260.7mA
3.8V      -792.1mA   -1.241A    -416.5mA
4V        -1.134A    -1.577A    -748.3mA
4.2V      -1.481A    -1.916A    -1.09A
5V        -2.888A    -3.284A    -2.493A
[GND_clamp]
| voltage   I(typ)   I(min)   I(max)
-2.5V     -2.881A    -2.936A    -2.838A
-1.2V     -617mA     -740.6mA   -570.6mA
-1.1V     -452.1mA   -579.7mA   -406.1mA
-1V       -293.4mA   -423mA     -249mA
-900mV    -148mA     -273.4mA   -110.1mA
-800mV    -41mA      -138.5mA   -27.22mA
-700mV    -7.569mA   -40.19mA   -8.128mA
-600mV    -1.403mA   -5.589mA   -1.597mA
-500mV    -127.6uA   -662.5uA   -122uA
2.5V      397.5nA    2.548uA    351.3nA
[POWER_clamp]
| voltage   I(typ)   I(min)   I(max)
-2.5V     2.874A     2.908A     2.816A
-1.3V     925.8mA    1.055A     866.1mA
-1.2V     767.5mA    905.5mA    707.7mA
-1.1V     610.9mA    756.3mA    551.2mA
-1V       456.9mA    609.1mA    397.6mA
-900mV    307.7mA    464.5mA    250.2mA
-800mV    167.5mA    324.6mA    115.6mA
-700mV    52.75mA    192.9mA    22.81mA
-600mV    4.571mA    79.88mA    2.444mA
-500mV    271.3uA    13.45mA    251.8uA
-400mV    16.93uA    820.9uA    15.04uA
0V        397.5nA    368nA      428.7nA
[Ramp]
| variable   typ   min   max
dV/dt_r   0.5524/3.1098n   0.3969/4.5254n   0.7368/2.3595n
dV/dt_f   0.4884/3.0436n   0.3462/4.0369n   0.6210/2.3154n
R_load = 50.0000
[Rising Waveform]
R_fixture = 50.0000
V_fixture = 0.000
| time   V(typ)   V(min)   V(max)
0s        14.2uV     15.29uV    14.22uV
1.2ns     -4.545mV   -7.187mV   28.56mV
1.5ns     15.83mV    -4.141mV   99.81mV
2.1ns     104.3mV    20.77mV    329.6mV
3.6ns     412.9mV    139.4mV    848.4mV
4.5ns     585.5mV    233.3mV    1.03V
5.4ns     708.5mV    327.3mV    1.134V
7.2ns     845mV      478.5mV    1.206V
9.3ns     899.6mV    581.7mV    1.224V
15ns      920.7mV    661.5mV    1.228V
[Rising Waveform]
R_fixture = 50.0000
V_fixture = 2.5000
V_fixture_min = 2.3000
V_fixture_max = 2.7000
| time   V(typ)   V(min)   V(max)
0s        1.684V     1.717V     1.665V
300ps     1.684V     1.717V     1.665V
600ps     1.734V     1.72V      1.878V
900ps     2.058V     1.819V     2.317V
1.2ns     2.259V     1.996V     2.499V
1.5ns     2.385V     2.147V     2.611V
1.8ns     2.458V     2.239V     2.668V
2.4ns     2.49V      2.285V     2.702V
3ns       2.499V     2.296V     2.697V
15ns      2.499V     2.3V       2.7V
[Falling Waveform]
R_fixture = 50.0000
V_fixture = 0.000
| time   V(typ)   V(min)   V(max)
0s        921.4mV    671.4mV    1.228V
300ps     921.4mV    671.4mV    1.228V
600ps     918.2mV    671.3mV    1.107V
900ps     639.2mV    642.6mV    526.5mV
1.2ns     329.1mV    466.6mV    238.4mV
1.5ns     136.1mV    217.2mV    85.51mV
1.8ns     33.31mV    71.94mV    12.18mV
2.1ns     12.34mV    25.48mV    5.032mV
3ns       1.232mV    424.9uV    215.4uV
15ns      20.3uV     -6.499uV   51.55uV
[Falling Waveform]
R_fixture = 50.0000
V_fixture = 2.5000
V_fixture_min = 2.3000
V_fixture_max = 2.7000
| time   V(typ)   V(min)   V(max)
0s        2.5V       2.3V       2.7V
900ps     2.513V     2.303V     2.7V
1.2ns     2.506V     2.31V      2.651V
2.4ns     2.271V     2.224V     2.215V
3ns       2.143V     2.154V     2.05V
3.9ns     1.988V     2.05V      1.875V
4.8ns     1.881V     1.962V     1.78V
6ns       1.791V     1.877V     1.717V
8.1ns     1.722V     1.791V     1.678V
15ns      1.686V     1.723V     1.665V
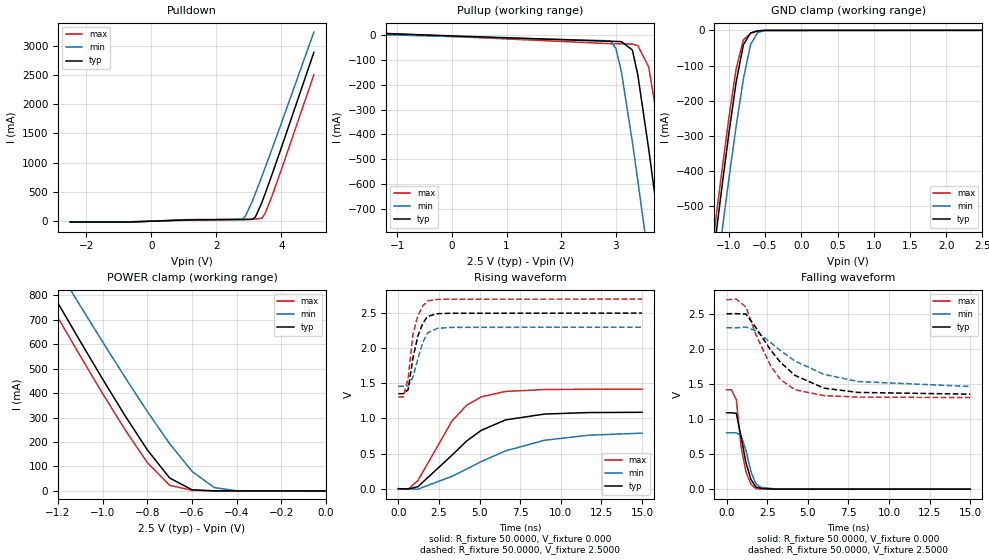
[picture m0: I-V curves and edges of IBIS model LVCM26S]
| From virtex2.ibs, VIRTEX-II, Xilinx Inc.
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|   Model LVCM26S
[Model]   LVCM26S
Model_type   I/O
Polarity   Non-Inverting
Enable   Active-Low
Vinh = 1.7V
Vinl = 0.7V
Vmeas =   1.2500V
Cref =  35.0000pF
Rref =   1.0000M
Vref =  0.000V
C_comp   7.0000pF   6.0000pF   8.0000pF
[Temperature Range]   25.0000   100.0000   0.000
[Voltage Range]   2.5000V   2.3000V   2.7000V
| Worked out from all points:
|   slope of the pulldown table from 0 to 0.375 V, typ, clamps not added: 41.5 ohm
|   slope of the pullup table from 0 to 0.375 V, typ, clamps not added: 42.4 ohm
|   GND clamp passes 1 mA (typ) near -0.57 V on its own axis
|   POWER clamp passes 1 mA (typ) near -0.52 V on its own axis
|   rising waveform, R_fixture 50.0000, V_fixture 0.000: 20-80 % time 3.22ns typ, 4.76ns min, 2.29ns max; typ from 0 V to 1.09 V
|   rising waveform, R_fixture 50.0000, V_fixture 2.5000: 20-80 % time 647ps typ, 666ps min, 544ps max; typ from 1.35 V to 2.5 V
|   falling waveform, R_fixture 50.0000, V_fixture 0.000: 20-80 % time 614ps typ, 589ps min, 502ps max; typ from 1.09 V to 0 V
|   falling waveform, R_fixture 50.0000, V_fixture 2.5000: 20-80 % time 2.55ns typ, 3.59ns min, 1.73ns max; typ from 2.5 V to 1.35 V
[Pulldown]
| voltage   I(typ)   I(min)   I(max)
-2.5V     -16.21mA   -10.87mA   -18.67mA
-700mV    -16.21mA   -10.87mA   -18.67mA
1.1V      20.58mA    14.86mA    25.12mA
2.8V      25.65mA    29.82mA    32.85mA
2.9V      25.71mA    91.52mA    32.9mA
3.1V      29.18mA    333.2mA    33mA
3.2V      69.76mA    472.6mA    33.21mA
3.4V      318.6mA    764mA      49.91mA
3.5V      467.1mA    913mA      133mA
3.7V      777.1mA    1.214A     410.9mA
4V        1.255A     1.673A     878.3mA
5V        2.883A     3.23A      2.5A
[Pullup]
| voltage   I(typ)   I(min)   I(max)
-2.5V     16.1mA     9.12mA     20.2mA
2.9V      -24.93mA   -22.85mA   -34.49mA
3V        -25.12mA   -53.65mA   -34.63mA
3.1V      -26.25mA   -148mA     -34.77mA
3.3V      -59.69mA   -430mA     -36.19mA
3.4V      -160.1mA   -586.4mA   -41.94mA
3.6V      -461.1mA   -910.5mA   -129mA
3.7V      -625.5mA   -1.075A    -263.3mA
3.8V      -793.6mA   -1.242A    -418.8mA
4V        -1.135A    -1.578A    -750.4mA
4.2V      -1.482A    -1.917A    -1.092A
5V        -2.889A    -3.286A    -2.494A
[GND_clamp]
| voltage   I(typ)   I(min)   I(max)
-2.5V     -2.881A    -2.936A    -2.838A
-1.2V     -617mA     -740.6mA   -570.6mA
-1.1V     -452.1mA   -579.7mA   -406.1mA
-1V       -293.4mA   -423mA     -249mA
-900mV    -148mA     -273.4mA   -110.1mA
-800mV    -41mA      -138.5mA   -27.22mA
-700mV    -7.569mA   -40.19mA   -8.128mA
-600mV    -1.403mA   -5.589mA   -1.597mA
-500mV    -127.6uA   -662.5uA   -122uA
2.5V      397.5nA    2.548uA    351.3nA
[POWER_clamp]
| voltage   I(typ)   I(min)   I(max)
-2.5V     2.874A     2.908A     2.816A
-1.3V     925.8mA    1.055A     866.1mA
-1.2V     767.5mA    905.5mA    707.7mA
-1.1V     610.9mA    756.3mA    551.2mA
-1V       456.9mA    609.1mA    397.6mA
-900mV    307.7mA    464.5mA    250.2mA
-800mV    167.5mA    324.6mA    115.6mA
-700mV    52.75mA    192.9mA    22.81mA
-600mV    4.571mA    79.88mA    2.444mA
-500mV    271.3uA    13.45mA    251.8uA
-400mV    16.93uA    820.9uA    15.04uA
0V        397.5nA    368nA      428.7nA
[Ramp]
| variable   typ   min   max
dV/dt_r   0.6528/3.2132n   0.4746/4.7499n   0.8502/2.3197n
dV/dt_f   0.6876/2.5334n   0.5016/3.5807n   0.8364/1.7860n
R_load = 50.0000
[Rising Waveform]
R_fixture = 50.0000
V_fixture = 0.000
| time   V(typ)   V(min)   V(max)
0s        11.3uV     12.6uV     11.14uV
600ps     -3.489mV   -329.4uV   -6.306mV
1.2ns     28.2mV     -6.482mV   115.6mV
3.3ns     477mV      176.6mV    964.3mV
4.2ns     679mV      280.2mV    1.188V
5.1ns     830.8mV    386.2mV    1.308V
6.6ns     979.8mV    538.7mV    1.385V
9ns       1.063V     690mV      1.412V
11.7ns    1.084V     761.7mV    1.416V
15ns      1.088V     791mV      1.417V
[Rising Waveform]
R_fixture = 50.0000
V_fixture = 2.5000
V_fixture_min = 2.3000
V_fixture_max = 2.7000
| time   V(typ)   V(min)   V(max)
0s        1.353V     1.459V     1.306V
300ps     1.353V     1.459V     1.306V
600ps     1.409V     1.461V     1.567V
900ps     1.865V     1.591V     2.206V
1.2ns     2.174V     1.849V     2.462V
1.5ns     2.354V     2.082V     2.602V
1.8ns     2.454V     2.22V      2.675V
2.4ns     2.492V     2.283V     2.695V
3.3ns     2.498V     2.297V     2.698V
15ns      2.5V       2.3V       2.7V
[Falling Waveform]
R_fixture = 50.0000
V_fixture = 0.000
| time   V(typ)   V(min)   V(max)
0s        1.089V     803.2mV    1.417V
300ps     1.089V     803.2mV    1.417V
600ps     1.081V     803.4mV    1.278V
900ps     739.8mV    759.6mV    593.8mV
1.2ns     372.3mV    547.9mV    243mV
1.5ns     138.4mV    250.6mV    70.96mV
1.8ns     31.51mV    76.86mV    7.566mV
2.1ns     11.09mV    26.8mV     3.143mV
3ns       413.4uV    2.809mV    815.2uV
15ns      -10.58uV   37.48uV    38.58uV
[Falling Waveform]
R_fixture = 50.0000
V_fixture = 2.5000
V_fixture_min = 2.3000
V_fixture_max = 2.7000
| time   V(typ)   V(min)   V(max)
0s        2.5V       2.3V       2.7V
600ps     2.502V     2.3V       2.71V
1.2ns     2.496V     2.312V     2.594V
1.8ns     2.305V     2.256V     2.206V
2.7ns     1.988V     2.092V     1.764V
3.3ns     1.814V     1.979V     1.566V
4.2ns     1.623V     1.828V     1.417V
6ns       1.44V      1.637V     1.333V
8.1ns     1.379V     1.534V     1.312V
15ns      1.354V     1.464V     1.306V
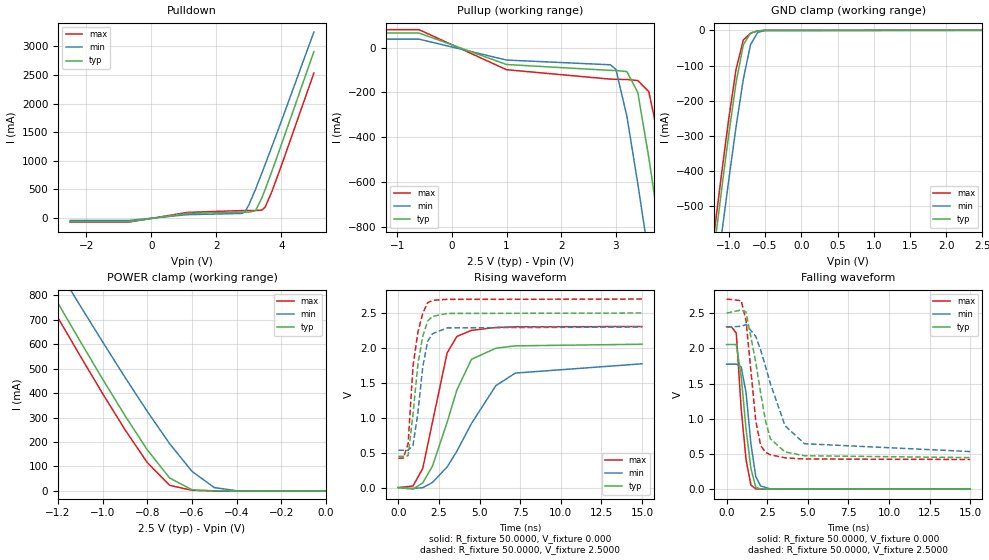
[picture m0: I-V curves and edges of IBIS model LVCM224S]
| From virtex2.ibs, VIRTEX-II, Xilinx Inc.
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|   Model LVCM224S
[Model]   LVCM224S
Model_type   I/O
Polarity   Non-Inverting
Enable   Active-Low
Vinh = 1.7V
Vinl = 0.7V
Vmeas =   1.2500V
Cref =  35.0000pF
Rref =   1.0000M
Vref =  0.000V
C_comp   7.0000pF   6.0000pF   8.0000pF
[Temperature Range]   25.0000   100.0000   0.000
[Voltage Range]   2.5000V   2.3000V   2.7000V
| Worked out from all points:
|   slope of the pulldown table from 0 to 0.375 V, typ, clamps not added: 10.7 ohm
|   slope of the pullup table from 0 to 0.375 V, typ, clamps not added: 10.6 ohm
|   GND clamp passes 1 mA (typ) near -0.57 V on its own axis
|   POWER clamp passes 1 mA (typ) near -0.52 V on its own axis
|   rising waveform, R_fixture 50.0000, V_fixture 0.000: 20-80 % time 1.73ns typ, 2.69ns min, 1.24ns max; typ from 0 V to 2.05 V
|   rising waveform, R_fixture 50.0000, V_fixture 2.5000: 20-80 % time 640ps typ, 597ps min, 555ps max; typ from 0.448 V to 2.5 V
|   falling waveform, R_fixture 50.0000, V_fixture 0.000: 20-80 % time 564ps typ, 526ps min, 479ps max; typ from 2.05 V to 0 V
|   falling waveform, R_fixture 50.0000, V_fixture 2.5000: 20-80 % time 913ps typ, 1.5ns min, 605ps max; typ from 2.5 V to 0.448 V
[Pulldown]
| voltage   I(typ)   I(min)   I(max)
-2.5V     -63.55mA   -42.86mA   -72.65mA
-700mV    -63.55mA   -42.86mA   -72.65mA
1.1V      80.91mA    58.77mA    98.16mA
2.8V      102.3mA    80.57mA    130.8mA
2.9V      102.4mA    128mA      131mA
3V        102.7mA    231.1mA    131.2mA
3.2V      125.9mA    497mA      131.6mA
3.4V      351.8mA    787.1mA    138.6mA
3.5V      497.9mA    935.8mA    190.1mA
3.7V      806.1mA    1.237A     451.4mA
4V        1.283A     1.695A     914.8mA
5V        2.91A      3.252A     2.535A
[Pullup]
| voltage   I(typ)   I(min)   I(max)
-2.5V     64.88mA    37.65mA    79.8mA
-600mV    64.88mA    37.65mA    79.8mA
1V        -75.49mA   -55.69mA   -98.73mA
2.9V      -101.8mA   -76.75mA   -140.8mA
3V        -102.3mA   -97.7mA    -141.4mA
3.2V      -107mA     -305.7mA   -142.5mA
3.4V      -200.1mA   -607.2mA   -147.1mA
3.6V      -489.3mA   -930mA     -196.2mA
3.7V      -652.2mA   -1.094A    -310mA
4V        -1.16A     -1.597A    -786.4mA
4.2V      -1.506A    -1.935A    -1.127A
5V        -2.913A    -3.304A    -2.527A
[GND_clamp]
| voltage   I(typ)   I(min)   I(max)
-2.5V     -2.881A    -2.936A    -2.838A
-1.2V     -617mA     -740.6mA   -570.6mA
-1.1V     -452.1mA   -579.7mA   -406.1mA
-1V       -293.4mA   -423mA     -249mA
-900mV    -148mA     -273.4mA   -110.1mA
-800mV    -41mA      -138.5mA   -27.22mA
-700mV    -7.569mA   -40.19mA   -8.128mA
-600mV    -1.403mA   -5.589mA   -1.597mA
-500mV    -127.6uA   -662.5uA   -122uA
2.5V      397.5nA    2.548uA    351.3nA
[POWER_clamp]
| voltage   I(typ)   I(min)   I(max)
-2.5V     2.874A     2.908A     2.816A
-1.3V     925.8mA    1.055A     866.1mA
-1.2V     767.5mA    905.5mA    707.7mA
-1.1V     610.9mA    756.3mA    551.2mA
-1V       456.9mA    609.1mA    397.6mA
-900mV    307.7mA    464.5mA    250.2mA
-800mV    167.5mA    324.6mA    115.6mA
-700mV    52.75mA    192.9mA    22.81mA
-600mV    4.571mA    79.88mA    2.444mA
-500mV    271.3uA    13.45mA    251.8uA
-400mV    16.93uA    820.9uA    15.04uA
0V        397.5nA    368nA      428.7nA
[Ramp]
| variable   typ   min   max
dV/dt_r   1.2318/1.7155n   1.0638/2.6796n   1.3842/1.2381n
dV/dt_f   1.2313/0.9134n   1.0596/1.4895n   1.3672/0.6487n
R_load = 50.0000
[Rising Waveform]
R_fixture = 50.0000
V_fixture = 0.000
| time   V(typ)   V(min)   V(max)
0s        3.831uV    4.714uV    3.644uV
900ps     -22.64mV   -11.53mV   22.71mV
1.5ns     68.03mV    -1.937mV   273.7mV
2.1ns     308.1mV    74.15mV    937.8mV
3ns       935.4mV    294.5mV    1.927V
3.6ns     1.397V     521mV      2.164V
4.5ns     1.837V     918mV      2.252V
6ns       1.996V     1.46V      2.293V
7.2ns     2.03V      1.64V      2.303V
15ns      2.053V     1.773V     2.307V
[Rising Waveform]
R_fixture = 50.0000
V_fixture = 2.5000
V_fixture_min = 2.3000
V_fixture_max = 2.7000
| time   V(typ)   V(min)   V(max)
0s        447.9mV    533.7mV    421.4mV
300ps     447.9mV    533.7mV    421.5mV
600ps     456.1mV    533.6mV    630.9mV
900ps     1.05V      603.5mV    1.737V
1.2ns     1.764V     1.069V     2.225V
1.5ns     2.166V     1.726V     2.496V
1.8ns     2.386V     2.095V     2.647V
2.1ns     2.451V     2.203V     2.682V
3ns       2.494V     2.287V     2.696V
15ns      2.5V       2.3V       2.7V
[Falling Waveform]
R_fixture = 50.0000
V_fixture = 0.000
| time   V(typ)   V(min)   V(max)
0s        2.054V     1.776V     2.307V
300ps     2.054V     1.776V     2.307V
600ps     2.054V     1.776V     2.216V
900ps     1.603V     1.738V     1.145V
1.2ns     854.5mV    1.372V     420.7mV
1.5ns     292.9mV    645.6mV    57.54mV
1.8ns     24.45mV    177.4mV    3.551mV
2.1ns     4.799mV    45.54mV    1.808mV
2.7ns     1.67mV     3.968mV    1.367mV
15ns      12.85uV    -26.84uV   -24.02uV
[Falling Waveform]
R_fixture = 50.0000
V_fixture = 2.5000
V_fixture_min = 2.3000
V_fixture_max = 2.7000
| time   V(typ)   V(min)   V(max)
0s        2.5V       2.3V       2.7V
900ps     2.545V     2.314V     2.678V
1.2ns     2.515V     2.337V     2.395V
1.8ns     1.8V       2.168V     966.8mV
2.1ns     1.365V     1.976V     620.3mV
2.4ns     970.4mV    1.742V     524.1mV
2.7ns     713.9mV    1.498V     488.6mV
3.6ns     528.7mV    900.4mV    444.6mV
4.8ns     474.6mV    645.5mV    428.6mV
15ns      447.9mV    534mV      421.4mV
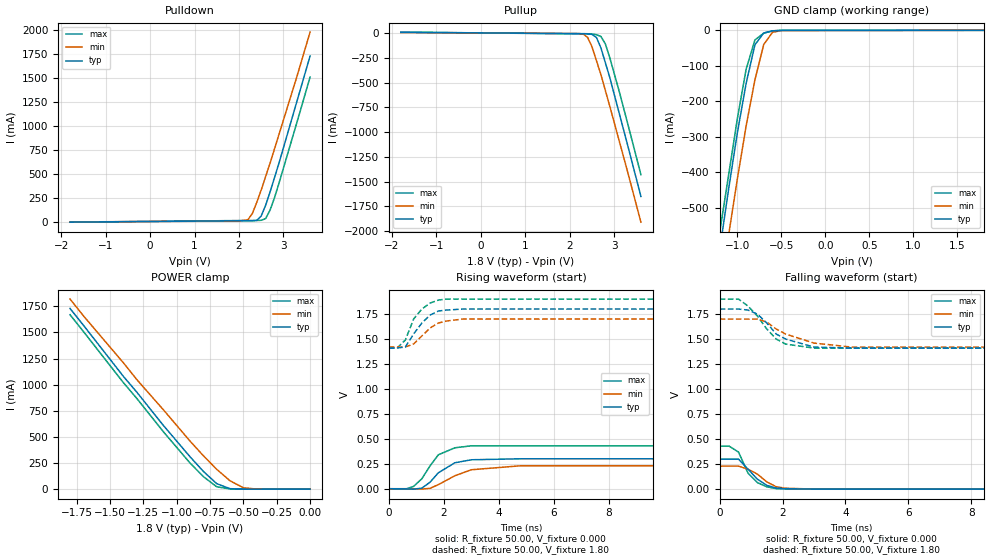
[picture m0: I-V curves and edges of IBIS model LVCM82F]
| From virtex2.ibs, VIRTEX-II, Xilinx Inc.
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|   Model LVCM82F
[Model]   LVCM82F
Model_type   I/O
Polarity   Non-Inverting
Enable   Active-Low
Vinh = 1.19V
Vinl = 0.4V
Vmeas =   0.90V
Cref =  35.00pF
Rref =   1.00M
Vref =  0.000V
C_comp   7.00pF   6.00pF   8.00pF
[Temperature Range]   25.00   100.00   0.000
[Voltage Range]   1.80V   1.70V   1.90V
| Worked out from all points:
|   slope of the pulldown table from 0 to 0.27 V, typ, clamps not added: 118 ohm
|   slope of the pullup table from 0 to 0.27 V, typ, clamps not added: 109 ohm
|   GND clamp passes 1 mA (typ) near -0.57 V on its own axis
|   POWER clamp passes 1 mA (typ) near -0.52 V on its own axis
|   rising waveform, R_fixture 50.00, V_fixture 0.000: 20-80 % time 780ps typ, 1.11ns min, 679ps max; typ from 0 V to 0.3 V
|   rising waveform, R_fixture 50.00, V_fixture 1.80: 20-80 % time 676ps typ, 707ps min, 584ps max; typ from 1.41 V to 1.8 V
|   falling waveform, R_fixture 50.00, V_fixture 0.000: 20-80 % time 611ps typ, 665ps min, 497ps max; typ from 0.3 V to 0 V
|   falling waveform, R_fixture 50.00, V_fixture 1.80: 20-80 % time 897ps typ, 1.15ns min, 792ps max; typ from 1.8 V to 1.41 V
[Pulldown]
| voltage   I(typ)   I(min)   I(max)
-1.8V     -5.48mA    -3.66mA    -6.34mA
2V        8.41mA     6.05mA     10.81mA
2.2V      8.5mA      18.77mA    10.9mA
2.3V      8.76mA     83.67mA    10.94mA
2.4V      12.68mA    200mA      11.18mA
2.5V      58.29mA    330mA      13.22mA
2.6V      170mA      470mA      31.64mA
2.7V      310mA      610mA      120mA
2.8V      460mA      760mA      250mA
2.9V      610mA      910mA      400mA
3.3V      1.25A      1.51A      1.03A
3.6V      1.73A      1.98A      1.51A
[Pullup]
| voltage   I(typ)   I(min)   I(max)
-1.8V     7.03mA     3.91mA     9.08mA
2.2V      -6.44mA    -5.43mA    -9.16mA
2.3V      -6.58mA    -10.18mA   -9.22mA
2.4V      -7.82mA    -43.74mA   -9.37mA
2.5V      -13.78mA   -140mA     -10.77mA
2.6V      -45.73mA   -280mA     -17.07mA
2.7V      -150mA     -420mA     -35.16mA
2.8V      -300mA     -580mA     -110mA
2.9V      -450mA     -740mA     -250mA
3.1V      -790mA     -1.07A     -570mA
3.3V      -1.13A     -1.4A      -910mA
3.6V      -1.65A     -1.91A     -1.43A
[GND_clamp]
| voltage   I(typ)   I(min)   I(max)
-1.8V     -1.65A     -1.74A     -1.6A
-1.2V     -620mA     -740mA     -570mA
-1.1V     -450mA     -580mA     -410mA
-1V       -290mA     -420mA     -250mA
-900mV    -150mA     -270mA     -110mA
-800mV    -40.97mA   -140mA     -27.17mA
-700mV    -7.54mA    -40.17mA   -8.08mA
-600mV    -1.39mA    -5.57mA    -1.57mA
-500mV    -120uA     -660uA     -120uA
1.8V      34.27pA    98.88nA    22.46pA
[POWER_clamp]
| voltage   I(typ)   I(min)   I(max)
-1.8V     1.73A      1.82A      1.67A
-1.7V     1.57A      1.66A      1.51A
-1.4V     1.08A      1.21A      1.02A
-1.3V     930mA      1.05A      870mA
-1.1V     610mA      760mA      550mA
-900mV    310mA      460mA      250mA
-800mV    170mA      320mA      120mA
-700mV    52.75mA    190mA      22.81mA
-600mV    4.57mA     79.88mA    2.44mA
-500mV    270uA      13.45mA    250uA
-400mV    16.38uA    820uA      14.46uA
0V        34.27pA    1.07nA     29.84pA
[Ramp]
| variable   typ   min   max
dV/dt_r   0.18/0.86n   0.14/1.09n   0.26/0.72n
dV/dt_f   0.24/0.95n   0.17/1.18n   0.29/0.77n
R_load = 50.00
[Rising Waveform]
R_fixture = 50.00
V_fixture = 0.000
| time   V(typ)   V(min)   V(max)
0s        0V         0V         0V
600ps     -960uV     -32.74uV   -4.16mV
900ps     -4.48mV    -1.61mV    23.43mV
1.2ns     5.86mV     -3.62mV    100mV
1.5ns     65.97mV    4.13mV     230mV
1.8ns     160mV      41.1mV     340mV
2.4ns     260mV      130mV      410mV
3ns       290mV      190mV      430mV
4.8ns     300mV      230mV      430mV
15ns      300mV      230mV      430mV
[Rising Waveform]
R_fixture = 50.00
V_fixture = 1.80
V_fixture_min = 1.70
V_fixture_max = 1.90
| time   V(typ)   V(min)   V(max)
0s        1.41V      1.42V      1.41V
300ps     1.41V      1.42V      1.41V
600ps     1.42V      1.42V      1.49V
900ps     1.55V      1.45V      1.7V
1.2ns     1.66V      1.53V      1.8V
1.5ns     1.74V      1.61V      1.86V
1.8ns     1.78V      1.66V      1.89V
2.1ns     1.79V      1.68V      1.9V
2.7ns     1.8V       1.7V       1.9V
15ns      1.8V       1.7V       1.9V
[Falling Waveform]
R_fixture = 50.00
V_fixture = 0.000
| time   V(typ)   V(min)   V(max)
0s        300mV      230mV      430mV
300ps     300mV      230mV      430mV
600ps     300mV      230mV      370mV
900ps     200mV      200mV      160mV
1.2ns     99.3mV     150mV      65.2mV
1.5ns     37.63mV    72.49mV    22.95mV
1.8ns     10.08mV    23.19mV    4.96mV
2.1ns     4.38mV     9.14mV     2.15mV
3ns       45.22uV    490uV      -220uV
15ns      63.99uV    -17.48uV   -9.69uV
[Falling Waveform]
R_fixture = 50.00
V_fixture = 1.80
V_fixture_min = 1.70
V_fixture_max = 1.90
| time   V(typ)   V(min)   V(max)
0s        1.8V       1.7V       1.9V
600ps     1.8V       1.7V       1.9V
900ps     1.79V      1.7V       1.83V
1.2ns     1.75V      1.7V       1.73V
1.5ns     1.66V      1.67V      1.6V
1.8ns     1.55V      1.6V       1.5V
2.1ns     1.5V       1.55V      1.45V
3ns       1.42V      1.46V      1.41V
4.2ns     1.41V      1.42V      1.41V
15ns      1.41V      1.42V      1.41V
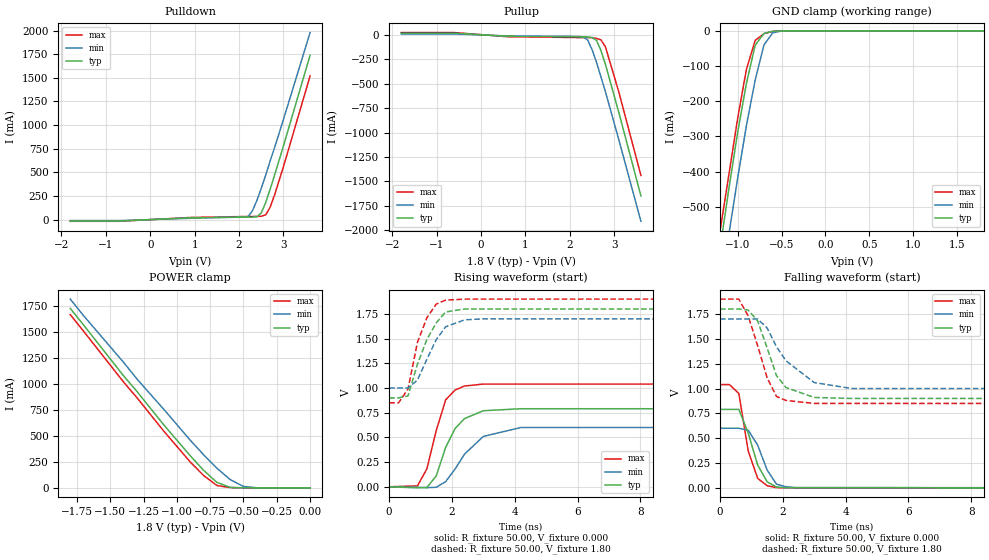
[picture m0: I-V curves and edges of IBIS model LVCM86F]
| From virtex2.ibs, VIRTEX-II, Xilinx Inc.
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|   Model LVCM86F
[Model]   LVCM86F
Model_type   I/O
Polarity   Non-Inverting
Enable   Active-Low
Vinh = 1.19V
Vinl = 0.4V
Vmeas =   0.90V
Cref =  35.00pF
Rref =   1.00M
Vref =  0.000V
C_comp   7.00pF   6.00pF   8.00pF
[Temperature Range]   25.00   100.00   0.000
[Voltage Range]   1.80V   1.70V   1.90V
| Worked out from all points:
|   slope of the pulldown table from 0 to 0.27 V, typ, clamps not added: 40.1 ohm
|   slope of the pullup table from 0 to 0.27 V, typ, clamps not added: 38.7 ohm
|   GND clamp passes 1 mA (typ) near -0.57 V on its own axis
|   POWER clamp passes 1 mA (typ) near -0.52 V on its own axis
|   rising waveform, R_fixture 50.00, V_fixture 0.000: 20-80 % time 676ps typ, 912ps min, 532ps max; typ from 0 V to 0.79 V
|   rising waveform, R_fixture 50.00, V_fixture 1.80: 20-80 % time 679ps typ, 676ps min, 531ps max; typ from 0.9 V to 1.8 V
|   falling waveform, R_fixture 50.00, V_fixture 0.000: 20-80 % time 531ps typ, 526ps min, 416ps max; typ from 0.79 V to 0 V
|   falling waveform, R_fixture 50.00, V_fixture 1.80: 20-80 % time 658ps typ, 971ps min, 639ps max; typ from 1.8 V to 0.9 V
[Pulldown]
| voltage   I(typ)   I(min)   I(max)
-1.8V     -16.21mA   -10.88mA   -18.68mA
-700mV    -16.21mA   -10.88mA   -18.68mA
900mV     18.14mA    13.2mA     21.9mA
2.2V      25.3mA     29.45mA    32.42mA
2.3V      25.57mA    91.27mA    32.53mA
2.4V      28.85mA    200mA      32.79mA
2.5V      69.55mA    330mA      34.56mA
2.6V      180mA      470mA      49.6mA
2.7V      320mA      620mA      130mA
2.8V      470mA      760mA      260mA
3V        780mA      1.06A      560mA
3.6V      1.74A      1.98A      1.52A
[Pullup]
| voltage   I(typ)   I(min)   I(max)
-1.8V     19.87mA    11.13mA    25.49mA
-600mV    19.87mA    11.13mA    25.49mA
600mV     -12.68mA   -9.53mA    -17.16mA
2.2V      -18.23mA   -14.18mA   -25.95mA
2.3V      -18.43mA   -18.65mA   -26.1mA
2.4V      -19.61mA   -50.36mA   -26.33mA
2.5V      -25.25mA   -150mA     -27.63mA
2.6V      -54.62mA   -280mA     -33.58mA
2.7V      -160mA     -430mA     -50.04mA
2.8V      -300mA     -580mA     -120mA
3.1V      -790mA     -1.07A     -580mA
3.6V      -1.65A     -1.91A     -1.44A
[GND_clamp]
| voltage   I(typ)   I(min)   I(max)
-1.8V     -1.65A     -1.74A     -1.6A
-1.2V     -620mA     -740mA     -570mA
-1.1V     -450mA     -580mA     -410mA
-1V       -290mA     -420mA     -250mA
-900mV    -150mA     -270mA     -110mA
-800mV    -40.97mA   -140mA     -27.17mA
-700mV    -7.54mA    -40.17mA   -8.08mA
-600mV    -1.39mA    -5.57mA    -1.57mA
-500mV    -120uA     -660uA     -120uA
1.8V      34.27pA    98.88nA    22.46pA
[POWER_clamp]
| voltage   I(typ)   I(min)   I(max)
-1.8V     1.73A      1.82A      1.67A
-1.7V     1.57A      1.66A      1.51A
-1.4V     1.08A      1.21A      1.02A
-1.3V     930mA      1.05A      870mA
-1.1V     610mA      760mA      550mA
-900mV    310mA      460mA      250mA
-800mV    170mA      320mA      120mA
-700mV    52.75mA    190mA      22.81mA
-600mV    4.57mA     79.88mA    2.44mA
-500mV    270uA      13.45mA    250uA
-400mV    16.38uA    820uA      14.46uA
0V        34.27pA    1.07nA     29.84pA
[Ramp]
| variable   typ   min   max
dV/dt_r   0.48/0.68n   0.36/0.87n   0.63/0.56n
dV/dt_f   0.54/0.71n   0.42/0.99n   0.63/0.56n
R_load = 50.00
[Rising Waveform]
R_fixture = 50.00
V_fixture = 0.000
| time   V(typ)   V(min)   V(max)
0s        0V         0V         0V
900ps     -11.21mV   -4.83mV    8.49mV
1.2ns     -8.4mV     -9.37mV    180mV
1.5ns     110mV      -5.23mV    570mV
1.8ns     400mV      52.38mV    880mV
2.1ns     590mV      180mV      980mV
2.4ns     690mV      330mV      1.02V
3ns       770mV      510mV      1.04V
4.2ns     790mV      600mV      1.04V
15ns      790mV      600mV      1.04V
[Rising Waveform]
R_fixture = 50.00
V_fixture = 1.80
V_fixture_min = 1.70
V_fixture_max = 1.90
| time   V(typ)   V(min)   V(max)
0s        900mV      1V         850mV
300ps     900mV      1V         850mV
600ps     920mV      1V         990mV
900ps     1.24V      1.08V      1.46V
1.2ns     1.49V      1.29V      1.71V
1.5ns     1.66V      1.49V      1.85V
1.8ns     1.77V      1.62V      1.89V
2.4ns     1.8V       1.69V      1.9V
3ns       1.8V       1.7V       1.9V
15ns      1.8V       1.7V       1.9V
[Falling Waveform]
R_fixture = 50.00
V_fixture = 0.000
| time   V(typ)   V(min)   V(max)
0s        790mV      600mV      1.04V
300ps     790mV      600mV      1.04V
600ps     790mV      600mV      950mV
900ps     550mV      580mV      370mV
1.2ns     230mV      430mV      95.72mV
1.5ns     61.49mV    180mV      21.96mV
1.8ns     8mV        37.06mV    2.31mV
2.1ns     2.39mV     10.87mV    250uV
2.4ns     1.07mV     3.7mV      280uV
15ns      10.25uV    2.52uV     10.57uV
[Falling Waveform]
R_fixture = 50.00
V_fixture = 1.80
V_fixture_min = 1.70
V_fixture_max = 1.90
| time   V(typ)   V(min)   V(max)
0s        1.8V       1.7V       1.9V
600ps     1.8V       1.7V       1.9V
900ps     1.79V      1.7V       1.73V
1.2ns     1.68V      1.7V       1.43V
1.5ns     1.41V      1.61V      1.11V
1.8ns     1.13V      1.42V      920mV
2.1ns     1.01V      1.28V      880mV
3ns       910mV      1.06V      850mV
4.2ns     900mV      1V         850mV
15ns      900mV      1V         850mV
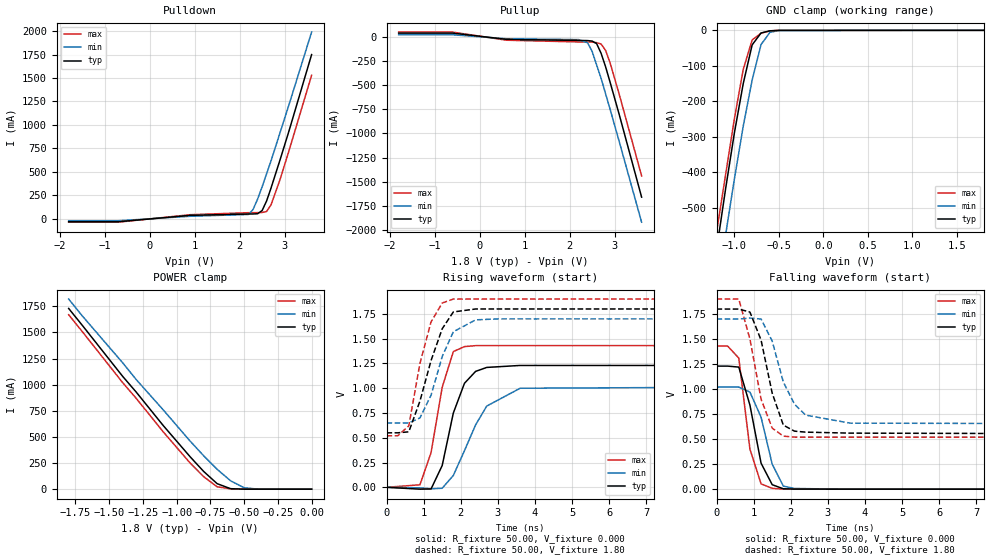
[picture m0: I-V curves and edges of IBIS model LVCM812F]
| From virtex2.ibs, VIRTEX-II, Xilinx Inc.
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|   Model LVCM812F
[Model]   LVCM812F
Model_type   I/O
Polarity   Non-Inverting
Enable   Active-Low
Vinh = 1.19V
Vinl = 0.4V
Vmeas =   0.90V
Cref =  35.00pF
Rref =   1.00M
Vref =  0.000V
C_comp   7.00pF   6.00pF   8.00pF
[Temperature Range]   25.00   100.00   0.000
[Voltage Range]   1.80V   1.70V   1.90V
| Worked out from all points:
|   slope of the pulldown table from 0 to 0.27 V, typ, clamps not added: 20.3 ohm
|   slope of the pullup table from 0 to 0.27 V, typ, clamps not added: 19.5 ohm
|   GND clamp passes 1 mA (typ) near -0.57 V on its own axis
|   POWER clamp passes 1 mA (typ) near -0.52 V on its own axis
|   rising waveform, R_fixture 50.00, V_fixture 0.000: 20-80 % time 519ps typ, 793ps min, 471ps max; typ from 0 V to 1.23 V
|   rising waveform, R_fixture 50.00, V_fixture 1.80: 20-80 % time 621ps typ, 595ps min, 483ps max; typ from 0.55 V to 1.8 V
|   falling waveform, R_fixture 50.00, V_fixture 0.000: 20-80 % time 433ps typ, 478ps min, 344ps max; typ from 1.23 V to 0 V
|   falling waveform, R_fixture 50.00, V_fixture 1.80: 20-80 % time 514ps typ, 600ps min, 501ps max; typ from 1.8 V to 0.55 V
[Pulldown]
| voltage   I(typ)   I(min)   I(max)
-1.8V     -32.1mA    -21.59mA   -36.84mA
-700mV    -32.1mA    -21.59mA   -36.84mA
900mV     35.92mA    26.22mA    43.22mA
2.2V      50.41mA    45.67mA    64.56mA
2.3V      50.73mA    100mA      64.77mA
2.4V      53.28mA    210mA      65.06mA
2.5V      87.07mA    340mA      66.53mA
2.6V      190mA      480mA      77.64mA
2.7V      330mA      620mA      150mA
2.9V      630mA      920mA      420mA
3.1V      940mA      1.22A      730mA
3.6V      1.75A      1.99A      1.53A
[Pullup]
| voltage   I(typ)   I(min)   I(max)
-1.8V     39.53mA    22.35mA    50.25mA
-600mV    39.53mA    22.35mA    50.25mA
600mV     -25.23mA   -18.99mA   -34.06mA
2.2V      -36.44mA   -27.71mA   -51.87mA
2.4V      -37.84mA   -60.77mA   -52.52mA
2.5V      -43.04mA   -150mA     -53.71mA
2.6V      -68.77mA   -290mA     -59.14mA
2.7V      -170mA     -430mA     -73.59mA
2.8V      -310mA     -590mA     -140mA
2.9V      -470mA     -750mA     -270mA
3.1V      -800mA     -1.08A     -590mA
3.6V      -1.66A     -1.92A     -1.44A
[GND_clamp]
| voltage   I(typ)   I(min)   I(max)
-1.8V     -1.65A     -1.74A     -1.6A
-1.2V     -620mA     -740mA     -570mA
-1.1V     -450mA     -580mA     -410mA
-1V       -290mA     -420mA     -250mA
-900mV    -150mA     -270mA     -110mA
-800mV    -40.97mA   -140mA     -27.17mA
-700mV    -7.54mA    -40.17mA   -8.08mA
-600mV    -1.39mA    -5.57mA    -1.57mA
-500mV    -120uA     -660uA     -120uA
1.8V      34.27pA    98.88nA    22.46pA
[POWER_clamp]
| voltage   I(typ)   I(min)   I(max)
-1.8V     1.73A      1.82A      1.67A
-1.7V     1.57A      1.66A      1.51A
-1.4V     1.08A      1.21A      1.02A
-1.3V     930mA      1.05A      870mA
-1.1V     610mA      760mA      550mA
-900mV    310mA      460mA      250mA
-800mV    170mA      320mA      120mA
-700mV    52.75mA    190mA      22.81mA
-600mV    4.57mA     79.88mA    2.44mA
-500mV    270uA      13.45mA    250uA
-400mV    16.38uA    820uA      14.46uA
0V        34.27pA    1.07nA     29.83pA
[Ramp]
| variable   typ   min   max
dV/dt_r   0.74/0.55n   0.61/0.77n   0.86/0.40n
dV/dt_f   0.75/0.45n   0.63/0.65n   0.83/0.35n
R_load = 50.00
[Rising Waveform]
R_fixture = 50.00
V_fixture = 0.000
| time   V(typ)   V(min)   V(max)
0s        0V         0V         0V
900ps     -18.69mV   -5.72mV    25.58mV
1.2ns     -16.49mV   -15.19mV   350mV
1.5ns     220mV      -9.48mV    1.01V
1.8ns     750mV      120mV      1.37V
2.1ns     1.05V      370mV      1.42V
2.4ns     1.17V      630mV      1.43V
2.7ns     1.21V      820mV      1.43V
3.6ns     1.23V      1V         1.43V
15ns      1.23V      1.02V      1.43V
[Rising Waveform]
R_fixture = 50.00
V_fixture = 1.80
V_fixture_min = 1.70
V_fixture_max = 1.90
| time   V(typ)   V(min)   V(max)
0s        550mV      650mV      520mV
300ps     550mV      650mV      520mV
600ps     560mV      650mV      620mV
900ps     870mV      700mV      1.25V
1.2ns     1.28V      930mV      1.67V
1.5ns     1.6V       1.32V      1.86V
1.8ns     1.77V      1.57V      1.9V
2.4ns     1.8V       1.69V      1.9V
3ns       1.8V       1.7V       1.9V
15ns      1.8V       1.7V       1.9V
[Falling Waveform]
R_fixture = 50.00
V_fixture = 0.000
| time   V(typ)   V(min)   V(max)
0s        1.23V      1.02V      1.43V
300ps     1.23V      1.02V      1.43V
600ps     1.22V      1.02V      1.31V
900ps     840mV      970mV      400mV
1.2ns     260mV      720mV      53.29mV
1.5ns     44.69mV    250mV      8.23mV
1.8ns     3.76mV     30.47mV    1.05mV
2.1ns     1.13mV     7.13mV     2.67uV
3.3ns     47.75uV    130uV      24.59uV
15ns      6.8uV      -10.19uV   20.01uV
[Falling Waveform]
R_fixture = 50.00
V_fixture = 1.80
V_fixture_min = 1.70
V_fixture_max = 1.90
| time   V(typ)   V(min)   V(max)
0s        1.8V       1.7V       1.9V
600ps     1.8V       1.7V       1.9V
900ps     1.77V      1.71V      1.5V
1.2ns     1.49V      1.7V       900mV
1.5ns     960mV      1.48V      610mV
1.8ns     640mV      1.07V      530mV
2.1ns     580mV      850mV      520mV
2.4ns     570mV      740mV      520mV
3.6ns     560mV      660mV      520mV
15ns      550mV      650mV      520mV
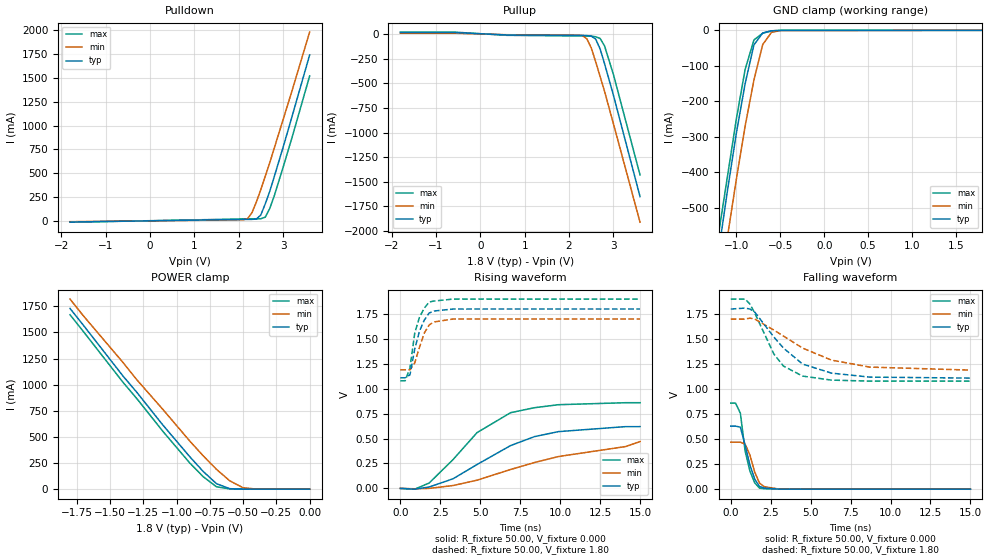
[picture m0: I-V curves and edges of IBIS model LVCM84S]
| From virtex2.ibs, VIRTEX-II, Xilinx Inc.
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|   Model LVCM84S
[Model]   LVCM84S
Model_type   I/O
Polarity   Non-Inverting
Enable   Active-Low
Vinh = 1.19V
Vinl = 0.4V
Vmeas =   0.90V
Cref =  35.00pF
Rref =   1.00M
Vref =  0.000V
C_comp   7.00pF   6.00pF   8.00pF
[Temperature Range]   25.00   100.00   0.000
[Voltage Range]   1.80V   1.70V   1.90V
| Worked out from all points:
|   slope of the pulldown table from 0 to 0.27 V, typ, clamps not added: 60.3 ohm
|   slope of the pullup table from 0 to 0.27 V, typ, clamps not added: 50.5 ohm
|   GND clamp passes 1 mA (typ) near -0.57 V on its own axis
|   POWER clamp passes 1 mA (typ) near -0.52 V on its own axis
|   rising waveform, R_fixture 50.00, V_fixture 0.000: 20-80 % time 4.34ns typ, 6.53ns min, 3.33ns max; typ from 0 V to 0.62 V
|   rising waveform, R_fixture 50.00, V_fixture 1.80: 20-80 % time 699ps typ, 683ps min, 624ps max; typ from 1.11 V to 1.8 V
|   falling waveform, R_fixture 50.00, V_fixture 0.000: 20-80 % time 651ps typ, 606ps min, 564ps max; typ from 0.63 V to 0 V
|   falling waveform, R_fixture 50.00, V_fixture 1.80: 20-80 % time 2.52ns typ, 3.63ns min, 1.67ns max; typ from 1.8 V to 1.11 V
[Pulldown]
| voltage   I(typ)   I(min)   I(max)
-1.8V     -10.76mA   -7.23mA    -12.39mA
2.1V      16.75mA    12.75mA    21.45mA
2.2V      16.82mA    24.06mA    21.53mA
2.3V      17.09mA    87.43mA    21.61mA
2.4V      20.67mA    200mA      21.85mA
2.5V      63.83mA    330mA      23.76mA
2.6V      180mA      470mA      40.43mA
2.7V      310mA      610mA      130mA
2.8V      460mA      760mA      260mA
3V        770mA      1.06A      560mA
3.2V      1.09A      1.36A      870mA
3.6V      1.74A      1.98A      1.52A
[Pullup]
| voltage   I(typ)   I(min)   I(max)
-1.8V     15.21mA    8.5mA      19.56mA
-600mV    15.21mA    8.5mA      19.56mA
600mV     -9.7mA     -7.29mA    -13.14mA
2.2V      -13.94mA   -11mA      -19.85mA
2.3V      -14.12mA   -15.57mA   -19.97mA
2.4V      -15.32mA   -47.94mA   -20.16mA
2.5V      -21.08mA   -140mA     -21.5mA
2.6V      -51.36mA   -280mA     -27.58mA
2.7V      -150mA     -430mA     -44.6mA
2.8V      -300mA     -580mA     -120mA
3V        -620mA     -910mA     -410mA
3.6V      -1.65A     -1.91A     -1.43A
[GND_clamp]
| voltage   I(typ)   I(min)   I(max)
-1.8V     -1.65A     -1.74A     -1.6A
-1.2V     -620mA     -740mA     -570mA
-1.1V     -450mA     -580mA     -410mA
-1V       -290mA     -420mA     -250mA
-900mV    -150mA     -270mA     -110mA
-800mV    -40.97mA   -140mA     -27.17mA
-700mV    -7.54mA    -40.17mA   -8.08mA
-600mV    -1.39mA    -5.57mA    -1.57mA
-500mV    -120uA     -660uA     -120uA
1.8V      34.27pA    98.88nA    22.46pA
[POWER_clamp]
| voltage   I(typ)   I(min)   I(max)
-1.8V     1.73A      1.82A      1.67A
-1.7V     1.57A      1.66A      1.51A
-1.4V     1.08A      1.21A      1.02A
-1.3V     930mA      1.05A      870mA
-1.1V     610mA      760mA      550mA
-900mV    310mA      460mA      250mA
-800mV    170mA      320mA      120mA
-700mV    52.75mA    190mA      22.81mA
-600mV    4.57mA     79.88mA    2.44mA
-500mV    270uA      13.45mA    250uA
-400mV    16.38uA    820uA      14.46uA
0V        34.27pA    1.07nA     29.84pA
[Ramp]
| variable   typ   min   max
dV/dt_r   0.37/4.38n   0.26/5.69n   0.51/3.28n
dV/dt_f   0.41/2.49n   0.31/3.61n   0.49/1.74n
R_load = 50.00
[Rising Waveform]
R_fixture = 50.00
V_fixture = 0.000
| time   V(typ)   V(min)   V(max)
0s        0V         0V         0V
900ps     -7.6mV     -3.86mV    -7.47mV
1.8ns     13.97mV    23.5uV     53.82mV
3.3ns     96.96mV    28.87mV    290mV
4.8ns     240mV      82.58mV    560mV
6.9ns     430mV      190mV      760mV
8.4ns     520mV      260mV      810mV
9.9ns     570mV      320mV      840mV
14.1ns    620mV      420mV      860mV
15ns      620mV      470mV      860mV
[Rising Waveform]
R_fixture = 50.00
V_fixture = 1.80
V_fixture_min = 1.70
V_fixture_max = 1.90
| time   V(typ)   V(min)   V(max)
0s        1.11V      1.19V      1.08V
300ps     1.11V      1.19V      1.08V
600ps     1.14V      1.19V      1.21V
900ps     1.4V       1.26V      1.56V
1.2ns     1.58V      1.42V      1.72V
1.5ns     1.69V      1.56V      1.81V
1.8ns     1.76V      1.64V      1.87V
2.1ns     1.78V      1.67V      1.88V
3.3ns     1.8V       1.7V       1.9V
15ns      1.8V       1.7V       1.9V
[Falling Waveform]
R_fixture = 50.00
V_fixture = 0.000
| time   V(typ)   V(min)   V(max)
0s        630mV      470mV      860mV
300ps     630mV      470mV      860mV
600ps     620mV      470mV      760mV
900ps     440mV      450mV      380mV
1.2ns     240mV      340mV      180mV
1.5ns     100mV      170mV      63.23mV
1.8ns     26.01mV    60.29mV    10.48mV
2.1ns     11.01mV    24.61mV    4.47mV
3ns       730uV      1.51mV     370uV
15ns      34.63uV    30.28uV    46.84uV
[Falling Waveform]
R_fixture = 50.00
V_fixture = 1.80
V_fixture_min = 1.70
V_fixture_max = 1.90
| time   V(typ)   V(min)   V(max)
0s        1.8V       1.7V       1.9V
900ps     1.81V      1.7V       1.9V
1.2ns     1.8V       1.71V      1.85V
1.5ns     1.77V      1.7V       1.76V
2.7ns     1.52V      1.59V      1.35V
3.3ns     1.41V      1.53V      1.23V
4.5ns     1.25V      1.41V      1.13V
6.3ns     1.16V      1.29V      1.09V
8.7ns     1.12V      1.22V      1.08V
15ns      1.11V      1.19V      1.08V
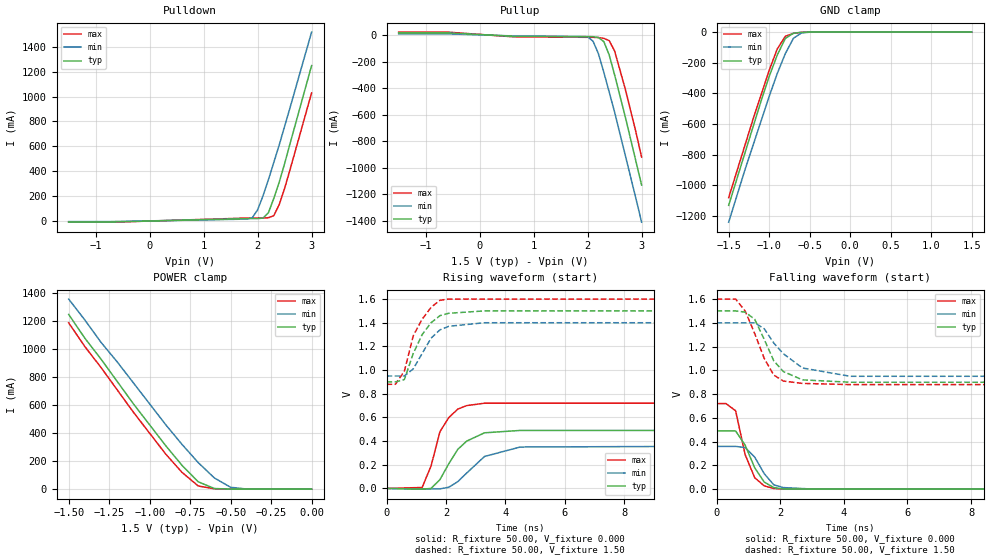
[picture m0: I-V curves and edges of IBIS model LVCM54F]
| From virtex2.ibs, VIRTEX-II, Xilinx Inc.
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|   Model LVCM54F
[Model]   LVCM54F
Model_type   I/O
Polarity   Non-Inverting
Enable   Active-Low
Vinh = 1.05V
Vinl = 0.3V
Vmeas =   0.75V
Cref =  35.00pF
Rref =   1.00M
Vref =  0.000V
C_comp   7.00pF   6.00pF   8.00pF
[Temperature Range]   25.00   100.00   0.000
[Voltage Range]   1.50V   1.40V   1.60V
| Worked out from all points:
|   slope of the pulldown table from 0 to 0.225 V, typ, clamps not added: 59.4 ohm
|   slope of the pullup table from 0 to 0.225 V, typ, clamps not added: 50.4 ohm
|   GND clamp passes 1 mA (typ) near -0.57 V on its own axis
|   POWER clamp passes 1 mA (typ) near -0.52 V on its own axis
|   rising waveform, R_fixture 50.00, V_fixture 0.000: 20-80 % time 815ps typ, 1.02ns min, 616ps max; typ from 0 V to 0.49 V
|   rising waveform, R_fixture 50.00, V_fixture 1.50: 20-80 % time 704ps typ, 702ps min, 644ps max; typ from 0.9 V to 1.5 V
|   falling waveform, R_fixture 50.00, V_fixture 0.000: 20-80 % time 559ps typ, 553ps min, 458ps max; typ from 0.49 V to 0 V
|   falling waveform, R_fixture 50.00, V_fixture 1.50: 20-80 % time 712ps typ, 980ps min, 693ps max; typ from 1.5 V to 0.9 V
[Pulldown]
| voltage   I(typ)   I(min)   I(max)
-1.5V     -10.77mA   -7.22mA    -12.39mA
-700mV    -10.77mA   -7.22mA    -12.39mA
1.8V      16.48mA    12.48mA    21.06mA
1.9V      16.6mA     23.85mA    21.23mA
2V        16.9mA     87.3mA     21.36mA
2.1V      20.52mA    200mA      21.65mA
2.2V      63.73mA    330mA      23.59mA
2.3V      180mA      470mA      40.3mA
2.4V      310mA      610mA      130mA
2.5V      460mA      760mA      260mA
2.6V      620mA      910mA      410mA
3V        1.25A      1.52A      1.03A
[Pullup]
| voltage   I(typ)   I(min)   I(max)
-1.5V     17.09mA    9.31mA     22.57mA
-600mV    17.09mA    9.31mA     22.57mA
600mV     -8.48mA    -6.17mA    -12.49mA
2V        -11.06mA   -13.11mA   -16.84mA
2.1V      -12.28mA   -46.02mA   -17.04mA
2.2V      -18.12mA   -140mA     -18.41mA
2.3V      -49.07mA   -280mA     -24.56mA
2.4V      -150mA     -430mA     -41.88mA
2.5V      -300mA     -580mA     -120mA
2.7V      -620mA     -910mA     -410mA
2.9V      -960mA     -1.24A     -740mA
3V        -1.13A     -1.41A     -920mA
[GND_clamp]
| voltage   I(typ)   I(min)   I(max)
-1.5V     -1.13A     -1.24A     -1.08A
-1.3V     -790mA     -900mA     -740mA
-1.2V     -620mA     -740mA     -570mA
-1.1V     -450mA     -580mA     -410mA
-1V       -290mA     -420mA     -250mA
-900mV    -150mA     -270mA     -110mA
-800mV    -40.96mA   -140mA     -27.15mA
-700mV    -7.52mA    -40.16mA   -8.06mA
-600mV    -1.38mA    -5.56mA    -1.57mA
-500mV    -120uA     -650uA     -120uA
1.5V      27.96pA    98.69nA    16.96pA
[POWER_clamp]
| voltage   I(typ)   I(min)   I(max)
-1.5V     1.25A      1.36A      1.19A
-1.4V     1.08A      1.21A      1.02A
-1.3V     930mA      1.05A      870mA
-1.2V     770mA      910mA      710mA
-1.1V     610mA      760mA      550mA
-900mV    310mA      460mA      250mA
-800mV    170mA      320mA      120mA
-700mV    52.75mA    190mA      22.81mA
-600mV    4.57mA     79.88mA    2.44mA
-500mV    270uA      13.45mA    250uA
-400mV    16.38uA    820uA      14.46uA
0V        27.96pA    880pA      24.27pA
[Ramp]
| variable   typ   min   max
dV/dt_r   0.30/0.78n   0.21/0.98n   0.43/0.65n
dV/dt_f   0.36/0.77n   0.27/1.00n   0.43/0.61n
R_load = 50.00
[Rising Waveform]
R_fixture = 50.00
V_fixture = 0.000
| time   V(typ)   V(min)   V(max)
0s        0V         0V         0V
1.2ns     -6.12mV    -5.87mV    8.06mV
1.5ns     110uV      -4.58mV    190mV
1.8ns     75.21mV    -3.46mV    480mV
2.1ns     210mV      10.33mV    600mV
2.4ns     330mV      57.48mV    670mV
2.7ns     400mV      130mV      700mV
3.3ns     470mV      270mV      720mV
4.5ns     490mV      350mV      720mV
15ns      490mV      360mV      720mV
[Rising Waveform]
R_fixture = 50.00
V_fixture = 1.50
V_fixture_min = 1.40
V_fixture_max = 1.60
| time   V(typ)   V(min)   V(max)
0s        900mV      950mV      880mV
300ps     900mV      950mV      880mV
600ps     920mV      950mV      990mV
900ps     1.14V      1.01V      1.29V
1.2ns     1.3V       1.14V      1.43V
1.5ns     1.4V       1.27V      1.53V
1.8ns     1.46V      1.34V      1.59V
2.1ns     1.48V      1.37V      1.6V
3.3ns     1.5V       1.4V       1.6V
15ns      1.5V       1.4V       1.6V
[Falling Waveform]
R_fixture = 50.00
V_fixture = 0.000
| time   V(typ)   V(min)   V(max)
0s        490mV      360mV      720mV
300ps     490mV      360mV      720mV
600ps     490mV      360mV      660mV
900ps     370mV      350mV      290mV
1.2ns     180mV      270mV      96.38mV
1.5ns     59.59mV    130mV      27.57mV
1.8ns     13.36mV    36.41mV    5.71mV
2.1ns     1.85mV     13.39mV    980uV
3ns       180uV      1.12mV     75.47uV
15ns      -12.7uV    9.41uV     -34.2uV
[Falling Waveform]
R_fixture = 50.00
V_fixture = 1.50
V_fixture_min = 1.40
V_fixture_max = 1.60
| time   V(typ)   V(min)   V(max)
0s        1.5V       1.4V       1.6V
600ps     1.5V       1.4V       1.6V
900ps     1.49V      1.4V       1.5V
1.2ns     1.43V      1.4V       1.31V
1.5ns     1.26V      1.35V      1.1V
1.8ns     1.08V      1.23V      960mV
2.1ns     990mV      1.14V      910mV
2.7ns     920mV      1.02V      890mV
4.2ns     900mV      950mV      880mV
15ns      900mV      950mV      880mV
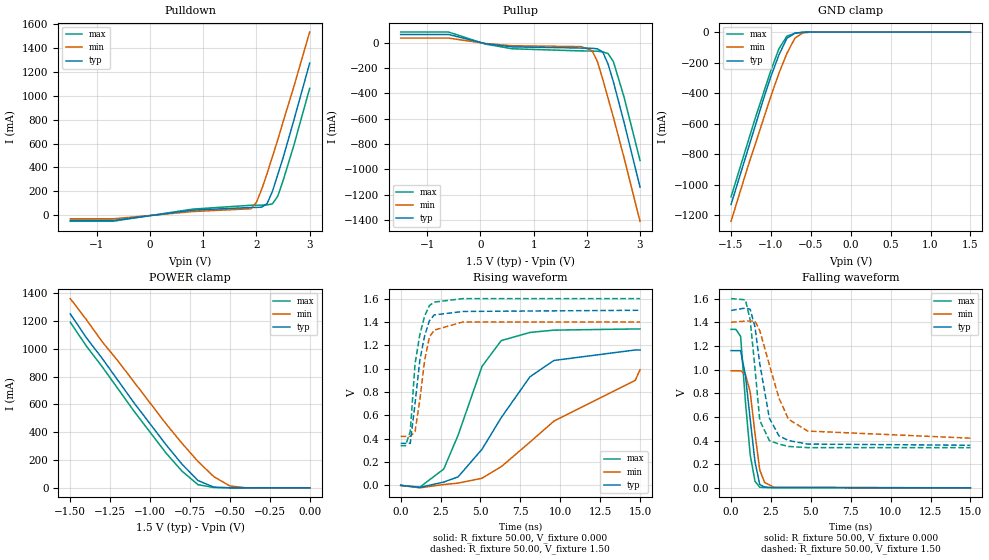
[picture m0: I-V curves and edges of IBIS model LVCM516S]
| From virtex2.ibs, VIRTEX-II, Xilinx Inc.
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|   Model LVCM516S
[Model]   LVCM516S
Model_type   I/O
Polarity   Non-Inverting
Enable   Active-Low
Vinh = 1.05V
Vinl = 0.3V
Vmeas =   0.75V
Cref =  35.00pF
Rref =   1.00M
Vref =  0.000V
C_comp   7.00pF   6.00pF   8.00pF
[Temperature Range]   25.00   100.00   0.000
[Voltage Range]   1.50V   1.40V   1.60V
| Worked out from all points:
|   slope of the pulldown table from 0 to 0.225 V, typ, clamps not added: 15.1 ohm
|   slope of the pullup table from 0 to 0.225 V, typ, clamps not added: 13.2 ohm
|   GND clamp passes 1 mA (typ) near -0.57 V on its own axis
|   POWER clamp passes 1 mA (typ) near -0.52 V on its own axis
|   rising waveform, R_fixture 50.00, V_fixture 0.000: 20-80 % time 3.38ns typ, 5.65ns min, 2.15ns max; typ from 0 V to 1.16 V
|   rising waveform, R_fixture 50.00, V_fixture 1.50: 20-80 % time 687ps typ, 628ps min, 640ps max; typ from 0.36 V to 1.5 V
|   falling waveform, R_fixture 50.00, V_fixture 0.000: 20-80 % time 572ps typ, 538ps min, 503ps max; typ from 1.16 V to 0 V
|   falling waveform, R_fixture 50.00, V_fixture 1.50: 20-80 % time 821ps typ, 1.35ns min, 532ps max; typ from 1.5 V to 0.36 V
[Pulldown]
| voltage   I(typ)   I(min)   I(max)
-1.5V     -42.67mA   -28.72mA   -48.9mA
-700mV    -42.67mA   -28.72mA   -48.9mA
800mV     43.93mA    32.22mA    52.52mA
1.9V      66.27mA    55.78mA    84.76mA
2V        66.76mA    110mA      85.3mA
2.1V      69.07mA    220mA      85.82mA
2.2V      98.85mA    350mA      87.26mA
2.3V      200mA      490mA      96.52mA
2.4V      340mA      630mA      160mA
2.5V      480mA      780mA      290mA
2.7V      790mA      1.07A      580mA
3V        1.27A      1.53A      1.06A
[Pullup]
| voltage   I(typ)   I(min)   I(max)
-1.5V     65.27mA    36.47mA    84.3mA
-600mV    65.27mA    36.47mA    84.3mA
100mV     -8.32mA    -6.21mA    -11.27mA
600mV     -32.72mA   -23.85mA   -47.93mA
1.9V      -42.19mA   -30.93mA   -64.82mA
2.1V      -43.7mA    -63.33mA   -65.77mA
2.2V      -48.81mA   -150mA     -66.99mA
2.3V      -73.48mA   -290mA     -72.22mA
2.4V      -170mA     -440mA     -85.88mA
2.5V      -310mA     -590mA     -150mA
2.7V      -630mA     -910mA     -430mA
3V        -1.14A     -1.41A     -930mA
[GND_clamp]
| voltage   I(typ)   I(min)   I(max)
-1.5V     -1.13A     -1.24A     -1.08A
-1.3V     -790mA     -900mA     -740mA
-1.2V     -620mA     -740mA     -570mA
-1.1V     -450mA     -580mA     -410mA
-1V       -290mA     -420mA     -250mA
-900mV    -150mA     -270mA     -110mA
-800mV    -40.96mA   -140mA     -27.15mA
-700mV    -7.52mA    -40.16mA   -8.06mA
-600mV    -1.38mA    -5.56mA    -1.57mA
-500mV    -120uA     -650uA     -120uA
1.5V      27.96pA    98.69nA    16.96pA
[POWER_clamp]
| voltage   I(typ)   I(min)   I(max)
-1.5V     1.25A      1.36A      1.19A
-1.4V     1.08A      1.21A      1.02A
-1.3V     930mA      1.05A      870mA
-1.2V     770mA      910mA      710mA
-1.1V     610mA      760mA      550mA
-900mV    310mA      460mA      250mA
-800mV    170mA      320mA      120mA
-700mV    52.75mA    190mA      22.81mA
-600mV    4.57mA     79.88mA    2.44mA
-500mV    270uA      13.45mA    250uA
-400mV    16.38uA    820uA      14.46uA
0V        27.96pA    880pA      24.27pA
[Ramp]
| variable   typ   min   max
dV/dt_r   0.69/3.38n   0.54/4.84n   0.80/2.15n
dV/dt_f   0.68/0.85n   0.59/1.33n   0.76/0.60n
R_load = 50.00
[Rising Waveform]
R_fixture = 50.00
V_fixture = 0.000
| time   V(typ)   V(min)   V(max)
0s        0V         0V         0V
1.2ns     -17.41mV   -21.13mV   -15.31mV
2.7ns     28.3mV     7.31mV     140mV
3.6ns     72.77mV    19.16mV    430mV
5.1ns     310mV      61.46mV    1.02V
6.3ns     580mV      160mV      1.24V
8.1ns     930mV      370mV      1.31V
9.6ns     1.07V      550mV      1.33V
14.7ns    1.16V      900mV      1.34V
15ns      1.16V      990mV      1.34V
[Rising Waveform]
R_fixture = 50.00
V_fixture = 1.50
V_fixture_min = 1.40
V_fixture_max = 1.60
| time   V(typ)   V(min)   V(max)
0s        360mV      420mV      340mV
300ps     360mV      420mV      340mV
600ps     360mV      420mV      460mV
900ps     700mV      460mV      1.04V
1.2ns     1.07V      730mV      1.29V
1.5ns     1.28V      1.07V      1.45V
1.8ns     1.41V      1.27V      1.54V
2.1ns     1.46V      1.33V      1.57V
3.9ns     1.49V      1.4V       1.6V
15ns      1.5V       1.4V       1.6V
[Falling Waveform]
R_fixture = 50.00
V_fixture = 0.000
| time   V(typ)   V(min)   V(max)
0s        1.16V      990mV      1.34V
300ps     1.16V      990mV      1.34V
600ps     1.16V      990mV      1.28V
900ps     950mV      960mV      730mV
1.2ns     580mV      810mV      280mV
1.5ns     220mV      460mV      55.68mV
1.8ns     27.91mV    150mV      4.53mV
2.1ns     6.02mV     45.65mV    2.04mV
2.7ns     1.75mV     4.96mV     1.1mV
15ns      -31.3uV    -20.92uV   19.93uV
[Falling Waveform]
R_fixture = 50.00
V_fixture = 1.50
V_fixture_min = 1.40
V_fixture_max = 1.60
| time   V(typ)   V(min)   V(max)
0s        1.5V       1.4V       1.6V
900ps     1.52V      1.41V      1.59V
1.2ns     1.51V      1.41V      1.42V
1.5ns     1.36V      1.41V      1.01V
1.8ns     1.05V      1.33V      570mV
2.4ns     590mV      1.04V      400mV
3ns       440mV      760mV      370mV
3.6ns     400mV      580mV      350mV
4.8ns     370mV      480mV      340mV
15ns      360mV      420mV      340mV
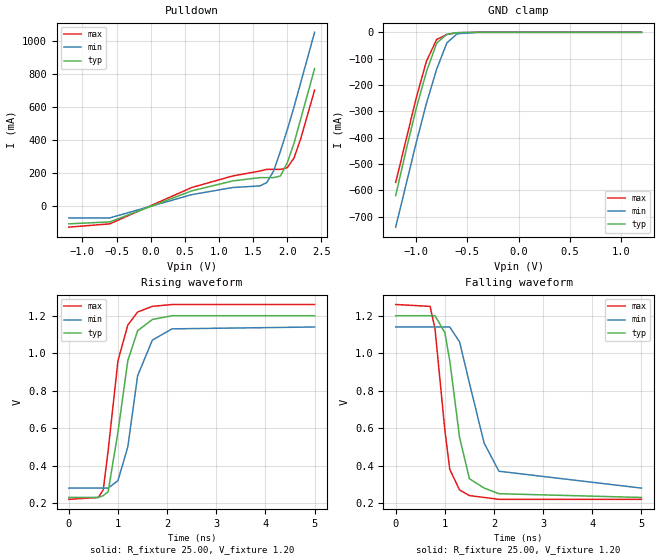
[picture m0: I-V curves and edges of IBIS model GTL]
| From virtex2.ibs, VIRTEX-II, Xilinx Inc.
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|   Model GTL
[Model]   GTL
Model_type   I/O_open_drain
Polarity   Non-Inverting
Enable   Active-Low
Vinh = 0.85V
Vinl = 0.75V
Vmeas =   0.80V
Cref =  0.000F
Rref =  25.00
Vref =   1.20V
C_comp   7.00pF   6.00pF   8.00pF
[Temperature Range]   25.00   100.00   0.000
[Voltage Range]   1.20V   1.14V   1.26V
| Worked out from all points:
|   slope of the pulldown table from 0 to 0.18 V, typ, clamps not added: 5.93 ohm
|   GND clamp passes 1 mA (typ) near -0.57 V on its own axis
|   rising waveform, R_fixture 25.00, V_fixture 1.20: 20-80 % time 314ps typ, 328ps min, 301ps max; typ from 0.23 V to 1.2 V
|   falling waveform, R_fixture 25.00, V_fixture 1.20: 20-80 % time 309ps typ, 514ps min, 245ps max; typ from 1.2 V to 0.23 V
[Pulldown]
| voltage   I(typ)   I(min)   I(max)
-1.2V     -110mA     -73.97mA   -130mA
-600mV    -98.18mA   -73.97mA   -110mA
600mV     89.64mA    66.8mA     110mA
1.2V      150mA      110mA      180mA
1.6V      170mA      120mA      210mA
1.7V      170mA      140mA      220mA
1.8V      170mA      210mA      220mA
1.9V      180mA      330mA      220mA
2V        260mA      460mA      230mA
2.1V      380mA      600mA      290mA
2.2V      530mA      750mA      410mA
2.4V      830mA      1.05A      700mA
[GND_clamp]
| voltage   I(typ)   I(min)   I(max)
-1.2V     -620mA     -740mA     -570mA
-1.1V     -450mA     -580mA     -410mA
-1V       -290mA     -420mA     -250mA
-900mV    -150mA     -270mA     -110mA
-800mV    -40.94mA   -140mA     -27.12mA
-700mV    -7.51mA    -40.15mA   -8.04mA
-600mV    -1.38mA    -5.56mA    -1.56mA
-400mV    -6.56uA    -62.75uA   -4.51uA
1.2V      21.68pA    25.98nA    12.71pA
[Ramp]
| variable   typ   min   max
dV/dt_r   0.58/0.30n   0.52/0.34n   0.63/0.29n
dV/dt_f   0.58/0.31n   0.52/0.49n   0.63/0.23n
R_load = 25.00
[Rising Waveform]
R_fixture = 25.00
V_fixture = 1.20
V_fixture_min = 1.14
V_fixture_max = 1.26
| time   V(typ)   V(min)   V(max)
0s        230mV      280mV      220mV
600ps     230mV      280mV      230mV
700ps     240mV      280mV      270mV
800ps     260mV      280mV      480mV
1ns       580mV      320mV      960mV
1.2ns     960mV      500mV      1.15V
1.4ns     1.12V      880mV      1.22V
1.7ns     1.18V      1.07V      1.25V
2.1ns     1.2V       1.13V      1.26V
5ns       1.2V       1.14V      1.26V
[Falling Waveform]
R_fixture = 25.00
V_fixture = 1.20
V_fixture_min = 1.14
V_fixture_max = 1.26
| time   V(typ)   V(min)   V(max)
0s        1.2V       1.14V      1.26V
700ps     1.2V       1.14V      1.25V
800ps     1.2V       1.14V      1.13V
1ns       1.11V      1.14V      590mV
1.1ns     960mV      1.14V      380mV
1.3ns     550mV      1.06V      270mV
1.5ns     330mV      840mV      240mV
1.8ns     280mV      520mV      230mV
2.1ns     250mV      370mV      220mV
5ns       230mV      280mV      220mV
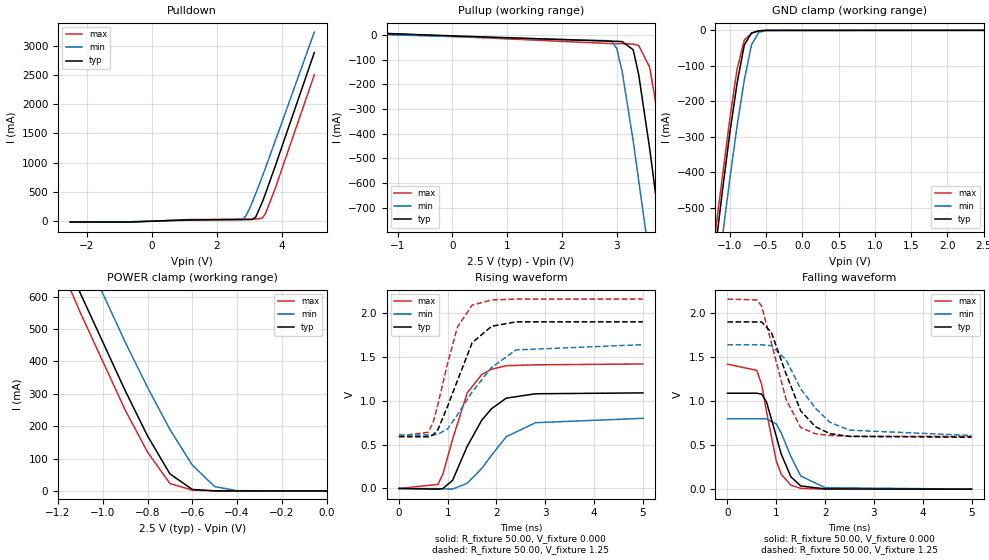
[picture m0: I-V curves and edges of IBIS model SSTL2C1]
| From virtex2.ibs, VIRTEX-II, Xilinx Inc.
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|   Model SSTL2C1
[Model]   SSTL2C1
Model_type   I/O
Polarity   Non-Inverting
Enable   Active-Low
Vinh = 1.43V
Vinl = 1.07V
Vmeas =   1.25V
Cref =  30.00pF
Rref =  50.00
Vref =   1.25V
C_comp   7.00pF   6.00pF   8.00pF
[Temperature Range]   25.00   100.00   0.000
[Voltage Range]   2.50V   2.30V   2.70V
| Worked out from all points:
|   slope of the pulldown table from 0 to 0.375 V, typ, clamps not added: 41.4 ohm
|   slope of the pullup table from 0 to 0.375 V, typ, clamps not added: 42.4 ohm
|   GND clamp passes 1 mA (typ) near -0.57 V on its own axis
|   POWER clamp passes 1 mA (typ) near -0.52 V on its own axis
|   rising waveform, R_fixture 50.00, V_fixture 0.000: 20-80 % time 615ps typ, 767ps min, 481ps max; typ from 0 V to 1.09 V
|   rising waveform, R_fixture 50.00, V_fixture 1.25: 20-80 % time 543ps typ, 817ps min, 430ps max; typ from 0.59 V to 1.9 V
|   falling waveform, R_fixture 50.00, V_fixture 0.000: 20-80 % time 360ps typ, 387ps min, 307ps max; typ from 1.09 V to 0 V
|   falling waveform, R_fixture 50.00, V_fixture 1.25: 20-80 % time 562ps typ, 752ps min, 455ps max; typ from 1.9 V to 0.59 V
[Pulldown]
| voltage   I(typ)   I(min)   I(max)
-2.5V     -16.21mA   -10.87mA   -18.67mA
-700mV    -16.21mA   -10.87mA   -18.67mA
1.1V      20.58mA    14.86mA    25.12mA
2.8V      25.66mA    29.83mA    32.86mA
2.9V      25.71mA    91.52mA    32.91mA
3V        25.95mA    200mA      32.95mA
3.1V      29.18mA    330mA      33mA
3.2V      69.77mA    470mA      33.21mA
3.4V      320mA      760mA      49.91mA
3.5V      470mA      910mA      130mA
3.8V      940mA      1.37A      560mA
5V        2.88A      3.23A      2.5A
[Pullup]
| voltage   I(typ)   I(min)   I(max)
-2.5V     16.1mA     9.12mA     20.2mA
2.9V      -24.93mA   -22.85mA   -34.49mA
3V        -25.12mA   -53.66mA   -34.63mA
3.1V      -26.25mA   -150mA     -34.77mA
3.3V      -59.69mA   -430mA     -36.19mA
3.4V      -160mA     -590mA     -41.94mA
3.6V      -460mA     -910mA     -130mA
3.7V      -630mA     -1.07A     -260mA
3.8V      -790mA     -1.24A     -420mA
4V        -1.13A     -1.58A     -750mA
4.2V      -1.48A     -1.92A     -1.09A
5V        -2.89A     -3.29A     -2.49A
[GND_clamp]
| voltage   I(typ)   I(min)   I(max)
-2.5V     -2.88A     -2.94A     -2.84A
-1.2V     -620mA     -740mA     -570mA
-1.1V     -450mA     -580mA     -410mA
-1V       -290mA     -420mA     -250mA
-900mV    -150mA     -270mA     -110mA
-800mV    -41mA      -140mA     -27.22mA
-700mV    -7.57mA    -40.19mA   -8.13mA
-600mV    -1.4mA     -5.59mA    -1.6mA
-500mV    -130uA     -660uA     -120uA
2.5V      49.34pA    2.1uA      32.91pA
[POWER_clamp]
| voltage   I(typ)   I(min)   I(max)
-2.5V     2.87A      2.91A      2.82A
-1.3V     930mA      1.05A      870mA
-1.2V     770mA      910mA      710mA
-1.1V     610mA      760mA      550mA
-900mV    310mA      460mA      250mA
-800mV    170mA      320mA      120mA
-700mV    52.75mA    190mA      22.81mA
-600mV    4.57mA     79.88mA    2.44mA
-500mV    270uA      13.45mA    250uA
-400mV    16.38uA    820uA      14.46uA
0V        49.34pA    1.47nA     44.79pA
[Ramp]
| variable   typ   min   max
dV/dt_r   0.65/0.61n   0.48/0.77n   0.85/0.50n
dV/dt_f   0.69/0.83n   0.50/1.08n   0.84/0.66n
R_load = 50.00
[Rising Waveform]
R_fixture = 50.00
V_fixture = 0.000
| time   V(typ)   V(min)   V(max)
0s        0V         0V         0V
800ps     -7.84mV    -2.13mV    46.29mV
900ps     -1.11mV    -4.45mV    160mV
1.1ns     92.57mV    -7.09mV    560mV
1.4ns     480mV      59.11mV    1.09V
1.7ns     780mV      230mV      1.3V
1.9ns     910mV      380mV      1.36V
2.2ns     1.03V      590mV      1.4V
2.8ns     1.08V      750mV      1.41V
5ns       1.09V      800mV      1.42V
[Rising Waveform]
R_fixture = 50.00
V_fixture = 1.25
V_fixture_min = 1.11
V_fixture_max = 1.39
| time   V(typ)   V(min)   V(max)
0s        590mV      610mV      600mV
600ps     590mV      610mV      640mV
700ps     610mV      610mV      750mV
800ps     670mV      620mV      960mV
1ns       940mV      680mV      1.43V
1.2ns     1.23V      840mV      1.84V
1.5ns     1.66V      1.1V       2.09V
1.9ns     1.85V      1.38V      2.15V
2.4ns     1.9V       1.58V      2.16V
5ns       1.9V       1.64V      2.16V
[Falling Waveform]
R_fixture = 50.00
V_fixture = 0.000
| time   V(typ)   V(min)   V(max)
0s        1.09V      800mV      1.42V
600ps     1.09V      800mV      1.35V
700ps     1.08V      800mV      1.19V
800ps     990mV      800mV      880mV
1ns       600mV      740mV      320mV
1.1ns     400mV      640mV      170mV
1.3ns     140mV      370mV      44.63mV
1.5ns     37.07mV    150mV      9.39mV
2ns       2.63mV     16.77mV    710uV
5ns       -5.43uV    7.02uV     -5.64uV
[Falling Waveform]
R_fixture = 50.00
V_fixture = 1.25
V_fixture_min = 1.11
V_fixture_max = 1.39
| time   V(typ)   V(min)   V(max)
0s        1.9V       1.64V      2.16V
600ps     1.9V       1.64V      2.15V
700ps     1.9V       1.64V      2.08V
900ps     1.78V      1.63V      1.66V
1.2ns     1.31V      1.47V      1.02V
1.5ns     890mV      1.14V      700mV
1.8ns     710mV      920mV      630mV
2.1ns     630mV      760mV      610mV
2.5ns     600mV      670mV      600mV
5ns       590mV      610mV      600mV
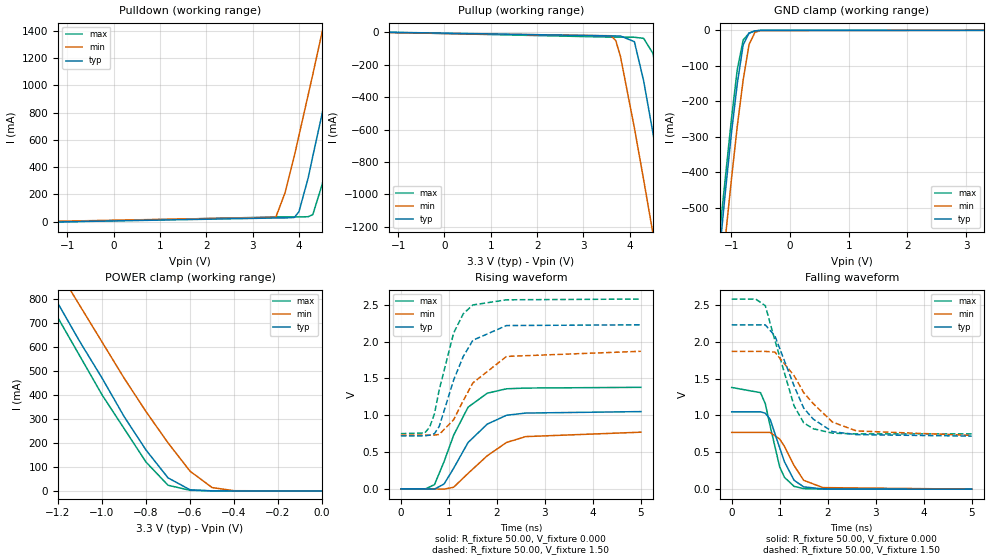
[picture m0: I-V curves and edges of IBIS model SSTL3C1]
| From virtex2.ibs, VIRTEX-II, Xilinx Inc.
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|   Model SSTL3C1
[Model]   SSTL3C1
Model_type   I/O
Polarity   Non-Inverting
Enable   Active-Low
Vinh = 1.7V
Vinl = 1.3V
Vmeas =   1.50V
Cref =  30.00pF
Rref =  50.00
Vref =   1.50V
C_comp   7.00pF   6.00pF   8.00pF
[Temperature Range]   25.00   100.00   0.000
[Voltage Range]   3.30V   3.00V   3.60V
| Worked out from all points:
|   slope of the pulldown table from 0 to 0.495 V, typ, clamps not added: 43.1 ohm
|   slope of the pullup table from 0 to 0.495 V, typ, clamps not added: 63.8 ohm
|   GND clamp passes 1 mA (typ) near -0.57 V on its own axis
|   POWER clamp passes 1 mA (typ) near -0.52 V on its own axis
|   rising waveform, R_fixture 50.00, V_fixture 0.000: 20-80 % time 678ps typ, 827ps min, 547ps max; typ from 0 V to 1.05 V
|   rising waveform, R_fixture 50.00, V_fixture 1.50: 20-80 % time 505ps typ, 690ps min, 434ps max; typ from 0.72 V to 2.23 V
|   falling waveform, R_fixture 50.00, V_fixture 0.000: 20-80 % time 345ps typ, 393ps min, 298ps max; typ from 1.05 V to 0 V
|   falling waveform, R_fixture 50.00, V_fixture 1.50: 20-80 % time 621ps typ, 813ps min, 484ps max; typ from 2.23 V to 0.72 V
[Pulldown]
| voltage   I(typ)   I(min)   I(max)
-3.3V     -16.22mA   -10.87mA   -18.67mA
3.5V      25.91mA    30.57mA    33.14mA
3.7V      25.98mA    210mA      33.2mA
3.9V      29.56mA    480mA      33.26mA
4V        71.32mA    630mA      33.3mA
4.2V      320mA      930mA      35.28mA
4.3V      480mA      1.08A      50.75mA
4.5V      790mA      1.39A      270mA
4.9V      1.44A      2.01A      890mA
5.1V      1.77A      2.33A      1.22A
5.3V      2.1A       2.64A      1.54A
6.6V      4.26A      4.71A      3.71A
[Pullup]
| voltage   I(typ)   I(min)   I(max)
-3.3V     10.13mA    5.86mA     12.39mA
3.6V      -22.6mA    -21.51mA   -30.15mA
3.7V      -22.67mA   -52.6mA    -30.25mA
3.8V      -22.83mA   -150mA     -30.34mA
4.1V      -57.92mA   -590mA     -30.68mA
4.3V      -300mA     -910mA     -37.77mA
4.5V      -620mA     -1.24A     -130mA
4.7V      -960mA     -1.58A     -420mA
4.9V      -1.31A     -1.92A     -750mA
5.1V      -1.66A     -2.26A     -1.09A
5.3V      -2.01A     -2.6A      -1.44A
6.6V      -4.31A     -4.84A     -3.73A
[GND_clamp]
| voltage   I(typ)   I(min)   I(max)
-3.3V     -4.3A      -4.31A     -4.26A
-1.2V     -620mA     -740mA     -570mA
-1.1V     -450mA     -580mA     -410mA
-1V       -290mA     -420mA     -250mA
-900mV    -150mA     -270mA     -110mA
-800mV    -41.03mA   -140mA     -27.28mA
-700mV    -7.6mA     -40.21mA   -8.18mA
-600mV    -1.42mA    -5.61mA    -1.62mA
-500mV    -130uA     -670uA     -130uA
3.3V      67.85pA    43.48uA    45.6pA
[POWER_clamp]
| voltage   I(typ)   I(min)   I(max)
-3.3V     4.25A      4.22A      4.2A
-1.3V     940mA      1.07A      880mA
-1.2V     780mA      920mA      720mA
-1.1V     620mA      770mA      560mA
-1V       470mA      620mA      400mA
-900mV    310mA      470mA      260mA
-800mV    170mA      330mA      120mA
-700mV    54.34mA    200mA      23.62mA
-600mV    4.76mA     82.21mA    2.52mA
-500mV    280uA      14.02mA    260uA
-400mV    16.9uA     860uA      14.85uA
0V        67.85pA    2.04nA     61.89pA
[Ramp]
| variable   typ   min   max
dV/dt_r   0.63/0.67n   0.46/0.85n   0.83/0.57n
dV/dt_f   0.75/0.93n   0.54/1.14n   0.96/0.80n
R_load = 50.00
[Rising Waveform]
R_fixture = 50.00
V_fixture = 0.000
| time   V(typ)   V(min)   V(max)
0s        0V         0V         0V
500ps     -490uV     12.6uV     -4.36mV
700ps     -4.6mV     -630uV     56.44mV
900ps     65.75mV    -4.73mV    370mV
1.1ns     280mV      21.86mV    730mV
1.4ns     630mV      210mV      1.11V
1.8ns     880mV      450mV      1.3V
2.2ns     1V         630mV      1.36V
2.6ns     1.03V      710mV      1.37V
5ns       1.05V      770mV      1.38V
[Rising Waveform]
R_fixture = 50.00
V_fixture = 1.50
V_fixture_min = 1.30
V_fixture_max = 1.70
| time   V(typ)   V(min)   V(max)
0s        720mV      730mV      750mV
500ps     720mV      730mV      760mV
600ps     730mV      730mV      840mV
700ps     750mV      730mV      1.02V
800ps     850mV      740mV      1.35V
1.1ns     1.48V      940mV      2.12V
1.3ns     1.8V       1.2V       2.38V
1.5ns     2.02V      1.44V      2.5V
2.2ns     2.22V      1.8V       2.57V
5ns       2.23V      1.87V      2.58V
[Falling Waveform]
R_fixture = 50.00
V_fixture = 0.000
| time   V(typ)   V(min)   V(max)
0s        1.05V      770mV      1.38V
600ps     1.05V      770mV      1.31V
700ps     1.03V      770mV      1.16V
800ps     950mV      770mV      860mV
1ns       560mV      680mV      300mV
1.1ns     370mV      580mV      160mV
1.3ns     120mV      320mV      37.75mV
1.5ns     31.3mV     120mV      7.36mV
1.9ns     3.45mV     21.05mV    930uV
5ns       -5.16uV    6.78uV     -4.75uV
[Falling Waveform]
R_fixture = 50.00
V_fixture = 1.50
V_fixture_min = 1.30
V_fixture_max = 1.70
| time   V(typ)   V(min)   V(max)
0s        2.23V      1.87V      2.58V
500ps     2.23V      1.87V      2.58V
700ps     2.23V      1.87V      2.49V
900ps     2.08V      1.86V      2.02V
1.3ns     1.4V       1.54V      1.13V
1.5ns     1.1V       1.31V      900mV
1.7ns     950mV      1.16V      820mV
2.1ns     780mV      910mV      760mV
2.6ns     740mV      790mV      750mV
5ns       720mV      730mV      750mV
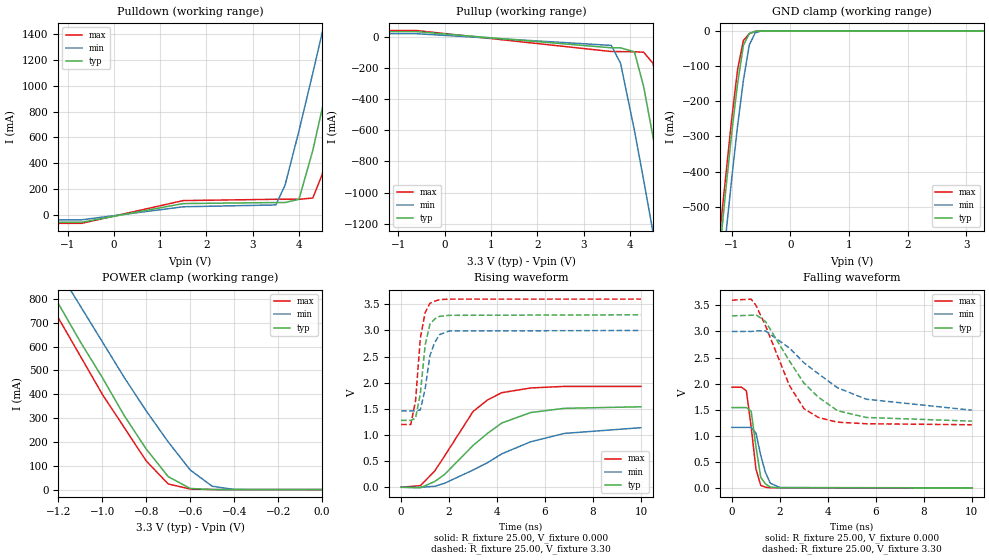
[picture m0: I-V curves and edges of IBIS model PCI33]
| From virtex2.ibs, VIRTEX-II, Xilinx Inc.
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|   Model PCI33
[Model]   PCI33
Model_type   I/O
Polarity   Non-Inverting
Enable   Active-Low
Vinh = 1.65V
Vinl = 0.99V
| Vmeas depends on rising or falling edge, select one of the following:
| For rising edge:
|Vmeas =   0.940V
| For falling edge:
|Vmeas =   2.03V
Cref =  10.00pF
Rref =  25.00
| Vref depends on rising or falling edge, select one of the following:
| For rising edge:
|Vref =   0.00V
| For falling edge:
|Vref =   3.30V
C_comp   7.00pF   6.00pF   8.00pF
[Temperature Range]   25.00   100.00   0.000
[Voltage Range]   3.30V   3.00V   3.60V
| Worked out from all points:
|   slope of the pulldown table from 0 to 0.495 V, typ, clamps not added: 12 ohm
|   slope of the pullup table from 0 to 0.495 V, typ, clamps not added: 20.4 ohm
|   GND clamp passes 1 mA (typ) near -0.57 V on its own axis
|   POWER clamp passes 1 mA (typ) near -0.52 V on its own axis
|   rising waveform, R_fixture 25.00, V_fixture 0.000: 20-80 % time 2.24ns typ, 2.99ns min, 1.75ns max; typ from 0 V to 1.54 V
|   rising waveform, R_fixture 25.00, V_fixture 3.30: 20-80 % time 333ps typ, 394ps min, 305ps max; typ from 1.28 V to 3.3 V
|   falling waveform, R_fixture 25.00, V_fixture 0.000: 20-80 % time 293ps typ, 401ps min, 302ps max; typ from 1.54 V to 0 V
|   falling waveform, R_fixture 25.00, V_fixture 3.30: 20-80 % time 1.95ns typ, 2.78ns min, 1.34ns max; typ from 3.3 V to 1.28 V
[Pulldown]
| voltage   I(typ)   I(min)   I(max)
-3.3V     -58.45mA   -39.38mA   -66.87mA
-700mV    -58.45mA   -39.38mA   -66.87mA
1.5V      86.81mA    61.85mA    110mA
3.5V      94.77mA    76.19mA    120mA
3.7V      94.99mA    230mA      120mA
4V        120mA      650mA      120mA
4.3V      500mA      1.1A       130mA
4.5V      820mA      1.41A      310mA
4.9V      1.46A      2.03A      920mA
5.1V      1.79A      2.35A      1.25A
5.3V      2.12A      2.66A      1.58A
6.6V      4.29A      4.72A      3.74A
[Pullup]
| voltage   I(typ)   I(min)   I(max)
-3.3V     31.93mA    18.66mA    38.69mA
-600mV    31.93mA    18.66mA    38.69mA
3.6V      -71.52mA   -56.26mA   -95.39mA
3.8V      -71.99mA   -170mA     -96mA
4.1V      -97.11mA   -600mA     -96.86mA
4.3V      -320mA     -920mA     -100mA
4.5V      -640mA     -1.25A     -170mA
4.7V      -980mA     -1.59A     -440mA
4.9V      -1.32A     -1.93A     -770mA
5.1V      -1.67A     -2.27A     -1.11A
5.3V      -2.02A     -2.61A     -1.46A
6.6V      -4.32A     -4.85A     -3.75A
[GND_clamp]
| voltage   I(typ)   I(min)   I(max)
-3.3V     -4.3A      -4.31A     -4.26A
-1.2V     -620mA     -740mA     -570mA
-1.1V     -450mA     -580mA     -410mA
-1V       -290mA     -420mA     -250mA
-900mV    -150mA     -270mA     -110mA
-800mV    -41.03mA   -140mA     -27.28mA
-700mV    -7.6mA     -40.21mA   -8.18mA
-600mV    -1.42mA    -5.61mA    -1.62mA
-500mV    -130uA     -670uA     -130uA
3.3V      67.85pA    43.48uA    45.6pA
[POWER_clamp]
| voltage   I(typ)   I(min)   I(max)
-3.3V     4.25A      4.22A      4.2A
-1.3V     940mA      1.07A      880mA
-1.2V     780mA      920mA      720mA
-1.1V     620mA      770mA      560mA
-1V       470mA      620mA      400mA
-900mV    310mA      470mA      260mA
-800mV    170mA      330mA      120mA
-700mV    54.34mA    200mA      23.62mA
-600mV    4.76mA     82.21mA    2.52mA
-500mV    280uA      14.02mA    260uA
-400mV    16.9uA     860uA      14.85uA
0V        67.85pA    2.04nA     61.89pA
[Ramp]
| variable   typ   min   max
dV/dt_r   0.92/2.28n   0.68/3.08n   1.16/1.75n
dV/dt_f   1.21/1.94n   0.91/2.77n   1.44/1.36n
R_load = 25.00
[Rising Waveform]
R_fixture = 25.00
V_fixture = 0.000
| time   V(typ)   V(min)   V(max)
0s        0V         0V         0V
800ps     -11.6mV    -2.63mV    30.71mV
1.4ns     110mV      18.96mV    310mV
1.8ns     240mV      73.63mV    590mV
3ns       800mV      330mV      1.45V
3.6ns     1.03V      470mV      1.67V
4.2ns     1.23V      640mV      1.81V
5.4ns     1.43V      870mV      1.9V
6.8ns     1.51V      1.03V      1.93V
10ns      1.54V      1.14V      1.93V
[Rising Waveform]
R_fixture = 25.00
V_fixture = 3.30
V_fixture_min = 3.00
V_fixture_max = 3.60
| time   V(typ)   V(min)   V(max)
0s        1.28V      1.46V      1.2V
400ps     1.28V      1.46V      1.2V
600ps     1.32V      1.46V      1.65V
800ps     1.79V      1.48V      2.85V
1ns       2.72V      1.88V      3.34V
1.2ns     3.12V      2.52V      3.52V
1.4ns     3.22V      2.77V      3.56V
1.6ns     3.27V      2.92V      3.59V
2ns       3.29V      2.99V      3.6V
10ns      3.3V       3V         3.6V
[Falling Waveform]
R_fixture = 25.00
V_fixture = 0.000
| time   V(typ)   V(min)   V(max)
0s        1.54V      1.16V      1.93V
400ps     1.54V      1.16V      1.93V
600ps     1.54V      1.16V      1.86V
800ps     1.47V      1.16V      1.17V
1ns       790mV      1.05V      360mV
1.2ns     200mV      620mV      46.91mV
1.4ns     74.86mV    290mV      11.2mV
1.6ns     13.41mV    88.44mV    2.13mV
2ns       2.31mV     6.36mV     1.8mV
10ns      11.85uV    43.69uV    4.82uV
[Falling Waveform]
R_fixture = 25.00
V_fixture = 3.30
V_fixture_min = 3.00
V_fixture_max = 3.60
| time   V(typ)   V(min)   V(max)
0s        3.3V       3V         3.6V
800ps     3.31V      3V         3.62V
1ns       3.32V      3.01V      3.5V
1.4ns     3.19V      3.01V      3.11V
2.4ns     2.43V      2.68V      1.96V
3ns       2.01V      2.4V       1.52V
3.6ns     1.74V      2.19V      1.35V
4.4ns     1.48V      1.92V      1.26V
5.6ns     1.35V      1.7V       1.23V
10ns      1.28V      1.49V      1.21V
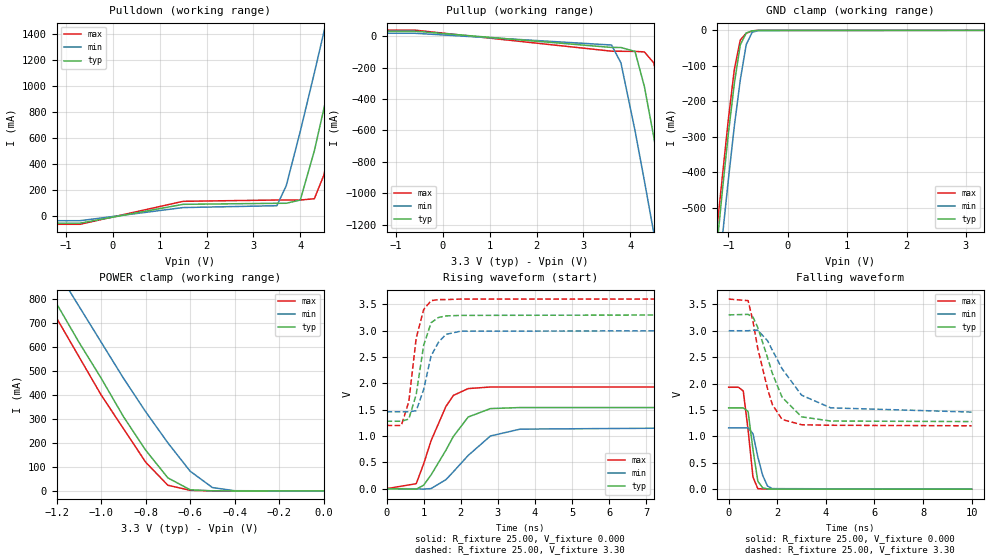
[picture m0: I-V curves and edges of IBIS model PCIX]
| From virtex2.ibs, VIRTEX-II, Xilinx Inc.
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|   Model PCIX
[Model]   PCIX
Model_type   I/O
Polarity   Non-Inverting
Enable   Active-Low
Vinh = 1.65V
Vinl = 0.99V
| Vmeas depends on rising or falling edge, select one of the following:
| For rising edge:
|Vmeas =   0.940V
| For falling edge:
|Vmeas =   2.03V
Vmeas =   0.94V
Cref =  10.00pF
Rref =  25.00
| Vref depends on rising or falling edge, select one of the following:
| For rising edge:
|Vref =   0.00V
| For falling edge:
|Vref =   3.30V
C_comp   7.00pF   6.00pF   8.00pF
[Temperature Range]   25.00   100.00   0.000
[Voltage Range]   3.30V   3.00V   3.60V
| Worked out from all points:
|   slope of the pulldown table from 0 to 0.495 V, typ, clamps not added: 12 ohm
|   slope of the pullup table from 0 to 0.495 V, typ, clamps not added: 20.4 ohm
|   GND clamp passes 1 mA (typ) near -0.57 V on its own axis
|   POWER clamp passes 1 mA (typ) near -0.52 V on its own axis
|   rising waveform, R_fixture 25.00, V_fixture 0.000: 20-80 % time 781ps typ, 986ps min, 635ps max; typ from 0 V to 1.54 V
|   rising waveform, R_fixture 25.00, V_fixture 3.30: 20-80 % time 327ps typ, 388ps min, 291ps max; typ from 1.28 V to 3.3 V
|   falling waveform, R_fixture 25.00, V_fixture 0.000: 20-80 % time 281ps typ, 372ps min, 280ps max; typ from 1.54 V to 0 V
|   falling waveform, R_fixture 25.00, V_fixture 3.30: 20-80 % time 938ps typ, 1.32ns min, 724ps max; typ from 3.3 V to 1.28 V
[Pulldown]
| voltage   I(typ)   I(min)   I(max)
-3.3V     -58.45mA   -39.38mA   -66.87mA
-700mV    -58.45mA   -39.38mA   -66.87mA
1.5V      86.81mA    61.86mA    110mA
3.5V      94.77mA    76.19mA    120mA
3.7V      94.99mA    230mA      120mA
4V        120mA      650mA      120mA
4.3V      500mA      1.1A       130mA
4.5V      820mA      1.41A      310mA
4.9V      1.46A      2.03A      920mA
5.1V      1.79A      2.35A      1.25A
5.3V      2.12A      2.66A      1.58A
6.6V      4.29A      4.72A      3.74A
[Pullup]
| voltage   I(typ)   I(min)   I(max)
-3.3V     31.93mA    18.66mA    38.69mA
-600mV    31.93mA    18.66mA    38.69mA
3.6V      -71.52mA   -56.26mA   -95.39mA
3.8V      -71.99mA   -170mA     -96mA
4.1V      -97.11mA   -600mA     -96.86mA
4.3V      -320mA     -920mA     -100mA
4.5V      -640mA     -1.25A     -170mA
4.7V      -980mA     -1.59A     -440mA
4.9V      -1.32A     -1.93A     -770mA
5.1V      -1.67A     -2.27A     -1.11A
5.3V      -2.02A     -2.61A     -1.46A
6.6V      -4.32A     -4.85A     -3.75A
[GND_clamp]
| voltage   I(typ)   I(min)   I(max)
-3.3V     -4.3A      -4.31A     -4.26A
-1.2V     -620mA     -740mA     -570mA
-1.1V     -450mA     -580mA     -410mA
-1V       -290mA     -420mA     -250mA
-900mV    -150mA     -270mA     -110mA
-800mV    -41.03mA   -140mA     -27.28mA
-700mV    -7.6mA     -40.21mA   -8.18mA
-600mV    -1.42mA    -5.61mA    -1.62mA
-500mV    -130uA     -670uA     -130uA
3.3V      67.85pA    43.48uA    45.6pA
[POWER_clamp]
| voltage   I(typ)   I(min)   I(max)
-3.3V     4.25A      4.22A      4.2A
-1.3V     940mA      1.07A      880mA
-1.2V     780mA      920mA      720mA
-1.1V     620mA      770mA      560mA
-1V       470mA      620mA      400mA
-900mV    310mA      470mA      260mA
-800mV    170mA      330mA      120mA
-700mV    54.34mA    200mA      23.62mA
-600mV    4.76mA     82.21mA    2.52mA
-500mV    280uA      14.02mA    260uA
-400mV    16.9uA     860uA      14.85uA
0V        67.85pA    2.04nA     61.89pA
[Ramp]
| variable   typ   min   max
dV/dt_r   0.92/0.74n   0.70/0.98n   1.16/0.58n
dV/dt_f   1.21/0.92n   0.92/1.34n   1.44/0.66n
R_load = 25.00
[Rising Waveform]
R_fixture = 25.00
V_fixture = 0.000
| time   V(typ)   V(min)   V(max)
0s        0V         0V         0V
800ps     -10.24mV   -2.65mV    93.68mV
1ns       65.45mV    -9.54mV    470mV
1.2ns     260mV      1.3mV      910mV
1.6ns     730mV      170mV      1.56V
1.8ns     990mV      320mV      1.77V
2.2ns     1.36V      630mV      1.9V
2.8ns     1.52V      1V         1.93V
3.6ns     1.54V      1.13V      1.93V
10ns      1.54V      1.16V      1.93V
[Rising Waveform]
R_fixture = 25.00
V_fixture = 3.30
V_fixture_min = 3.00
V_fixture_max = 3.60
| time   V(typ)   V(min)   V(max)
0s        1.28V      1.46V      1.2V
400ps     1.28V      1.46V      1.2V
600ps     1.32V      1.46V      1.65V
800ps     1.79V      1.48V      2.86V
1ns       2.72V      1.88V      3.4V
1.2ns     3.15V      2.52V      3.57V
1.4ns     3.25V      2.78V      3.59V
1.6ns     3.28V      2.93V      3.59V
2ns       3.29V      2.99V      3.6V
10ns      3.3V       3V         3.6V
[Falling Waveform]
R_fixture = 25.00
V_fixture = 0.000
| time   V(typ)   V(min)   V(max)
0s        1.54V      1.16V      1.93V
400ps     1.54V      1.16V      1.93V
600ps     1.54V      1.16V      1.86V
800ps     1.47V      1.16V      1.12V
1ns       750mV      1.05V      230mV
1.2ns     150mV      610mV      9.46mV
1.4ns     25.23mV    260mV      4.15mV
1.6ns     4.57mV     58.67mV    2.44mV
1.8ns     2.66mV     9.91mV     1.74mV
10ns      0V         1.52uV     1.08uV
[Falling Waveform]
R_fixture = 25.00
V_fixture = 3.30
V_fixture_min = 3.00
V_fixture_max = 3.60
| time   V(typ)   V(min)   V(max)
0s        3.3V       3V         3.6V
800ps     3.31V      3V         3.57V
1ns       3.26V      3.01V      3.18V
1.2ns     3.06V      3.01V      2.66V
1.6ns     2.49V      2.81V      1.9V
1.8ns     2.19V      2.63V      1.6V
2.2ns     1.74V      2.28V      1.32V
3ns       1.37V      1.78V      1.22V
4.2ns     1.29V      1.54V      1.21V
10ns      1.28V      1.46V      1.2V
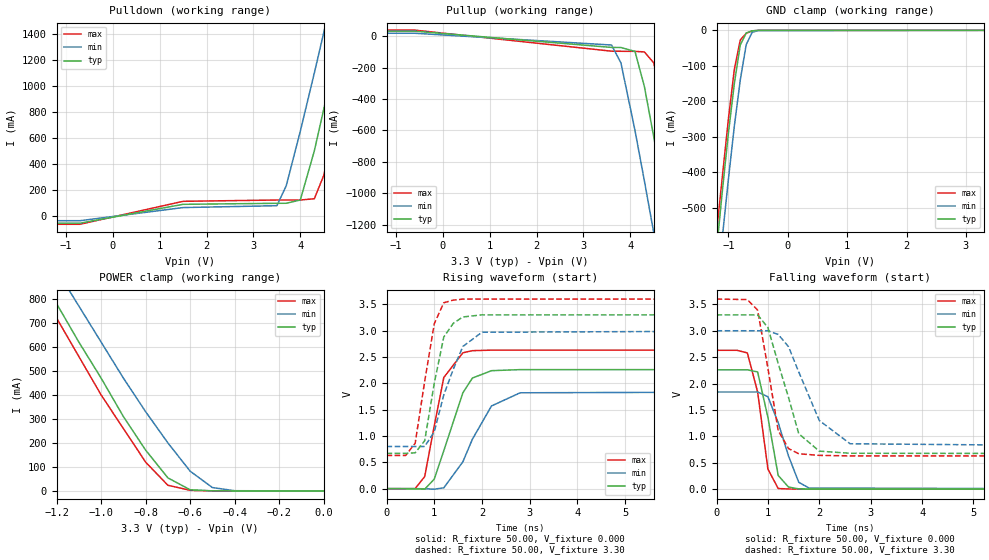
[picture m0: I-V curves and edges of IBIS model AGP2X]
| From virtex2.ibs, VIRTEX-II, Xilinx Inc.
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|   Model AGP2X
[Model]   AGP2X
Model_type   I/O
Polarity   Non-Inverting
Enable   Active-Low
Vinh = 1.52V
Vinl = 1.12V
| Vmeas depends on rising or falling edge, select one of the following:
| For rising edge:
|Vmeas =   0.940V
| For falling edge:
|Vmeas =   2.03V
Cref =  10.00pF
Rref =  50.00
| Vref depends on rising or falling edge, select one of the following:
| For rising edge:
|Vref =   0.00V
| For falling edge:
|Vref =   3.30V
C_comp   7.00pF   6.00pF   8.00pF
[Temperature Range]   25.00   100.00   0.000
[Voltage Range]   3.30V   3.00V   3.60V
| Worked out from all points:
|   slope of the pulldown table from 0 to 0.495 V, typ, clamps not added: 12 ohm
|   slope of the pullup table from 0 to 0.495 V, typ, clamps not added: 20.4 ohm
|   GND clamp passes 1 mA (typ) near -0.57 V on its own axis
|   POWER clamp passes 1 mA (typ) near -0.52 V on its own axis
|   rising waveform, R_fixture 50.00, V_fixture 0.000: 20-80 % time 495ps typ, 606ps min, 337ps max; typ from 0 V to 2.26 V
|   rising waveform, R_fixture 50.00, V_fixture 3.30: 20-80 % time 323ps typ, 489ps min, 316ps max; typ from 0.67 V to 3.3 V
|   falling waveform, R_fixture 50.00, V_fixture 0.000: 20-80 % time 269ps typ, 391ps min, 251ps max; typ from 2.26 V to 0 V
|   falling waveform, R_fixture 50.00, V_fixture 3.30: 20-80 % time 474ps typ, 588ps min, 311ps max; typ from 3.3 V to 0.67 V
[Pulldown]
| voltage   I(typ)   I(min)   I(max)
-3.3V     -58.45mA   -39.38mA   -66.87mA
-700mV    -58.45mA   -39.38mA   -66.87mA
1.5V      86.81mA    61.86mA    110mA
3.5V      94.77mA    76.19mA    120mA
3.7V      94.99mA    230mA      120mA
4V        120mA      650mA      120mA
4.3V      500mA      1.1A       130mA
4.5V      820mA      1.41A      310mA
4.9V      1.46A      2.03A      920mA
5.1V      1.79A      2.35A      1.25A
5.3V      2.12A      2.66A      1.58A
6.6V      4.29A      4.72A      3.74A
[Pullup]
| voltage   I(typ)   I(min)   I(max)
-3.3V     31.93mA    18.66mA    38.69mA
-600mV    31.93mA    18.66mA    38.69mA
3.6V      -71.52mA   -56.26mA   -95.39mA
3.8V      -71.99mA   -170mA     -96mA
4.1V      -97.11mA   -600mA     -96.86mA
4.3V      -320mA     -920mA     -100mA
4.5V      -640mA     -1.25A     -170mA
4.7V      -980mA     -1.59A     -440mA
4.9V      -1.32A     -1.93A     -770mA
5.1V      -1.67A     -2.27A     -1.11A
5.3V      -2.02A     -2.61A     -1.46A
6.6V      -4.32A     -4.85A     -3.75A
[GND_clamp]
| voltage   I(typ)   I(min)   I(max)
-3.3V     -4.3A      -4.31A     -4.26A
-1.2V     -620mA     -740mA     -570mA
-1.1V     -450mA     -580mA     -410mA
-1V       -290mA     -420mA     -250mA
-900mV    -150mA     -270mA     -110mA
-800mV    -41.03mA   -140mA     -27.28mA
-700mV    -7.6mA     -40.21mA   -8.18mA
-600mV    -1.42mA    -5.61mA    -1.62mA
-500mV    -130uA     -670uA     -130uA
3.3V      67.85pA    43.48uA    45.6pA
[POWER_clamp]
| voltage   I(typ)   I(min)   I(max)
-3.3V     4.25A      4.22A      4.2A
-1.3V     940mA      1.07A      880mA
-1.2V     780mA      920mA      720mA
-1.1V     620mA      770mA      560mA
-1V       470mA      620mA      400mA
-900mV    310mA      470mA      260mA
-800mV    170mA      330mA      120mA
-700mV    54.34mA    200mA      23.62mA
-600mV    4.76mA     82.21mA    2.52mA
-500mV    280uA      14.02mA    260uA
-400mV    16.9uA     860uA      14.85uA
0V        67.85pA    2.04nA     61.89pA
[Ramp]
| variable   typ   min   max
dV/dt_r   1.35/0.42n   1.11/0.59n   1.58/0.33n
dV/dt_f   1.58/0.39n   1.32/0.57n   1.78/0.30n
R_load = 50.00
[Rising Waveform]
R_fixture = 50.00
V_fixture = 0.000
| time   V(typ)   V(min)   V(max)
0s        0V         0V         0V
600ps     -3.75mV    -39.39uV   -100uV
800ps     -10.24mV   -2.9mV     230mV
1ns       180mV      -10.24mV   1.19V
1.2ns     720mV      14.98mV    2.11V
1.6ns     1.82V      510mV      2.58V
1.8ns     2.1V       940mV      2.62V
2.2ns     2.24V      1.57V      2.63V
2.8ns     2.26V      1.82V      2.63V
10ns      2.26V      1.84V      2.63V
[Rising Waveform]
R_fixture = 50.00
V_fixture = 3.30
V_fixture_min = 3.00
V_fixture_max = 3.60
| time   V(typ)   V(min)   V(max)
0s        670mV      800mV      630mV
400ps     670mV      800mV      630mV
600ps     680mV      800mV      860mV
800ps     910mV      800mV      2.04V
1ns       2V         1.08V      3.13V
1.2ns     2.88V      1.78V      3.53V
1.4ns     3.14V      2.27V      3.58V
1.6ns     3.26V      2.7V       3.6V
2ns       3.3V       2.97V      3.6V
10ns      3.3V       3V         3.6V
[Falling Waveform]
R_fixture = 50.00
V_fixture = 0.000
| time   V(typ)   V(min)   V(max)
0s        2.26V      1.84V      2.63V
400ps     2.26V      1.84V      2.63V
600ps     2.26V      1.84V      2.58V
800ps     2.22V      1.84V      1.84V
1ns       1.36V      1.75V      380mV
1.2ns     260mV      1.26V      12.11mV
1.4ns     40.37mV    630mV      3.88mV
1.6ns     5.34mV     130mV      1.45mV
1.8ns     1.93mV     21.54mV    690uV
10ns      850nV      -1.6uV     -2.54uV
[Falling Waveform]
R_fixture = 50.00
V_fixture = 3.30
V_fixture_min = 3.00
V_fixture_max = 3.60
| time   V(typ)   V(min)   V(max)
0s        3.3V       3V         3.6V
600ps     3.3V       3V         3.59V
800ps     3.3V       3V         3.39V
1ns       3.06V      3V         2.29V
1.2ns     2.38V      2.93V      1.11V
1.4ns     1.74V      2.7V       770mV
1.6ns     1.05V      2.22V      670mV
2ns       720mV      1.3V       640mV
2.6ns     680mV      860mV      630mV
10ns      670mV      800mV      630mV
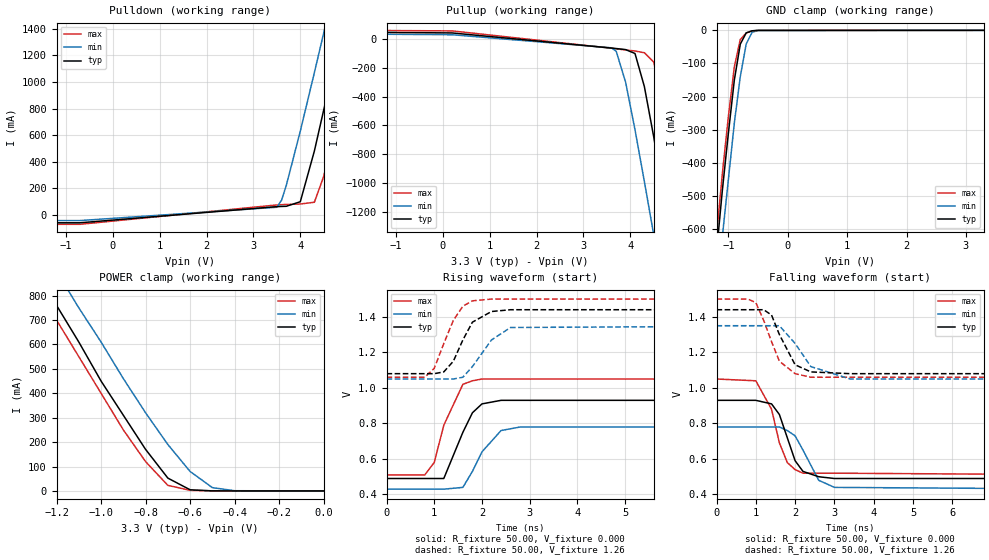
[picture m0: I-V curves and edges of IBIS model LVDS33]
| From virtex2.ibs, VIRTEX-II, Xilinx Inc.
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|   Model LVDS33
[Model]   LVDS33
Model_type   I/O
Polarity   Non-Inverting
Enable   Active-Low
Vinh = 1.4v
Vinl = 1.0v
Vmeas =   1.20V
Cref =  10.00pF
Rref =  50.00
Vref =   1.20V
C_comp   7.00pF   6.00pF   8.00pF
[Temperature Range]   25.00   100.00   0.000
[Voltage Range]   3.30V   3.00V   3.60V
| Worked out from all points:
|   slope of the pulldown table from 0 to 0.495 V, typ, clamps not added: 25 ohm
|   slope of the pullup table from 0 to 0.495 V, typ, clamps not added: 47.9 ohm
|   GND clamp passes 1 mA (typ) near -0.57 V on its own axis
|   POWER clamp passes 1 mA (typ) near -0.52 V on its own axis
|   rising waveform, R_fixture 50.00, V_fixture 0.000: 20-80 % time 391ps typ, 467ps min, 408ps max; typ from 0.49 V to 0.93 V
|   rising waveform, R_fixture 50.00, V_fixture 1.26: 20-80 % time 393ps typ, 513ps min, 426ps max; typ from 1.08 V to 1.44 V
|   falling waveform, R_fixture 50.00, V_fixture 0.000: 20-80 % time 428ps typ, 493ps min, 455ps max; typ from 0.93 V to 0.49 V
|   falling waveform, R_fixture 50.00, V_fixture 1.26: 20-80 % time 461ps typ, 564ps min, 472ps max; typ from 1.44 V to 1.08 V
[Pulldown]
| voltage   I(typ)   I(min)   I(max)
-3.3V     -60.18mA   -43.43mA   -71.54mA
-700mV    -60.18mA   -43.43mA   -71.54mA
3.5V      61.45mA    56.78mA    74.25mA
3.6V      62.84mA    110mA      76.15mA
3.7V      64.01mA    220mA      77.65mA
4V        98.36mA    630mA      81.23mA
4.3V      480mA      1.07A      94.53mA
4.5V      790mA      1.37A      290mA
4.9V      1.42A      1.98A      890mA
5.1V      1.75A      2.29A      1.21A
5.3V      2.07A      2.6A       1.53A
6.6V      4.19A      4.62A      3.65A
[Pullup]
| voltage   I(typ)   I(min)   I(max)
-3.3V     51.86mA    38.8mA     63.28mA
200mV     42.76mA    30.26mA    56.97mA
3.6V      -62.38mA   -60.66mA   -63.6mA
3.7V      -65.72mA   -84.95mA   -67.64mA
3.9V      -73.04mA   -300mA     -75.36mA
4.1V      -100mA     -630mA     -82.68mA
4.3V      -330mA     -990mA     -94.94mA
4.5V      -680mA     -1.36A     -160mA
4.7V      -1.07A     -1.75A     -450mA
4.9V      -1.48A     -2.13A     -830mA
5.1V      -1.89A     -2.52A     -1.23A
6.6V      -5.03A     -5.46A     -4.35A
[GND_clamp]
| voltage   I(typ)   I(min)   I(max)
-3.3V     -5.03A     -4.87A     -4.98A
-1.2V     -670mA     -800mA     -620mA
-1.1V     -480mA     -620mA     -430mA
-1V       -310mA     -450mA     -260mA
-900mV    -150mA     -280mA     -110mA
-800mV    -41.81mA   -140mA     -27.69mA
-700mV    -7.62mA    -40.98mA   -8.11mA
-600mV    -1.38mA    -5.69mA    -1.55mA
-500mV    -120uA     -670uA     -110uA
3.3V      720pA      41.58uA    640pA
[POWER_clamp]
| voltage   I(typ)   I(min)   I(max)
-3.3V     4.17A      4.13A      4.11A
-1.3V     920mA      1.05A      860mA
-1.2V     760mA      900mA      700mA
-1.1V     610mA      750mA      550mA
-1V       450mA      610mA      400mA
-900mV    310mA      460mA      250mA
-800mV    170mA      320mA      120mA
-700mV    52.5mA     190mA      22.73mA
-600mV    4.56mA     79.5mA     2.44mA
-500mV    270uA      13.41mA    250uA
-400mV    16.38uA    820uA      14.45uA
0V        720pA      2.62nA     780pA
[Ramp]
| variable   typ   min   max
dV/dt_r   0.27/0.37n   0.21/0.45n   0.32/0.32n
dV/dt_f   0.11/0.17n   93.00m/0.19n   0.15/0.15n
R_load = 50.00
[Rising Waveform]
R_fixture = 50.00
V_fixture = 0.000
| time   V(typ)   V(min)   V(max)
0s        490mV      430mV      510mV
800ps     490mV      430mV      510mV
1ns       490mV      430mV      580mV
1.2ns     490mV      430mV      790mV
1.6ns     750mV      440mV      1.02V
1.8ns     860mV      530mV      1.04V
2ns       910mV      640mV      1.05V
2.4ns     930mV      760mV      1.05V
2.8ns     930mV      780mV      1.05V
10ns      930mV      780mV      1.05V
[Rising Waveform]
R_fixture = 50.00
V_fixture = 1.26
V_fixture_min = 1.20
V_fixture_max = 1.28
| time   V(typ)   V(min)   V(max)
0s        1.08V      1.05V      1.06V
800ps     1.08V      1.05V      1.06V
1ns       1.08V      1.05V      1.11V
1.2ns     1.09V      1.05V      1.25V
1.4ns     1.15V      1.05V      1.38V
1.6ns     1.27V      1.06V      1.46V
1.8ns     1.37V      1.12V      1.49V
2.2ns     1.43V      1.27V      1.5V
2.6ns     1.44V      1.34V      1.5V
10ns      1.44V      1.35V      1.5V
[Falling Waveform]
R_fixture = 50.00
V_fixture = 0.000
| time   V(typ)   V(min)   V(max)
0s        930mV      780mV      1.05V
1ns       930mV      780mV      1.04V
1.4ns     910mV      780mV      880mV
1.6ns     850mV      780mV      690mV
1.8ns     720mV      760mV      580mV
2ns       590mV      730mV      540mV
2.2ns     530mV      650mV      520mV
2.6ns     500mV      480mV      520mV
3ns       490mV      440mV      520mV
10ns      490mV      430mV      510mV
[Falling Waveform]
R_fixture = 50.00
V_fixture = 1.26
V_fixture_min = 1.20
V_fixture_max = 1.28
| time   V(typ)   V(min)   V(max)
0s        1.44V      1.35V      1.5V
800ps     1.44V      1.35V      1.5V
1ns       1.44V      1.35V      1.48V
1.2ns     1.44V      1.35V      1.38V
1.4ns     1.41V      1.35V      1.26V
1.6ns     1.3V       1.35V      1.15V
2ns       1.13V      1.25V      1.08V
2.4ns     1.09V      1.12V      1.06V
3.4ns     1.08V      1.05V      1.06V
10ns      1.08V      1.05V      1.06V
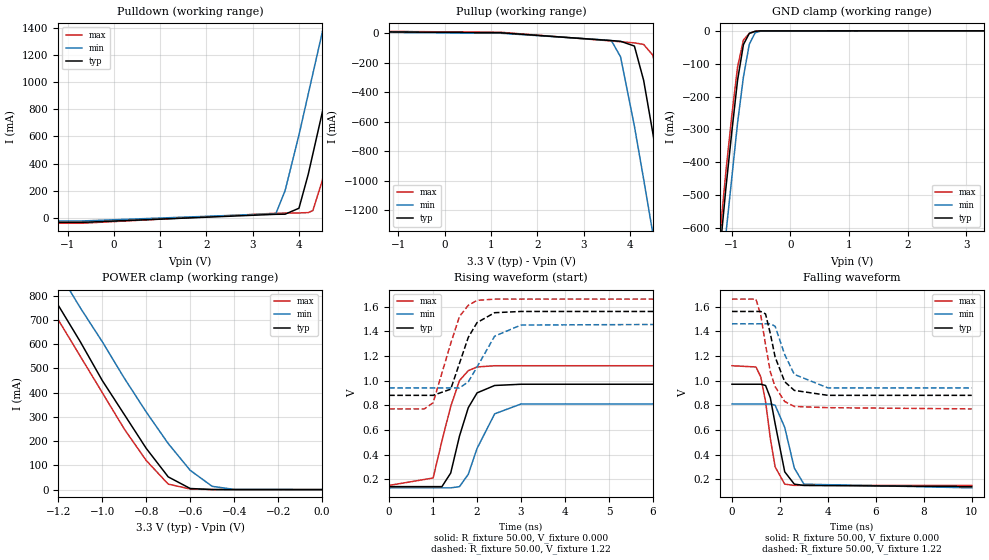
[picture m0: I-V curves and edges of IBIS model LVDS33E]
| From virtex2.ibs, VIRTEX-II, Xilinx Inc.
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|   Model LVDS33E
[Model]   LVDS33E
Model_type   I/O
Polarity   Non-Inverting
Enable   Active-Low
Vinh = 1.5v
Vinl = 0.8v
Vmeas =   1.20V
Cref =  10.00pF
Rref =  50.00
Vref =   1.20V
C_comp   7.00pF   6.00pF   8.00pF
[Temperature Range]   25.00   100.00   0.000
[Voltage Range]   3.30V   3.00V   3.60V
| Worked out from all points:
|   slope of the pulldown table from 0 to 0.495 V, typ, clamps not added: 44.6 ohm
|   slope of the pullup table from 0 to 0.495 V, typ, clamps not added: 202 ohm
|   GND clamp passes 1 mA (typ) near -0.57 V on its own axis
|   POWER clamp passes 1 mA (typ) near -0.52 V on its own axis
|   rising waveform, R_fixture 50.00, V_fixture 0.000: 20-80 % time 403ps typ, 463ps min, 440ps max; typ from 0.14 V to 0.97 V
|   rising waveform, R_fixture 50.00, V_fixture 1.22: 20-80 % time 441ps typ, 503ps min, 449ps max; typ from 0.88 V to 1.56 V
|   falling waveform, R_fixture 50.00, V_fixture 0.000: 20-80 % time 485ps typ, 543ps min, 458ps max; typ from 0.97 V to 0.14 V
|   falling waveform, R_fixture 50.00, V_fixture 1.22: 20-80 % time 581ps typ, 656ps min, 565ps max; typ from 1.56 V to 0.88 V
[Pulldown]
| voltage   I(typ)   I(min)   I(max)
-3.3V     -32.45mA   -22.08mA   -38.7mA
-700mV    -32.45mA   -22.08mA   -38.7mA
3.5V      26.98mA    31.24mA    34.96mA
3.7V      27.85mA    200mA      36.01mA
4V        71.51mA    610mA      37.17mA
4.2V      320mA      910mA      39.61mA
4.3V      470mA      1.06A      54.04mA
4.5V      770mA      1.36A      270mA
4.9V      1.41A      1.97A      880mA
5.1V      1.73A      2.28A      1.19A
5.3V      2.06A      2.59A      1.52A
6.6V      4.18A      4.61A      3.63A
[Pullup]
| voltage   I(typ)   I(min)   I(max)
-3.3V     13.05mA    9.95mA     16.56mA
1.2V      2.86mA     -250uA     6.38mA
3.6V      -50.23mA   -49.03mA   -52.73mA
3.8V      -54.82mA   -160mA     -58.13mA
4.1V      -87.31mA   -630mA     -65.7mA
4.3V      -320mA     -990mA     -76.3mA
4.5V      -680mA     -1.36A     -150mA
4.7V      -1.07A     -1.74A     -450mA
4.9V      -1.48A     -2.13A     -830mA
5.1V      -1.89A     -2.52A     -1.22A
5.3V      -2.3A      -2.91A     -1.63A
6.6V      -5.03A     -5.46A     -4.35A
[GND_clamp]
| voltage   I(typ)   I(min)   I(max)
-3.3V     -5.03A     -4.87A     -4.98A
-1.2V     -670mA     -800mA     -620mA
-1.1V     -480mA     -620mA     -430mA
-1V       -310mA     -450mA     -260mA
-900mV    -150mA     -280mA     -110mA
-800mV    -41.81mA   -140mA     -27.69mA
-700mV    -7.62mA    -40.98mA   -8.11mA
-600mV    -1.38mA    -5.69mA    -1.55mA
-500mV    -120uA     -670uA     -110uA
3.3V      720pA      41.58uA    640pA
[POWER_clamp]
| voltage   I(typ)   I(min)   I(max)
-3.3V     4.17A      4.13A      4.11A
-1.3V     920mA      1.05A      860mA
-1.2V     760mA      900mA      700mA
-1.1V     610mA      750mA      550mA
-1V       450mA      610mA      400mA
-900mV    310mA      460mA      250mA
-800mV    170mA      320mA      120mA
-700mV    52.5mA     190mA      22.73mA
-600mV    4.56mA     79.5mA     2.44mA
-500mV    270uA      13.41mA    250uA
-400mV    16.38uA    820uA      14.45uA
0V        720pA      2.62nA     780pA
[Ramp]
| variable   typ   min   max
dV/dt_r   0.50/0.38n   0.41/0.45n   0.58/0.34n
dV/dt_f   0.25/0.15n   0.18/0.18n   0.34/0.15n
R_load = 50.00
[Rising Waveform]
R_fixture = 50.00
V_fixture = 0.000
| time   V(typ)   V(min)   V(max)
0s        140mV      130mV      150mV
1ns       140mV      130mV      210mV
1.2ns     140mV      130mV      510mV
1.4ns     250mV      130mV      790mV
1.6ns     550mV      140mV      1V
1.8ns     780mV      240mV      1.08V
2ns       900mV      450mV      1.11V
2.4ns     960mV      730mV      1.12V
3ns       970mV      810mV      1.12V
10ns      970mV      810mV      1.12V
[Rising Waveform]
R_fixture = 50.00
V_fixture = 1.22
V_fixture_min = 1.20
V_fixture_max = 1.22
| time   V(typ)   V(min)   V(max)
0s        880mV      940mV      770mV
800ps     880mV      940mV      770mV
1ns       880mV      940mV      820mV
1.4ns     930mV      940mV      1.3V
1.6ns     1.14V      940mV      1.52V
1.8ns     1.35V      990mV      1.61V
2ns       1.47V      1.11V      1.65V
2.4ns     1.55V      1.36V      1.66V
3ns       1.56V      1.45V      1.66V
10ns      1.56V      1.46V      1.66V
[Falling Waveform]
R_fixture = 50.00
V_fixture = 0.000
| time   V(typ)   V(min)   V(max)
0s        970mV      810mV      1.12V
1ns       970mV      810mV      1.11V
1.2ns     970mV      810mV      1.03V
1.4ns     960mV      810mV      830mV
1.6ns     860mV      810mV      530mV
1.8ns     650mV      800mV      300mV
2.2ns     260mV      620mV      160mV
2.6ns     160mV      290mV      150mV
3ns       150mV      160mV      150mV
10ns      140mV      130mV      150mV
[Falling Waveform]
R_fixture = 50.00
V_fixture = 1.22
V_fixture_min = 1.20
V_fixture_max = 1.22
| time   V(typ)   V(min)   V(max)
0s        1.56V      1.46V      1.66V
1ns       1.56V      1.46V      1.66V
1.2ns     1.56V      1.46V      1.53V
1.4ns     1.54V      1.46V      1.29V
1.6ns     1.38V      1.46V      1.07V
1.8ns     1.19V      1.44V      950mV
2.2ns     990mV      1.21V      830mV
2.6ns     920mV      1.05V      790mV
4ns       880mV      940mV      780mV
10ns      880mV      940mV      770mV
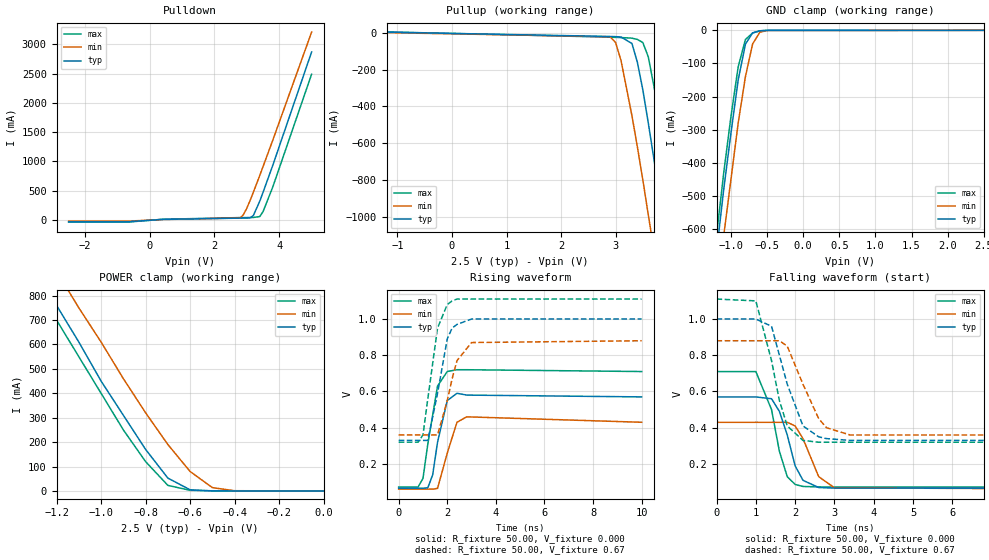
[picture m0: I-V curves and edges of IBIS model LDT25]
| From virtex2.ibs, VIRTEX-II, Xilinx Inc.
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|   Model LDT25
[Model]   LDT25
Model_type   I/O
Polarity   Non-Inverting
Enable   Active-Low
Vinh = 0.9v
Vinl = 0.3v
Vmeas =   0.60V
Cref =  10.00pF
Rref =  50.00
Vref =   0.60V
C_comp   7.00pF   6.00pF   8.00pF
[Temperature Range]   25.00   100.00   0.000
[Voltage Range]   2.50V   2.30V   2.70V
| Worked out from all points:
|   slope of the pulldown table from 0 to 0.375 V, typ, clamps not added: 32.9 ohm
|   slope of the pullup table from 0 to 0.375 V, typ, clamps not added: 250 ohm
|   GND clamp passes 1 mA (typ) near -0.57 V on its own axis
|   POWER clamp passes 1 mA (typ) near -0.52 V on its own axis
|   rising waveform, R_fixture 50.00, V_fixture 0.000: 20-80 % time 369ps typ, 406ps min, 456ps max; typ from 0.066 V to 0.57 V
|   rising waveform, R_fixture 50.00, V_fixture 0.67: 20-80 % time 500ps typ, 567ps min, 486ps max; typ from 0.33 V to 1 V
|   falling waveform, R_fixture 50.00, V_fixture 0.000: 20-80 % time 426ps typ, 437ps min, 418ps max; typ from 0.57 V to 0.066 V
|   falling waveform, R_fixture 50.00, V_fixture 0.67: 20-80 % time 563ps typ, 621ps min, 494ps max; typ from 1 V to 0.33 V
[Pulldown]
| voltage   I(typ)   I(min)   I(max)
-2.5V     -33.36mA   -22.19mA   -39.78mA
-700mV    -33.36mA   -22.19mA   -39.78mA
400mV     7.96mA     5.89mA     10.4mA
2.8V      29.73mA    32.75mA    38.99mA
2.9V      30.03mA    93.36mA    39.35mA
3V        30.49mA    200mA      39.69mA
3.1V      33.77mA    330mA      40.03mA
3.2V      72.89mA    470mA      40.5mA
3.4V      320mA      760mA      56.44mA
3.5V      470mA      910mA      140mA
3.8V      930mA      1.36A      560mA
5V        2.87A      3.21A      2.49A
[Pullup]
| voltage   I(typ)   I(min)   I(max)
-2.5V     11.96mA    8.86mA     14.94mA
2.9V      -19.1mA    -20.51mA   -22.87mA
3V        -20.02mA   -51.9mA    -23.94mA
3.1V      -21.93mA   -150mA     -24.97mA
3.3V      -57.15mA   -450mA     -28.18mA
3.4V      -160mA     -620mA     -35.08mA
3.5V      -310mA     -800mA     -52.11mA
3.6V      -490mA     -990mA     -130mA
3.8V      -870mA     -1.36A     -440mA
4V        -1.27A     -1.74A     -820mA
4.2V      -1.68A     -2.13A     -1.22A
5V        -3.34A     -3.69A     -2.88A
[GND_clamp]
| voltage   I(typ)   I(min)   I(max)
-2.5V     -3.34A     -3.3A      -3.3A
-1.2V     -670mA     -800mA     -620mA
-1.1V     -480mA     -620mA     -430mA
-1V       -310mA     -450mA     -260mA
-900mV    -150mA     -280mA     -110mA
-800mV    -41.81mA   -140mA     -27.69mA
-700mV    -7.62mA    -40.98mA   -8.11mA
-600mV    -1.38mA    -5.69mA    -1.55mA
-500mV    -120uA     -670uA     -110uA
2.5V      540pA      2.11uA     480pA
[POWER_clamp]
| voltage   I(typ)   I(min)   I(max)
-2.5V     2.86A      2.89A      2.8A
-1.3V     920mA      1.05A      860mA
-1.2V     760mA      900mA      700mA
-1.1V     610mA      750mA      550mA
-1V       450mA      610mA      400mA
-900mV    310mA      460mA      250mA
-800mV    170mA      320mA      120mA
-700mV    52.5mA     190mA      22.73mA
-600mV    4.56mA     79.5mA     2.44mA
-500mV    270uA      13.41mA    250uA
-400mV    16.38uA    820uA      14.45uA
0V        540pA      2.08nA     580pA
[Ramp]
| variable   typ   min   max
dV/dt_r   0.30/0.37n   0.22/0.40n   0.38/0.37n
dV/dt_f   0.29/0.18n   0.22/0.20n   0.38/0.18n
R_load = 50.00
[Rising Waveform]
R_fixture = 50.00
V_fixture = 0.000
| time   V(typ)   V(min)   V(max)
0s        66.14mV    60.99mV    72.75mV
800ps     66.11mV    60.99mV    72.82mV
1ns       65.9mV     60.97mV    120mV
1.2ns     68.46mV    61.08mV    310mV
1.4ns     140mV      60.77mV    470mV
1.6ns     320mV      65.22mV    630mV
2ns       550mV      260mV      710mV
2.4ns     590mV      430mV      720mV
2.8ns     580mV      460mV      720mV
10ns      570mV      430mV      710mV
[Rising Waveform]
R_fixture = 50.00
V_fixture = 0.67
V_fixture_min = 0.62
V_fixture_max = 0.72
| time   V(typ)   V(min)   V(max)
0s        330mV      360mV      320mV
800ps     330mV      360mV      320mV
1ns       330mV      360mV      360mV
1.2ns     330mV      360mV      560mV
1.6ns     590mV      360mV      950mV
2ns       890mV      550mV      1.08V
2.2ns     950mV      670mV      1.1V
2.4ns     970mV      770mV      1.11V
3ns       1V         870mV      1.11V
10ns      1V         880mV      1.11V
[Falling Waveform]
R_fixture = 50.00
V_fixture = 0.000
| time   V(typ)   V(min)   V(max)
0s        570mV      430mV      710mV
1ns       570mV      430mV      710mV
1.4ns     560mV      430mV      500mV
1.6ns     490mV      430mV      270mV
1.8ns     360mV      430mV      130mV
2ns       190mV      410mV      87.09mV
2.2ns     110mV      340mV      76.02mV
2.6ns     70.05mV    130mV      73.41mV
3ns       66.93mV    68.75mV    73.21mV
10ns      66.16mV    61.07mV    72.76mV
[Falling Waveform]
R_fixture = 50.00
V_fixture = 0.67
V_fixture_min = 0.62
V_fixture_max = 0.72
| time   V(typ)   V(min)   V(max)
0s        1V         880mV      1.11V
1ns       1V         880mV      1.1V
1.4ns     960mV      880mV      770mV
1.6ns     800mV      880mV      550mV
1.8ns     640mV      850mV      410mV
2.2ns     410mV      640mV      330mV
2.6ns     350mV      450mV      320mV
2.8ns     340mV      400mV      320mV
3.4ns     330mV      360mV      320mV
10ns      330mV      360mV      320mV
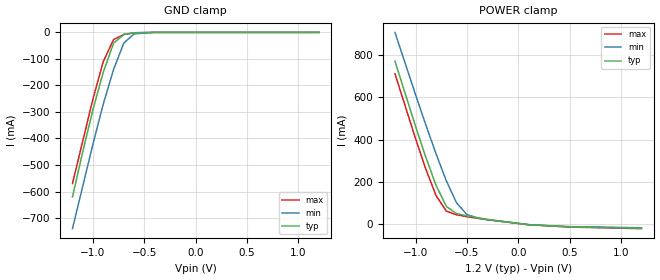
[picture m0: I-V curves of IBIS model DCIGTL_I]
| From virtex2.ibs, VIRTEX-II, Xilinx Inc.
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|   Model DCIGTL_I
[Model]   DCIGTL_I
Model_type   Input
Vinh = 0.85V
Vinl = 0.75V
Polarity   Non-Inverting
C_comp   7.00pF   6.00pF   8.00pF
[Temperature Range]   25.00   100.00   0.000
[Voltage Range]   1.20V   1.14V   1.26V
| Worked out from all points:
|   GND clamp passes 1 mA (typ) near -0.57 V on its own axis
|   POWER clamp passes 1 mA (typ) near -0.02 V on its own axis
[GND_clamp]
| voltage   I(typ)   I(min)   I(max)
-1.2V     -620mA     -740mA     -570mA
-1.1V     -450mA     -580mA     -410mA
-1V       -290mA     -420mA     -250mA
-900mV    -150mA     -270mA     -110mA
-800mV    -40.94mA   -140mA     -27.12mA
-700mV    -7.51mA    -40.15mA   -8.04mA
-600mV    -1.38mA    -5.56mA    -1.56mA
-400mV    -6.56uA    -62.75uA   -4.51uA
1.2V      21.68pA    25.98nA    12.71pA
[POWER_clamp]
| voltage   I(typ)   I(min)   I(max)
-1.2V     771.7mA    908.8mA    712.2mA
-1V       463.4mA    613.5mA    404.8mA
-900mV    316.6mA    470.1mA    260.1mA
-800mV    182.2mA    331.9mA    133.6mA
-700mV    82.28mA    203.8mA    59.67mA
-600mV    47.94mA    98.62mA    42.25mA
-500mV    37.29mA    43.64mA    33.48mA
-400mV    28.52mA    28.26mA    25.88mA
-300mV    20.31mA    19.71mA    18.67mA
100mV     -4.779mA   -4.506mA   -4.755mA
500mV     -14.86mA   -13.92mA   -15.97mA
1.2V      -21.22mA   -19.34mA   -23.53mA
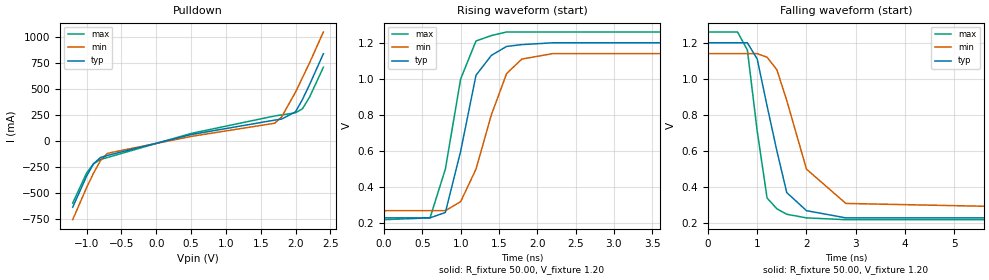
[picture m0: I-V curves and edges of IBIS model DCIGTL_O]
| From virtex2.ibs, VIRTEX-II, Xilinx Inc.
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|   Model DCIGTL_O
[Model]   DCIGTL_O
Model_type   Open_drain
Polarity   Non-Inverting
Vmeas =   0.80V
Cref =  0.000F
Rref =  50.00
Vref =   1.20V
C_comp   7.00pF   6.00pF   8.00pF
[Temperature Range]   25.00   100.00   0.000
[Voltage Range]   1.20V   1.14V   1.26V
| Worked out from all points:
|   slope of the pulldown table from 0 to 0.18 V, typ, clamps not added: 5.73 ohm
|   rising waveform, R_fixture 50.00, V_fixture 1.20: 20-80 % time 297ps typ, 407ps min, 303ps max; typ from 0.23 V to 1.2 V
|   falling waveform, R_fixture 50.00, V_fixture 1.20: 20-80 % time 473ps typ, 626ps min, 304ps max; typ from 1.2 V to 0.23 V
[Pulldown]
| voltage   I(typ)   I(min)   I(max)
-1.2V     -640mA     -760mA     -600mA
-1V       -340mA     -450mA     -310mA
-900mV    -220mA     -310mA     -220mA
-800mV    -160mA     -190mA     -180mA
-700mV    -140mA     -120mA     -160mA
500mV     60.56mA    42.69mA    71.53mA
1.7V      200mA      170mA      240mA
1.8V      210mA      230mA      250mA
2V        280mA      470mA      270mA
2.1V      400mA      610mA      310mA
2.2V      540mA      750mA      420mA
2.4V      840mA      1.05A      710mA
[Ramp]
| variable   typ   min   max
dV/dt_r   0.58/0.26n   0.52/0.31n   0.63/0.25n
dV/dt_f   0.58/0.37n   0.52/0.59n   0.63/0.27n
R_load = 50.00
[Rising Waveform]
R_fixture = 50.00
V_fixture = 1.20
V_fixture_min = 1.14
V_fixture_max = 1.26
| time   V(typ)   V(min)   V(max)
0s        230mV      270mV      220mV
600ps     230mV      270mV      230mV
800ps     260mV      270mV      500mV
1ns       600mV      320mV      1V
1.2ns     1.02V      500mV      1.21V
1.4ns     1.13V      800mV      1.24V
1.6ns     1.18V      1.03V      1.26V
1.8ns     1.19V      1.11V      1.26V
2.2ns     1.2V       1.14V      1.26V
10ns      1.2V       1.14V      1.26V
[Falling Waveform]
R_fixture = 50.00
V_fixture = 1.20
V_fixture_min = 1.14
V_fixture_max = 1.26
| time   V(typ)   V(min)   V(max)
0s        1.2V       1.14V      1.26V
600ps     1.2V       1.14V      1.26V
800ps     1.2V       1.14V      1.16V
1ns       1.11V      1.14V      710mV
1.2ns     850mV      1.12V      340mV
1.4ns     600mV      1.05V      280mV
1.6ns     370mV      880mV      250mV
2ns       270mV      500mV      230mV
2.8ns     230mV      310mV      220mV
10ns      230mV      270mV      220mV
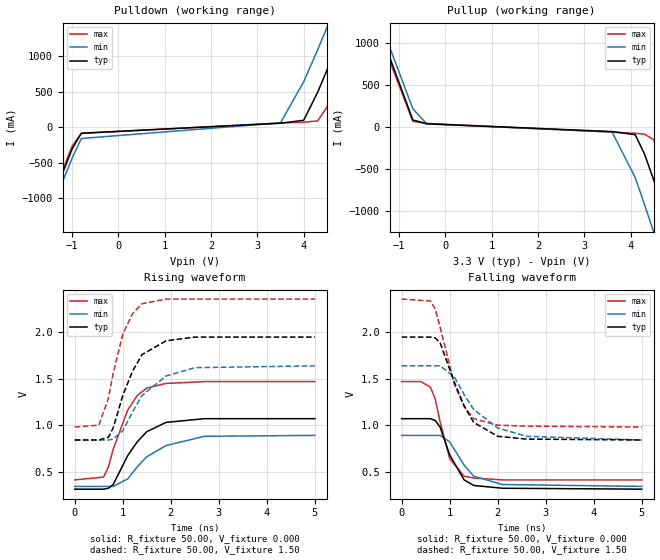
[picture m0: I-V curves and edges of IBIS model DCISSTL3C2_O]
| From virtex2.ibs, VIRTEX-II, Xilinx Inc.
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|   Model DCISSTL3C2_O
[Model]   DCISSTL3C2_O
Model_type   Output
Polarity   Non-Inverting
Vmeas =   1.50V
Cref =  30.00pF
Rref =  50.00
Vref =   1.50V
C_comp   7.00pF   6.00pF   8.00pF
[Temperature Range]   25.00   100.00   0.000
[Voltage Range]   3.30V   3.00V   3.60V
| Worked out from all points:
|   slope of the pulldown table from 0 to 0.495 V, typ, clamps not added: 21.3 ohm
|   slope of the pullup table from 0 to 0.495 V, typ, clamps not added: 31.8 ohm
|   rising waveform, R_fixture 50.00, V_fixture 0.000: 20-80 % time 568ps typ, 757ps min, 474ps max; typ from 0.31 V to 1.07 V
|   rising waveform, R_fixture 50.00, V_fixture 1.50: 20-80 % time 510ps typ, 683ps min, 398ps max; typ from 0.84 V to 1.95 V
|   falling waveform, R_fixture 50.00, V_fixture 0.000: 20-80 % time 369ps typ, 450ps min, 309ps max; typ from 1.07 V to 0.31 V
|   falling waveform, R_fixture 50.00, V_fixture 1.50: 20-80 % time 528ps typ, 756ps min, 462ps max; typ from 1.95 V to 0.84 V
[Pulldown]
| voltage   I(typ)   I(min)   I(max)
-3.3V     -4.31A     -4.32A     -4.27A
-1.7V     -1.48A     -1.58A     -1.44A
-1.5V     -1.14A     -1.24A     -1.09A
-1V       -310mA     -440mA     -270mA
-800mV    -85.63mA   -160mA     -88.06mA
3.5V      55.14mA    61.28mA    58.45mA
4V        96.82mA    640mA      69.2mA
4.3V      490mA      1.09A      86.83mA
4.5V      800mA      1.4A       280mA
4.9V      1.45A      2.02A      900mA
5.3V      2.11A      2.65A      1.55A
6.6V      4.27A      4.72A      3.71A
[Pullup]
| voltage   I(typ)   I(min)   I(max)
-3.3V     4.26A      4.23A      4.21A
-1.5V     1.28A      1.39A      1.22A
-700mV    85.75mA    220mA      69.59mA
-400mV    40.04mA    38.67mA    44.3mA
3.6V      -52.66mA   -57.26mA   -59.63mA
4.1V      -89.87mA   -600mA     -73.02mA
4.3V      -320mA     -920mA     -82.95mA
4.5V      -630mA     -1.25A     -150mA
4.9V      -1.32A     -1.92A     -760mA
5.1V      -1.66A     -2.26A     -1.1A
5.3V      -2.01A     -2.61A     -1.45A
6.6V      -4.31A     -4.84A     -3.74A
[Ramp]
| variable   typ   min   max
dV/dt_r   0.45/0.58n   0.33/0.77n   0.64/0.47n
dV/dt_f   0.63/0.88n   0.44/1.11n   0.73/0.72n
R_load = 50.00
[Rising Waveform]
R_fixture = 50.00
V_fixture = 0.000
| time   V(typ)   V(min)   V(max)
0s        310mV      340mV      410mV
600ps     310mV      340mV      440mV
700ps     320mV      340mV      550mV
800ps     360mV      340mV      740mV
1.1ns     670mV      420mV      1.16V
1.3ns     820mV      550mV      1.32V
1.5ns     930mV      660mV      1.4V
1.9ns     1.03V      780mV      1.45V
2.7ns     1.07V      880mV      1.47V
5ns       1.07V      890mV      1.47V
[Rising Waveform]
R_fixture = 50.00
V_fixture = 1.50
V_fixture_min = 1.30
V_fixture_max = 1.70
| time   V(typ)   V(min)   V(max)
0s        840mV      840mV      980mV
500ps     840mV      840mV      1V
700ps     870mV      840mV      1.29V
800ps     970mV      850mV      1.56V
1ns       1.32V      940mV      1.98V
1.2ns     1.58V      1.14V      2.2V
1.4ns     1.76V      1.32V      2.31V
1.9ns     1.91V      1.53V      2.36V
2.5ns     1.95V      1.62V      2.36V
5ns       1.95V      1.64V      2.36V
[Falling Waveform]
R_fixture = 50.00
V_fixture = 0.000
| time   V(typ)   V(min)   V(max)
0s        1.07V      890mV      1.47V
400ps     1.07V      890mV      1.47V
600ps     1.07V      890mV      1.41V
700ps     1.05V      890mV      1.28V
800ps     980mV      890mV      1.04V
1ns       680mV      820mV      640mV
1.3ns     410mV      570mV      450mV
1.5ns     350mV      450mV      430mV
2.1ns     320mV      360mV      410mV
5ns       310mV      340mV      410mV
[Falling Waveform]
R_fixture = 50.00
V_fixture = 1.50
V_fixture_min = 1.30
V_fixture_max = 1.70
| time   V(typ)   V(min)   V(max)
0s        1.95V      1.64V      2.36V
600ps     1.95V      1.64V      2.34V
700ps     1.94V      1.64V      2.25V
800ps     1.89V      1.64V      2.06V
1.1ns     1.46V      1.52V      1.44V
1.3ns     1.21V      1.33V      1.2V
1.5ns     1.03V      1.17V      1.07V
2ns       880mV      970mV      1V
2.6ns     850mV      880mV      990mV
5ns       840mV      840mV      980mV
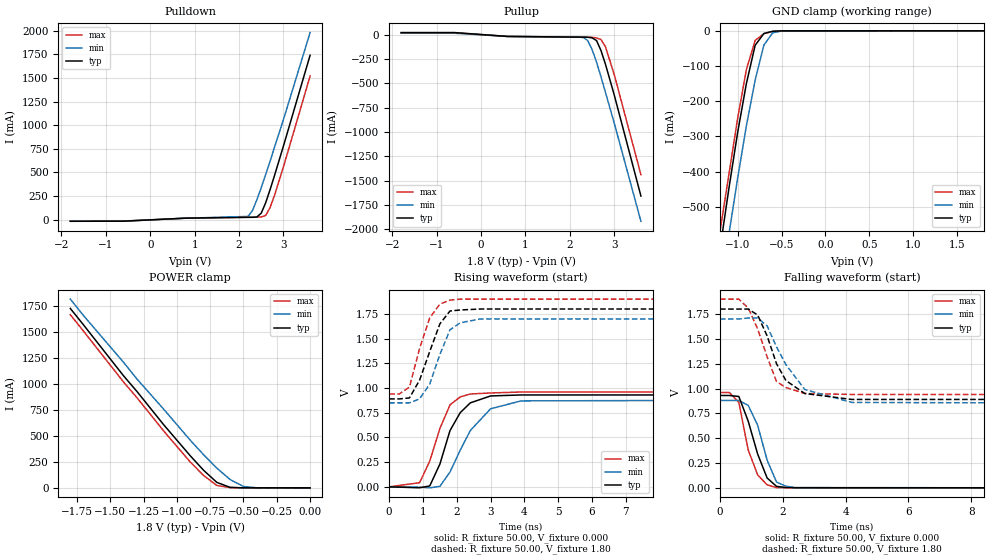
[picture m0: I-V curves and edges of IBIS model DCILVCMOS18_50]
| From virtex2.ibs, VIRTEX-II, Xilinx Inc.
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|   Model DCILVCMOS18_50
[Model]   DCILVCMOS18_50
Model_type   I/O
Polarity   Non-Inverting
Enable   Active-Low
Vinh = 1.19V
Vinl = 0.4V
Vmeas =   0.90V
Cref =  35.00pF
Rref =   1.00M
Vref =  0.000V
C_comp   7.00pF   6.00pF   8.00pF
[Temperature Range]   25.00   100.00   0.000
[Voltage Range]   1.80V   1.70V   1.90V
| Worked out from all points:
|   slope of the pulldown table from 0 to 0.27 V, typ, clamps not added: 39.7 ohm
|   slope of the pullup table from 0 to 0.27 V, typ, clamps not added: 31.4 ohm
|   GND clamp passes 1 mA (typ) near -0.57 V on its own axis
|   POWER clamp passes 1 mA (typ) near -0.52 V on its own axis
|   rising waveform, R_fixture 50.00, V_fixture 0.000: 20-80 % time 650ps typ, 852ps min, 616ps max; typ from 0 V to 0.93 V
|   rising waveform, R_fixture 50.00, V_fixture 1.80: 20-80 % time 579ps typ, 568ps min, 504ps max; typ from 0.89 V to 1.8 V
|   falling waveform, R_fixture 50.00, V_fixture 0.000: 20-80 % time 581ps typ, 552ps min, 468ps max; typ from 0.93 V to 0 V
|   falling waveform, R_fixture 50.00, V_fixture 1.80: 20-80 % time 752ps typ, 975ps min, 680ps max; typ from 1.8 V to 0.89 V
[Pulldown]
| voltage   I(typ)   I(min)   I(max)
-1.8V     -16.4mA    -14.51mA   -15.8mA
-600mV    -15mA      -14.51mA   -14.37mA
800mV     16.88mA    16.28mA    16.96mA
2.2V      25.45mA    34.87mA    27.24mA
2.3V      25.73mA    95.14mA    27.33mA
2.4V      29mA       210mA      27.58mA
2.5V      69.65mA    340mA      29.41mA
2.6V      180mA      480mA      45.21mA
2.7V      320mA      620mA      130mA
2.8V      470mA      770mA      260mA
3V        780mA      1.06A      560mA
3.6V      1.74A      1.98A      1.52A
[Pullup]
| voltage   I(typ)   I(min)   I(max)
-1.8V     24.52mA    17.72mA    22.53mA
-600mV    24.52mA    17.72mA    22.53mA
600mV     -15.64mA   -15.11mA   -15.15mA
2.2V      -22.51mA   -22.14mA   -22.9mA
2.3V      -22.73mA   -26.38mA   -23.03mA
2.4V      -23.9mA    -56.46mA   -23.25mA
2.5V      -29.43mA   -150mA     -24.56mA
2.6V      -57.9mA    -280mA     -30.58mA
2.7V      -160mA     -430mA     -47.31mA
2.8V      -300mA     -590mA     -120mA
3V        -620mA     -910mA     -410mA
3.6V      -1.66A     -1.92A     -1.44A
[GND_clamp]
| voltage   I(typ)   I(min)   I(max)
-1.8V     -1.65A     -1.74A     -1.6A
-1.2V     -620mA     -740mA     -570mA
-1.1V     -450mA     -580mA     -410mA
-1V       -290mA     -420mA     -250mA
-900mV    -150mA     -270mA     -110mA
-800mV    -40.97mA   -140mA     -27.17mA
-700mV    -7.54mA    -40.17mA   -8.08mA
-600mV    -1.39mA    -5.57mA    -1.57mA
-500mV    -120uA     -660uA     -120uA
1.8V      34.27pA    98.88nA    22.46pA
[POWER_clamp]
| voltage   I(typ)   I(min)   I(max)
-1.8V     1.73A      1.82A      1.67A
-1.7V     1.57A      1.66A      1.51A
-1.4V     1.08A      1.21A      1.02A
-1.3V     930mA      1.05A      870mA
-1.1V     610mA      760mA      550mA
-900mV    310mA      460mA      250mA
-800mV    170mA      320mA      120mA
-700mV    52.75mA    190mA      22.81mA
-600mV    4.57mA     79.88mA    2.44mA
-500mV    270uA      13.45mA    250uA
-400mV    16.38uA    820uA      14.46uA
0V        34.27pA    1.07nA     29.84pA
[Ramp]
| variable   typ   min   max
dV/dt_r   0.56/0.70n   0.53/0.85n   0.57/0.59n
dV/dt_f   0.55/0.80n   0.51/0.98n   0.57/0.65n
R_load = 50.00
[Rising Waveform]
R_fixture = 50.00
V_fixture = 0.000
| time   V(typ)   V(min)   V(max)
0s        0V         0V         0V
900ps     -9.66mV    -3.62mV    41.89mV
1.2ns     8.91mV     -10.38mV   260mV
1.5ns     230mV      5.2mV      590mV
1.8ns     570mV      150mV      830mV
2.1ns     750mV      370mV      910mV
2.4ns     850mV      570mV      940mV
3ns       920mV      790mV      950mV
3.9ns     930mV      870mV      960mV
15ns      930mV      880mV      960mV
[Rising Waveform]
R_fixture = 50.00
V_fixture = 1.80
V_fixture_min = 1.70
V_fixture_max = 1.90
| time   V(typ)   V(min)   V(max)
0s        890mV      850mV      940mV
300ps     890mV      850mV      940mV
600ps     900mV      850mV      1.01V
900ps     1.08V      890mV      1.4V
1.2ns     1.37V      1.04V      1.71V
1.5ns     1.65V      1.34V      1.85V
1.8ns     1.78V      1.59V      1.89V
2.1ns     1.79V      1.66V      1.9V
2.7ns     1.8V       1.7V       1.9V
15ns      1.8V       1.7V       1.9V
[Falling Waveform]
R_fixture = 50.00
V_fixture = 0.000
| time   V(typ)   V(min)   V(max)
0s        930mV      880mV      960mV
300ps     930mV      880mV      960mV
600ps     920mV      880mV      860mV
900ps     670mV      830mV      380mV
1.2ns     340mV      630mV      130mV
1.5ns     100mV      280mV      30.63mV
1.8ns     14.92mV    58.45mV    2.14mV
2.1ns     3.49mV     16.75mV    1.01mV
2.4ns     1.47mV     2.27mV     390uV
15ns      -3.87uV    33.95uV    40.83uV
[Falling Waveform]
R_fixture = 50.00
V_fixture = 1.80
V_fixture_min = 1.70
V_fixture_max = 1.90
| time   V(typ)   V(min)   V(max)
0s        1.8V       1.7V       1.9V
600ps     1.8V       1.7V       1.9V
900ps     1.8V       1.71V      1.81V
1.2ns     1.74V      1.71V      1.6V
1.5ns     1.53V      1.63V      1.32V
1.8ns     1.25V      1.42V      1.07V
2.1ns     1.08V      1.24V      1.01V
2.7ns     950mV      990mV      950mV
4.2ns     890mV      860mV      940mV
15ns      890mV      850mV      940mV
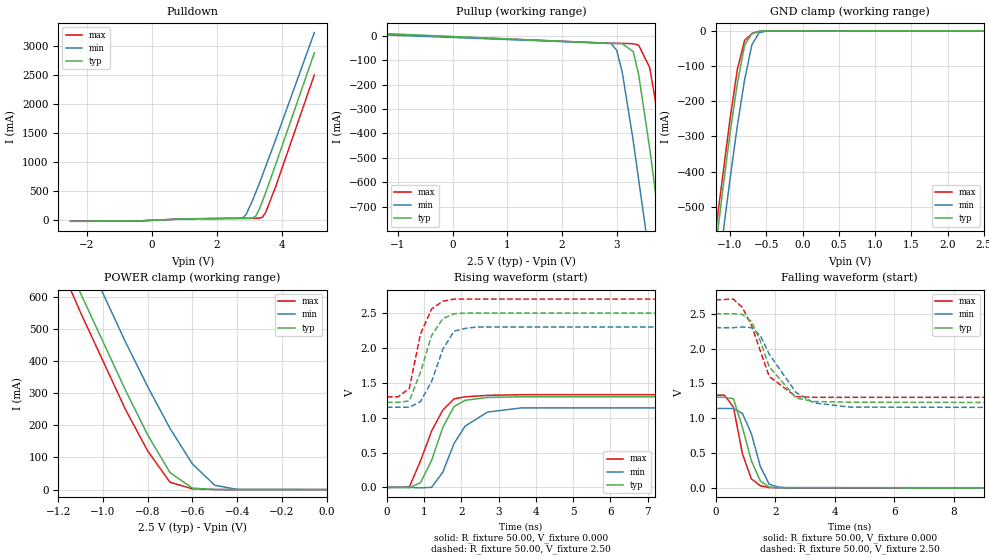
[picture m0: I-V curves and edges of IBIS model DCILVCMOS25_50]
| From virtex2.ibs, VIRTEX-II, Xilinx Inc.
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|   Model DCILVCMOS25_50
[Model]   DCILVCMOS25_50
Model_type   I/O
Polarity   Non-Inverting
Enable   Active-Low
Vinh = 1.7V
Vinl = 0.7V
Vmeas =   1.25V
Cref =  35.00pF
Rref =   1.00M
Vref =  0.000V
C_comp   7.00pF   6.00pF   8.00pF
[Temperature Range]   25.00   100.00   0.000
[Voltage Range]   2.50V   2.30V   2.70V
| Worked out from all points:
|   slope of the pulldown table from 0 to 0.375 V, typ, clamps not added: 35.5 ohm
|   slope of the pullup table from 0 to 0.375 V, typ, clamps not added: 33.4 ohm
|   GND clamp passes 1 mA (typ) near -0.57 V on its own axis
|   POWER clamp passes 1 mA (typ) near -0.52 V on its own axis
|   rising waveform, R_fixture 50.00, V_fixture 0.000: 20-80 % time 601ps typ, 668ps min, 646ps max; typ from 0 V to 1.3 V
|   rising waveform, R_fixture 50.00, V_fixture 2.50: 20-80 % time 507ps typ, 549ps min, 422ps max; typ from 1.22 V to 2.5 V
|   falling waveform, R_fixture 50.00, V_fixture 0.000: 20-80 % time 558ps typ, 532ps min, 444ps max; typ from 1.3 V to 0 V
|   falling waveform, R_fixture 50.00, V_fixture 2.50: 20-80 % time 879ps typ, 1.05ns min, 739ps max; typ from 2.5 V to 1.22 V
[Pulldown]
| voltage   I(typ)   I(min)   I(max)
-2.5V     -18.93mA   -16.32mA   -18.93mA
-600mV    -17.31mA   -16.32mA   -17.21mA
1V        22.68mA    21.14mA    23.86mA
2.8V      29.96mA    38.17mA    33.12mA
2.9V      30.02mA    97.47mA    33.17mA
3.1V      33.34mA    340mA      33.26mA
3.2V      72.7mA     480mA      33.47mA
3.3V      180mA      620mA      35.2mA
3.4V      320mA      770mA      50.13mA
3.5V      470mA      920mA      130mA
3.8V      940mA      1.37A      560mA
5V        2.88A      3.23A      2.5A
[Pullup]
| voltage   I(typ)   I(min)   I(max)
-2.5V     20.48mA    14.12mA    18.38mA
2.9V      -31.73mA   -32.31mA   -31.36mA
3V        -31.93mA   -61.16mA   -31.49mA
3.1V      -33.04mA   -150mA     -31.61mA
3.3V      -64.95mA   -430mA     -33.04mA
3.4V      -160mA     -590mA     -38.87mA
3.6V      -460mA     -910mA     -130mA
3.7V      -630mA     -1.08A     -260mA
3.8V      -800mA     -1.24A     -420mA
4V        -1.14A     -1.58A     -750mA
4.2V      -1.48A     -1.92A     -1.09A
5V        -2.89A     -3.29A     -2.49A
[GND_clamp]
| voltage   I(typ)   I(min)   I(max)
-2.5V     -2.88A     -2.94A     -2.84A
-1.2V     -620mA     -740mA     -570mA
-1.1V     -450mA     -580mA     -410mA
-1V       -290mA     -420mA     -250mA
-900mV    -150mA     -270mA     -110mA
-800mV    -41mA      -140mA     -27.22mA
-700mV    -7.57mA    -40.19mA   -8.13mA
-600mV    -1.4mA     -5.59mA    -1.6mA
-500mV    -130uA     -660uA     -120uA
2.5V      49.34pA    2.1uA      32.91pA
[POWER_clamp]
| voltage   I(typ)   I(min)   I(max)
-2.5V     2.87A      2.91A      2.82A
-1.3V     930mA      1.05A      870mA
-1.2V     770mA      910mA      710mA
-1.1V     610mA      760mA      550mA
-900mV    310mA      460mA      250mA
-800mV    170mA      320mA      120mA
-700mV    52.75mA    190mA      22.81mA
-600mV    4.57mA     79.88mA    2.44mA
-500mV    270uA      13.45mA    250uA
-400mV    16.38uA    820uA      14.46uA
0V        49.34pA    1.47nA     44.79pA
[Ramp]
| variable   typ   min   max
dV/dt_r   0.78/0.55n   0.68/0.71n   0.80/0.50n
dV/dt_f   0.76/0.94n   0.69/1.05n   0.84/0.78n
R_load = 50.00
[Rising Waveform]
R_fixture = 50.00
V_fixture = 0.000
| time   V(typ)   V(min)   V(max)
0s        0V         0V         0V
600ps     -2.9mV     -42.03uV   7.58mV
900ps     66.47mV    -6mV       380mV
1.2ns     390mV      1.34mV     810mV
1.5ns     860mV      220mV      1.11V
1.8ns     1.16V      630mV      1.27V
2.1ns     1.25V      880mV      1.3V
2.7ns     1.29V      1.08V      1.32V
3.6ns     1.3V       1.14V      1.33V
15ns      1.3V       1.14V      1.33V
[Rising Waveform]
R_fixture = 50.00
V_fixture = 2.50
V_fixture_min = 2.30
V_fixture_max = 2.70
| time   V(typ)   V(min)   V(max)
0s        1.22V      1.15V      1.3V
300ps     1.22V      1.15V      1.3V
600ps     1.24V      1.15V      1.42V
900ps     1.65V      1.23V      2.2V
1.2ns     2.18V      1.52V      2.56V
1.5ns     2.42V      1.98V      2.67V
1.8ns     2.49V      2.24V      2.7V
2.1ns     2.5V       2.28V      2.7V
2.4ns     2.5V       2.3V       2.7V
15ns      2.5V       2.3V       2.7V
[Falling Waveform]
R_fixture = 50.00
V_fixture = 0.000
| time   V(typ)   V(min)   V(max)
0s        1.3V       1.14V      1.33V
300ps     1.3V       1.14V      1.33V
600ps     1.28V      1.14V      1.16V
900ps     870mV      1.07V      490mV
1.2ns     390mV      780mV      130mV
1.5ns     98.82mV    310mV      29.77mV
1.8ns     9.54mV     52.42mV    4.06mV
2.1ns     3.03mV     12.07mV    220uV
2.4ns     1.05mV     3.88mV     290uV
15ns      -27.67uV   5.23uV     1.04uV
[Falling Waveform]
R_fixture = 50.00
V_fixture = 2.50
V_fixture_min = 2.30
V_fixture_max = 2.70
| time   V(typ)   V(min)   V(max)
0s        2.5V       2.3V       2.7V
600ps     2.5V       2.3V       2.71V
900ps     2.49V      2.31V      2.59V
1.2ns     2.39V      2.3V       2.34V
1.5ns     2.11V      2.19V      1.97V
1.8ns     1.74V      1.92V      1.6V
2.7ns     1.29V      1.37V      1.31V
3.3ns     1.24V      1.22V      1.3V
4.5ns     1.23V      1.16V      1.3V
15ns      1.22V      1.15V      1.3V
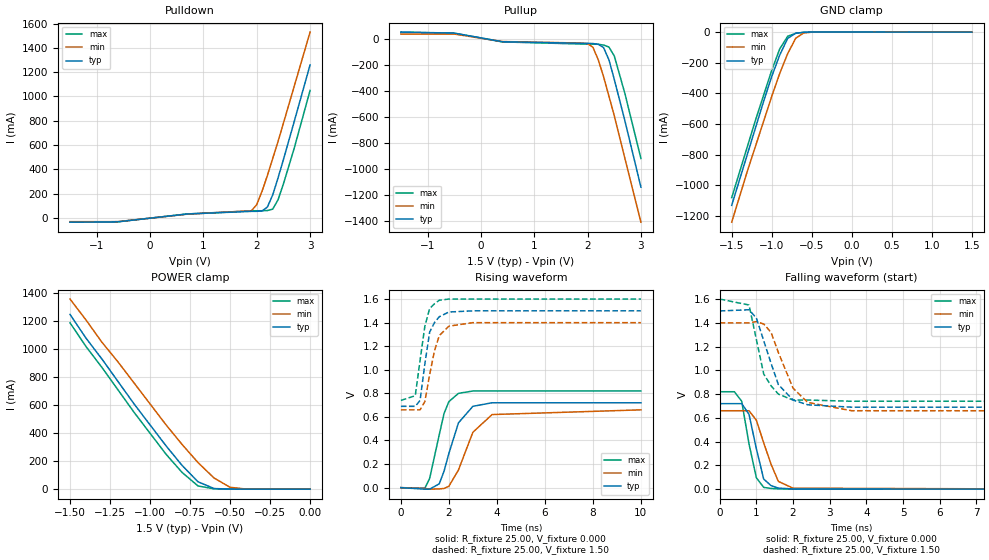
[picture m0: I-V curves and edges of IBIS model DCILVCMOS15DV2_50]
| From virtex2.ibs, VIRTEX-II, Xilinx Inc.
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|   Model DCILVCMOS15DV2_50
[Model]   DCILVCMOS15DV2_50
Model_type   I/O
Polarity   Non-Inverting
Enable   Active-Low
Vinh = 1.05V
Vinl = 0.3V
Vmeas =   0.75V
Cref =  35.00pF
Rref =   1.00M
Vref =  0.000V
C_comp   7.00pF   6.00pF   8.00pF
[Temperature Range]   25.00   100.00   0.000
[Voltage Range]   1.50V   1.40V   1.60V
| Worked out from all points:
|   slope of the pulldown table from 0 to 0.225 V, typ, clamps not added: 18.4 ohm
|   slope of the pullup table from 0 to 0.225 V, typ, clamps not added: 16.4 ohm
|   GND clamp passes 1 mA (typ) near -0.57 V on its own axis
|   POWER clamp passes 1 mA (typ) near -0.52 V on its own axis
|   rising waveform, R_fixture 25.00, V_fixture 0.000: 20-80 % time 669ps typ, 904ps min, 539ps max; typ from 0 V to 0.72 V
|   rising waveform, R_fixture 25.00, V_fixture 1.50: 20-80 % time 373ps typ, 474ps min, 389ps max; typ from 0.69 V to 1.5 V
|   falling waveform, R_fixture 25.00, V_fixture 0.000: 20-80 % time 316ps typ, 453ps min, 305ps max; typ from 0.72 V to 0 V
|   falling waveform, R_fixture 25.00, V_fixture 1.50: 20-80 % time 555ps typ, 640ps min, 432ps max; typ from 1.5 V to 0.69 V
[Pulldown]
| voltage   I(typ)   I(min)   I(max)
-1.5V     -34.98mA   -30.6mA    -34.01mA
-600mV    -31.87mA   -30.6mA    -30.85mA
700mV     32.61mA    31.18mA    32.91mA
1.9V      54.06mA    58.57mA    58.51mA
2V        54.49mA    110mA      58.88mA
2.1V      57.04mA    220mA      59.29mA
2.2V      89.88mA    350mA      60.89mA
2.3V      190mA      490mA      72.66mA
2.4V      330mA      630mA      150mA
2.5V      480mA      780mA      280mA
2.7V      790mA      1.08A      570mA
3V        1.26A      1.53A      1.05A
[Pullup]
| voltage   I(typ)   I(min)   I(max)
-1.5V     52.69mA    37.58mA    52.16mA
-500mV    45.15mA    37.58mA    43.69mA
400mV     -21.22mA   -19.97mA   -22.83mA
1.9V      -33.89mA   -31.85mA   -39.31mA
2V        -34.2mA    -35.85mA   -39.59mA
2.1V      -35.36mA   -64.05mA   -39.93mA
2.2V      -40.65mA   -160mA     -41.2mA
2.3V      -66.86mA   -290mA     -46.91mA
2.4V      -160mA     -440mA     -62.28mA
2.5V      -310mA     -590mA     -130mA
2.7V      -630mA     -920mA     -420mA
3V        -1.14A     -1.41A     -920mA
[GND_clamp]
| voltage   I(typ)   I(min)   I(max)
-1.5V     -1.13A     -1.24A     -1.08A
-1.3V     -790mA     -900mA     -740mA
-1.2V     -620mA     -740mA     -570mA
-1.1V     -450mA     -580mA     -410mA
-1V       -290mA     -420mA     -250mA
-900mV    -150mA     -270mA     -110mA
-800mV    -40.96mA   -140mA     -27.15mA
-700mV    -7.52mA    -40.16mA   -8.06mA
-600mV    -1.38mA    -5.56mA    -1.57mA
-500mV    -120uA     -650uA     -120uA
1.5V      27.96pA    98.69nA    16.96pA
[POWER_clamp]
| voltage   I(typ)   I(min)   I(max)
-1.5V     1.25A      1.36A      1.19A
-1.4V     1.08A      1.21A      1.02A
-1.3V     930mA      1.05A      870mA
-1.2V     770mA      910mA      710mA
-1.1V     610mA      760mA      550mA
-900mV    310mA      460mA      250mA
-800mV    170mA      320mA      120mA
-700mV    52.75mA    190mA      22.81mA
-600mV    4.57mA     79.88mA    2.44mA
-500mV    270uA      13.45mA    250uA
-400mV    16.38uA    820uA      14.46uA
0V        27.96pA    880pA      24.27pA
[Ramp]
| variable   typ   min   max
dV/dt_r   0.43/0.66n   0.40/0.89n   0.49/0.50n
dV/dt_f   0.48/0.47n   0.45/0.61n   0.52/0.38n
R_load = 25.00
[Rising Waveform]
R_fixture = 25.00
V_fixture = 0.000
| time   V(typ)   V(min)   V(max)
0s        0V         0V         0V
1ns       -12.98mV   -6.87mV    -4.96mV
1.2ns     -12.77mV   -12.73mV   78.26mV
1.6ns     32.68mV    -10.73mV   450mV
1.8ns     140mV      -7.2mV     630mV
2ns       290mV      11.71mV    730mV
2.4ns     550mV      150mV      800mV
3ns       690mV      470mV      820mV
3.8ns     720mV      620mV      820mV
10ns      720mV      660mV      820mV
[Rising Waveform]
R_fixture = 25.00
V_fixture = 1.50
V_fixture_min = 1.40
V_fixture_max = 1.60
| time   V(typ)   V(min)   V(max)
0s        690mV      660mV      740mV
600ps     690mV      660mV      780mV
800ps     740mV      660mV      1.08V
1ns       1.05V      730mV      1.37V
1.2ns     1.32V      960mV      1.52V
1.4ns     1.4V       1.16V      1.56V
1.6ns     1.45V      1.29V      1.59V
2ns       1.49V      1.37V      1.6V
3ns       1.5V       1.4V       1.6V
10ns      1.5V       1.4V       1.6V
[Falling Waveform]
R_fixture = 25.00
V_fixture = 0.000
| time   V(typ)   V(min)   V(max)
0s        720mV      660mV      820mV
400ps     720mV      660mV      820mV
600ps     720mV      660mV      740mV
800ps     630mV      660mV      380mV
1ns       340mV      580mV      95.85mV
1.2ns     84.67mV    390mV      14.95mV
1.4ns     30.06mV    210mV      6.1mV
1.6ns     8.93mV     65.1mV     2.42mV
2ns       2.04mV     8.39mV     610uV
10ns      4.26uV     -26.72uV   10.47uV
[Falling Waveform]
R_fixture = 25.00
V_fixture = 1.50
V_fixture_min = 1.40
V_fixture_max = 1.60
| time   V(typ)   V(min)   V(max)
0s        1.5V       1.4V       1.6V
800ps     1.51V      1.4V       1.55V
1ns       1.44V      1.41V      1.26V
1.2ns     1.25V      1.39V      970mV
1.4ns     1.06V      1.32V      870mV
1.6ns     880mV      1.15V      800mV
2ns       750mV      850mV      750mV
2.4ns     710mV      730mV      750mV
3.6ns     690mV      660mV      740mV
10ns      690mV      660mV      740mV
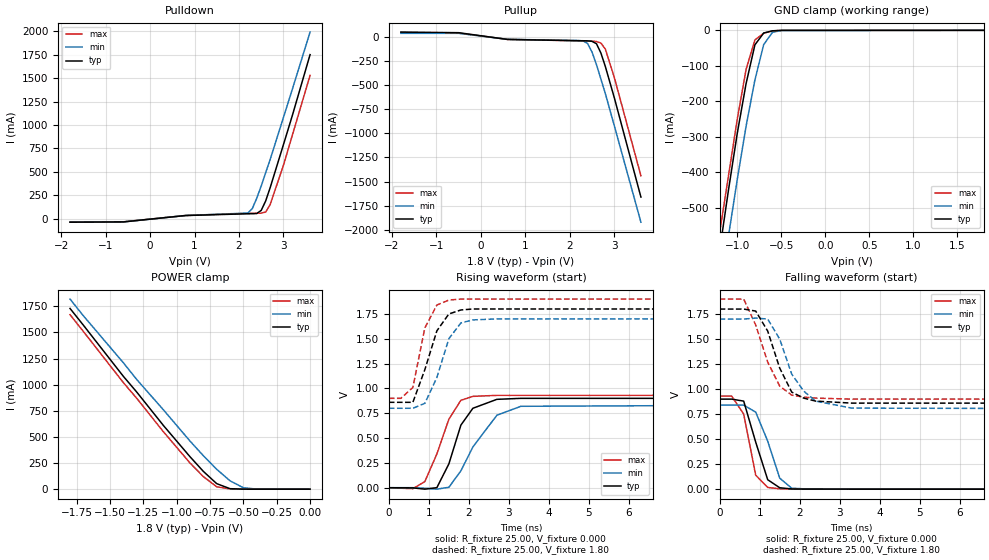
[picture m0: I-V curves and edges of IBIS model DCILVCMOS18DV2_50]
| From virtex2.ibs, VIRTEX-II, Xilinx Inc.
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|   Model DCILVCMOS18DV2_50
[Model]   DCILVCMOS18DV2_50
Model_type   I/O
Polarity   Non-Inverting
Enable   Active-Low
Vinh = 1.19V
Vinl = 0.4V
Vmeas =   0.90V
Cref =  35.00pF
Rref =   1.00M
Vref =  0.000V
C_comp   7.00pF   6.00pF   8.00pF
[Temperature Range]   25.00   100.00   0.000
[Voltage Range]   1.80V   1.70V   1.90V
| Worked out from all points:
|   slope of the pulldown table from 0 to 0.27 V, typ, clamps not added: 18.7 ohm
|   slope of the pullup table from 0 to 0.27 V, typ, clamps not added: 16.6 ohm
|   GND clamp passes 1 mA (typ) near -0.57 V on its own axis
|   POWER clamp passes 1 mA (typ) near -0.52 V on its own axis
|   rising waveform, R_fixture 25.00, V_fixture 0.000: 20-80 % time 534ps typ, 759ps min, 552ps max; typ from 0 V to 0.9 V
|   rising waveform, R_fixture 25.00, V_fixture 1.80: 20-80 % time 486ps typ, 488ps min, 372ps max; typ from 0.86 V to 1.8 V
|   falling waveform, R_fixture 25.00, V_fixture 0.000: 20-80 % time 415ps typ, 452ps min, 274ps max; typ from 0.9 V to 0 V
|   falling waveform, R_fixture 25.00, V_fixture 1.80: 20-80 % time 551ps typ, 630ps min, 582ps max; typ from 1.8 V to 0.86 V
[Pulldown]
| voltage   I(typ)   I(min)   I(max)
-1.8V     -34.97mA   -32.4mA    -34mA
-600mV    -31.86mA   -32.4mA    -30.84mA
800mV     36mA       36.32mA    36.52mA
2.2V      54.8mA     62.29mA    59.38mA
2.3V      55.12mA    110mA      59.57mA
2.4V      57.57mA    220mA      59.86mA
2.5V      90.22mA    350mA      61.37mA
2.6V      190mA      490mA      73.03mA
2.7V      330mA      630mA      150mA
3V        790mA      1.08A      570mA
3.2V      1.1A       1.38A      890mA
3.6V      1.75A      1.99A      1.53A
[Pullup]
| voltage   I(typ)   I(min)   I(max)
-1.8V     46.39mA    33.64mA    43.04mA
-500mV    40.11mA    33.64mA    36.28mA
600mV     -29.63mA   -28.39mA   -29.12mA
2.2V      -42.86mA   -41.23mA   -44.25mA
2.3V      -43.17mA   -44.98mA   -44.51mA
2.4V      -44.28mA   -71.4mA    -44.82mA
2.5V      -49.34mA   -160mA     -46.04mA
2.6V      -73.88mA   -290mA     -51.61mA
2.7V      -170mA     -440mA     -66.6mA
2.8V      -310mA     -590mA     -130mA
3V        -630mA     -920mA     -420mA
3.6V      -1.66A     -1.92A     -1.44A
[GND_clamp]
| voltage   I(typ)   I(min)   I(max)
-1.8V     -1.65A     -1.74A     -1.6A
-1.2V     -620mA     -740mA     -570mA
-1.1V     -450mA     -580mA     -410mA
-1V       -290mA     -420mA     -250mA
-900mV    -150mA     -270mA     -110mA
-800mV    -40.97mA   -140mA     -27.17mA
-700mV    -7.54mA    -40.17mA   -8.08mA
-600mV    -1.39mA    -5.57mA    -1.57mA
-500mV    -120uA     -660uA     -120uA
1.8V      34.27pA    98.88nA    22.46pA
[POWER_clamp]
| voltage   I(typ)   I(min)   I(max)
-1.8V     1.73A      1.82A      1.67A
-1.7V     1.57A      1.66A      1.51A
-1.4V     1.08A      1.21A      1.02A
-1.3V     930mA      1.05A      870mA
-1.1V     610mA      760mA      550mA
-900mV    310mA      460mA      250mA
-800mV    170mA      320mA      120mA
-700mV    52.75mA    190mA      22.81mA
-600mV    4.57mA     79.88mA    2.44mA
-500mV    270uA      13.45mA    250uA
-400mV    16.38uA    820uA      14.46uA
0V        34.27pA    1.07nA     29.84pA
[Ramp]
| variable   typ   min   max
dV/dt_r   0.54/0.56n   0.50/0.74n   0.56/0.45n
dV/dt_f   0.57/0.52n   0.54/0.70n   0.60/0.42n
R_load = 25.00
[Rising Waveform]
R_fixture = 25.00
V_fixture = 0.000
| time   V(typ)   V(min)   V(max)
0s        0V         0V         0V
600ps     -1.76mV    20.24uV    -9.93mV
900ps     -14.74mV   -5.3mV     62.28mV
1.2ns     590uV      -14.57mV   340mV
1.5ns     240mV      4.2mV      690mV
1.8ns     630mV      170mV      880mV
2.1ns     800mV      410mV      920mV
2.7ns     890mV      730mV      930mV
3.3ns     900mV      820mV      930mV
15ns      900mV      840mV      930mV
[Rising Waveform]
R_fixture = 25.00
V_fixture = 1.80
V_fixture_min = 1.70
V_fixture_max = 1.90
| time   V(typ)   V(min)   V(max)
0s        860mV      800mV      900mV
300ps     860mV      800mV      900mV
600ps     860mV      800mV      1.01V
900ps     1.19V      850mV      1.61V
1.2ns     1.58V      1.11V      1.84V
1.5ns     1.75V      1.5V       1.89V
1.8ns     1.79V      1.66V      1.9V
2.1ns     1.8V       1.69V      1.9V
2.7ns     1.8V       1.7V       1.9V
15ns      1.8V       1.7V       1.9V
[Falling Waveform]
R_fixture = 25.00
V_fixture = 0.000
| time   V(typ)   V(min)   V(max)
0s        900mV      840mV      930mV
300ps     900mV      840mV      930mV
600ps     880mV      840mV      750mV
900ps     470mV      770mV      140mV
1.2ns     94.45mV    480mV      17.12mV
1.5ns     14.16mV    110mV      3.58mV
1.8ns     2.18mV     9.93mV     890uV
2.1ns     980uV      3.13mV     320uV
3.3ns     56.4uV     290uV      750nV
15ns      -3.67uV    25.15uV    -13.05uV
[Falling Waveform]
R_fixture = 25.00
V_fixture = 1.80
V_fixture_min = 1.70
V_fixture_max = 1.90
| time   V(typ)   V(min)   V(max)
0s        1.8V       1.7V       1.9V
600ps     1.8V       1.7V       1.9V
900ps     1.78V      1.71V      1.64V
1.2ns     1.58V      1.7V       1.27V
1.5ns     1.21V      1.5V       1.03V
1.8ns     970mV      1.15V      940mV
2.1ns     910mV      980mV      920mV
2.4ns     880mV      880mV      910mV
3.3ns     860mV      810mV      900mV
15ns      860mV      800mV      900mV
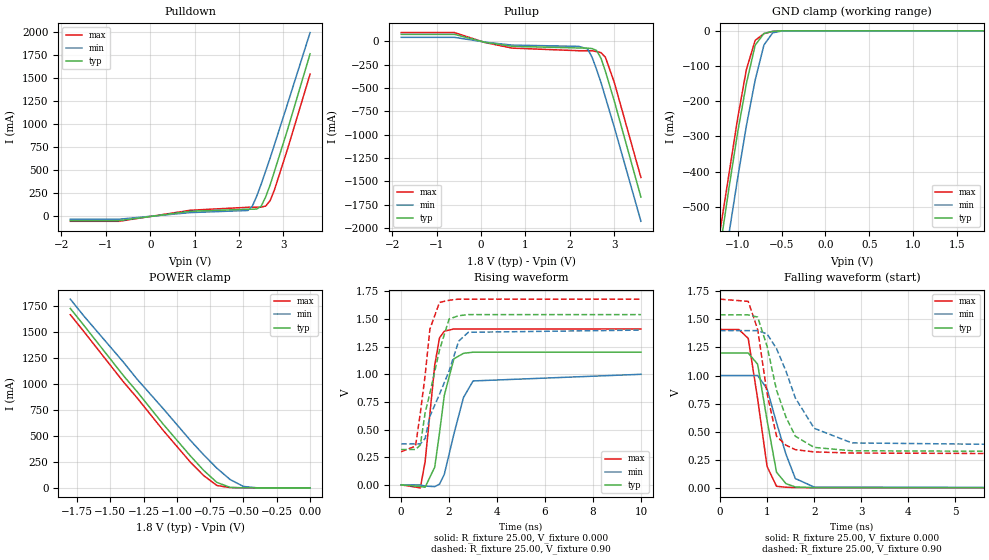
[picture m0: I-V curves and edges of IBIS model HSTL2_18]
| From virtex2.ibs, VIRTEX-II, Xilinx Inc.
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|   Model HSTL2_18
[Model]   HSTL2_18
Model_type   I/O
Polarity   Non-Inverting
Enable   Active-Low
Vinh = 1.0V
Vinl = 0.8V
Vmeas =   0.90V
Cref =  20.00pF
Rref =  25.00
Vref =   0.90V
C_comp   7.00pF   6.00pF   8.00pF
[Temperature Range]   25.00   100.00   0.000
[Voltage Range]   1.80V   1.70V   1.90V
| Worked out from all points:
|   slope of the pulldown table from 0 to 0.27 V, typ, clamps not added: 13.7 ohm
|   slope of the pullup table from 0 to 0.27 V, typ, clamps not added: 10.2 ohm
|   GND clamp passes 1 mA (typ) near -0.57 V on its own axis
|   POWER clamp passes 1 mA (typ) near -0.52 V on its own axis
|   rising waveform, R_fixture 25.00, V_fixture 0.000: 20-80 % time 485ps typ, 693ps min, 410ps max; typ from 0 V to 1.2 V
|   rising waveform, R_fixture 25.00, V_fixture 0.90: 20-80 % time 732ps typ, 1.07ns min, 446ps max; typ from 0.32 V to 1.54 V
|   falling waveform, R_fixture 25.00, V_fixture 0.000: 20-80 % time 301ps typ, 439ps min, 295ps max; typ from 1.2 V to 0 V
|   falling waveform, R_fixture 25.00, V_fixture 0.90: 20-80 % time 505ps typ, 670ps min, 337ps max; typ from 1.54 V to 0.32 V
[Pulldown]
| voltage   I(typ)   I(min)   I(max)
-1.8V     -48mA      -32.32mA   -55.01mA
-700mV    -48mA      -32.32mA   -55.01mA
900mV     53.68mA    39.23mA    64.51mA
2.2V      75.66mA    62.23mA    96.92mA
2.3V      76.03mA    110mA      97.24mA
2.4V      78.06mA    220mA      97.59mA
2.5V      110mA      350mA      98.83mA
2.6V      210mA      490mA      110mA
2.7V      340mA      630mA      170mA
2.8V      490mA      780mA      290mA
3.1V      950mA      1.23A      740mA
3.6V      1.76A      1.99A      1.54A
[Pullup]
| voltage   I(typ)   I(min)   I(max)
-1.8V     75.63mA    43.61mA    94.82mA
-600mV    75.63mA    43.61mA    94.82mA
100mV     -10.69mA   -8.2mA     -13.71mA
700mV     -52.88mA   -39.78mA   -71.87mA
2.2V      -70.67mA   -53.17mA   -100mA
2.4V      -72.18mA   -80.97mA   -100mA
2.5V      -76.68mA   -170mA     -100mA
2.6V      -96.71mA   -300mA     -110mA
2.7V      -180mA     -440mA     -120mA
2.8V      -320mA     -600mA     -170mA
3V        -640mA     -920mA     -440mA
3.6V      -1.67A     -1.93A     -1.46A
[GND_clamp]
| voltage   I(typ)   I(min)   I(max)
-1.8V     -1.65A     -1.74A     -1.6A
-1.2V     -620mA     -740mA     -570mA
-1.1V     -450mA     -580mA     -410mA
-1V       -290mA     -420mA     -250mA
-900mV    -150mA     -270mA     -110mA
-800mV    -40.97mA   -140mA     -27.17mA
-700mV    -7.54mA    -40.17mA   -8.08mA
-600mV    -1.39mA    -5.57mA    -1.57mA
-500mV    -120uA     -660uA     -120uA
1.8V      34.27pA    98.88nA    22.46pA
[POWER_clamp]
| voltage   I(typ)   I(min)   I(max)
-1.8V     1.73A      1.82A      1.67A
-1.7V     1.57A      1.66A      1.51A
-1.4V     1.08A      1.21A      1.02A
-1.3V     930mA      1.05A      870mA
-1.1V     610mA      760mA      550mA
-900mV    310mA      460mA      250mA
-800mV    170mA      320mA      120mA
-700mV    52.75mA    190mA      22.81mA
-600mV    4.57mA     79.88mA    2.44mA
-500mV    270uA      13.45mA    250uA
-400mV    16.38uA    820uA      14.46uA
0V        34.27pA    1.07nA     29.84pA
[Ramp]
| variable   typ   min   max
dV/dt_r   0.72/0.46n   0.60/0.67n   0.85/0.33n
dV/dt_f   0.66/0.55n   0.54/0.86n   0.75/0.41n
R_load = 25.00
[Rising Waveform]
R_fixture = 25.00
V_fixture = 0.000
| time   V(typ)   V(min)   V(max)
0s        0V         0V         0V
800ps     -15.52mV   -1.32mV    -27.19mV
1ns       -21.06mV   -11.2mV    210mV
1.4ns     160mV      -15.99mV   1.08V
1.6ns     470mV      6.23mV     1.33V
1.8ns     810mV      95.07mV    1.39V
2.2ns     1.14V      460mV      1.41V
2.6ns     1.19V      790mV      1.41V
3ns       1.2V       940mV      1.41V
10ns      1.2V       1V         1.41V
[Rising Waveform]
R_fixture = 25.00
V_fixture = 0.90
V_fixture_min = 0.85
V_fixture_max = 0.95
| time   V(typ)   V(min)   V(max)
0s        320mV      370mV      300mV
600ps     320mV      370mV      350mV
800ps     360mV      370mV      650mV
1ns       650mV      420mV      990mV
1.2ns     830mV      620mV      1.41V
1.6ns     1.22V      820mV      1.65V
2ns       1.5V       1.03V      1.67V
2.4ns     1.53V      1.3V       1.68V
2.8ns     1.54V      1.38V      1.68V
10ns      1.54V      1.4V       1.68V
[Falling Waveform]
R_fixture = 25.00
V_fixture = 0.000
| time   V(typ)   V(min)   V(max)
0s        1.2V       1V         1.41V
400ps     1.2V       1V         1.41V
600ps     1.2V       1V         1.33V
800ps     1.1V       1V         790mV
1ns       600mV      880mV      190mV
1.2ns     140mV      580mV      14.09mV
1.4ns     37.32mV    300mV      5.49mV
1.6ns     8.01mV     82.81mV    2.64mV
2ns       1.99mV     7.18mV     1.09mV
10ns      790nV      -770nV     0V
[Falling Waveform]
R_fixture = 25.00
V_fixture = 0.90
V_fixture_min = 0.85
V_fixture_max = 0.95
| time   V(typ)   V(min)   V(max)
0s        1.54V      1.4V       1.68V
600ps     1.54V      1.4V       1.66V
800ps     1.52V      1.4V       1.41V
1ns       1.26V      1.37V      840mV
1.2ns     870mV      1.24V      460mV
1.4ns     630mV      1.04V      380mV
1.6ns     460mV      800mV      340mV
2ns       360mV      530mV      320mV
2.8ns     330mV      400mV      310mV
10ns      320mV      370mV      300mV
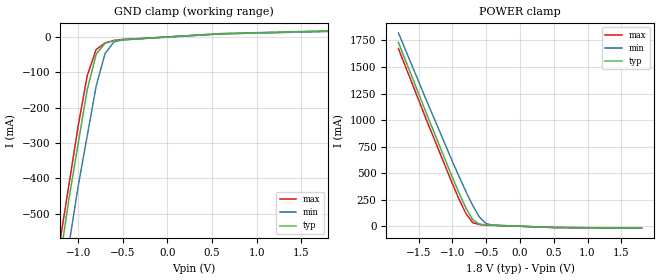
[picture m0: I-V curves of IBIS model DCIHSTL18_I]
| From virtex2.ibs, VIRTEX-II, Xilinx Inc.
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|   Model DCIHSTL18_I
[Model]   DCIHSTL18_I
Model_type   Input
Vinh = 1.0V
Vinl = 0.8V
Polarity   Non-Inverting
C_comp   7.00pF   6.00pF   8.00pF
[Temperature Range]   25.00   100.00   0.000
[Voltage Range]   1.80V   1.70V   1.90V
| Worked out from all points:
|   GND clamp passes 1 mA (typ) near -0.05 V on its own axis
|   POWER clamp passes 1 mA (typ) near -0.04 V on its own axis
[GND_clamp]
| voltage   I(typ)   I(min)   I(max)
-1.8V     -1.65A     -1.74A     -1.6A
-1.2V     -620mA     -740mA     -570mA
-1.1V     -450mA     -580mA     -410mA
-1V       -300mA     -420mA     -250mA
-900mV    -150mA     -280mA     -110mA
-800mV    -49.55mA   -140mA     -36.2mA
-700mV    -18.49mA   -47.41mA   -17.58mA
-600mV    -11.42mA   -14.71mA   -10.22mA
-500mV    -8.72mA    -8.81mA    -7.55mA
600mV     9.08mA     8.3mA      8.13mA
1.8V      16.63mA    14.79mA    16mA
[POWER_clamp]
| voltage   I(typ)   I(min)   I(max)
-1.8V     1.731A     1.82A      1.672A
-1.4V     1.086A     1.208A     1.026A
-1V       459.3mA    610.7mA    400.1mA
-900mV    311mA      466.7mA    253.6mA
-800mV    173.3mA    327.5mA    122.1mA
-700mV    64.03mA    197.2mA    36.15mA
-600mV    22.11mA    87.38mA    17.53mA
-500mV    15.64mA    25.89mA    13.02mA
-400mV    12.1mA     12.6mA     10.1mA
500mV     -9.974mA   -9.515mA   -8.935mA
1.8V      -15.66mA   -14.79mA   -14.85mA
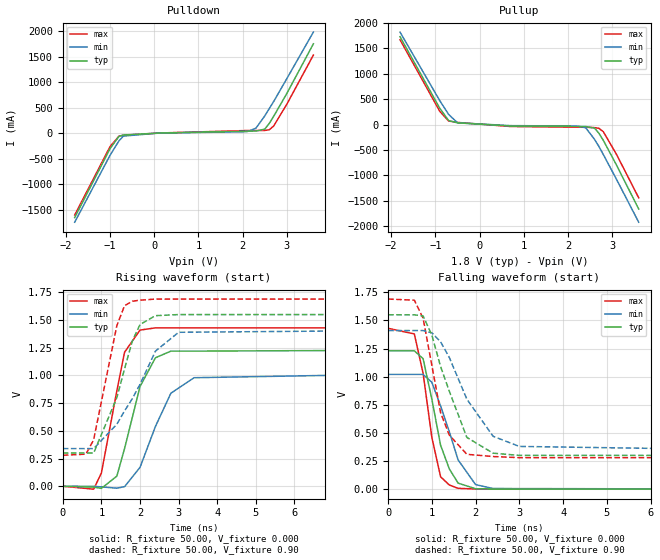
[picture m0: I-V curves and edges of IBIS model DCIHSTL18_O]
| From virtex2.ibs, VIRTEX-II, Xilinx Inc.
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|   Model DCIHSTL18_O
[Model]   DCIHSTL18_O
Model_type   Output
Polarity   Non-Inverting
Vmeas =   0.90V
Cref =  20.00pF
Rref =  50.00
Vref =   0.90V
C_comp   7.00pF   6.00pF   8.00pF
[Temperature Range]   25.00   100.00   0.000
[Voltage Range]   1.80V   1.70V   1.90V
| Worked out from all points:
|   slope of the pulldown table from 0 to 0.27 V, typ, clamps not added: 24.3 ohm
|   slope of the pullup table from 0 to 0.27 V, typ, clamps not added: 19.5 ohm
|   rising waveform, R_fixture 50.00, V_fixture 0.000: 20-80 % time 575ps typ, 728ps min, 473ps max; typ from 0 V to 1.23 V
|   rising waveform, R_fixture 50.00, V_fixture 0.90: 20-80 % time 692ps typ, 975ps min, 481ps max; typ from 0.3 V to 1.55 V
|   falling waveform, R_fixture 50.00, V_fixture 0.000: 20-80 % time 439ps typ, 547ps min, 365ps max; typ from 1.23 V to 0 V
|   falling waveform, R_fixture 50.00, V_fixture 0.90: 20-80 % time 638ps typ, 812ps min, 465ps max; typ from 1.55 V to 0.3 V
[Pulldown]
| voltage   I(typ)   I(min)   I(max)
-1.8V     -1.65A     -1.74A     -1.6A
-1V       -300mA     -430mA     -260mA
-800mV    -62.69mA   -150mA     -57.16mA
-700mV    -34.42mA   -54.75mA   -38.98mA
100mV     4.36mA     3.25mA     5.05mA
2.1V      41.93mA    30.68mA    53.73mA
2.3V      42.39mA    98.99mA    54.11mA
2.5V      81.17mA    340mA      55.95mA
2.6V      190mA      480mA      68.22mA
2.7V      330mA      620mA      140mA
3V        780mA      1.07A      570mA
3.6V      1.75A      1.98A      1.53A
[Pullup]
| voltage   I(typ)   I(min)   I(max)
-1.8V     1.73A      1.82A      1.67A
-900mV    320mA      470mA      260mA
-700mV    79.53mA    200mA      70.09mA
-500mV    34.54mA    35.8mA     42.57mA
700mV     -27.45mA   -20.6mA    -37.46mA
2.2V      -36.44mA   -27.71mA   -51.87mA
2.4V      -37.84mA   -60.77mA   -52.52mA
2.6V      -68.77mA   -290mA     -59.14mA
2.7V      -170mA     -430mA     -73.59mA
2.8V      -310mA     -590mA     -140mA
3.1V      -800mA     -1.08A     -590mA
3.6V      -1.66A     -1.92A     -1.44A
[Ramp]
| variable   typ   min   max
dV/dt_r   0.74/0.54n   0.61/0.75n   0.86/0.38n
dV/dt_f   0.70/0.68n   0.58/1.02n   0.78/0.50n
R_load = 50.00
[Rising Waveform]
R_fixture = 50.00
V_fixture = 0.000
| time   V(typ)   V(min)   V(max)
0s        0V         0V         0V
800ps     -7.75mV    -100uV     -26.15mV
1ns       -18.98mV   -5.57mV    120mV
1.4ns     91.59mV    -17.07mV   860mV
1.6ns     340mV      -3.68mV    1.21V
2ns       900mV      170mV      1.41V
2.4ns     1.16V      540mV      1.43V
2.8ns     1.22V      840mV      1.43V
3.4ns     1.22V      980mV      1.43V
10ns      1.23V      1.02V      1.43V
[Rising Waveform]
R_fixture = 50.00
V_fixture = 0.90
V_fixture_min = 0.85
V_fixture_max = 0.95
| time   V(typ)   V(min)   V(max)
0s        300mV      340mV      280mV
600ps     300mV      340mV      290mV
800ps     300mV      340mV      420mV
1.4ns     800mV      560mV      1.45V
1.6ns     1.06V      680mV      1.63V
1.8ns     1.31V      790mV      1.67V
2ns       1.46V      920mV      1.68V
2.4ns     1.54V      1.22V      1.69V
3ns       1.55V      1.39V      1.69V
10ns      1.55V      1.41V      1.69V
[Falling Waveform]
R_fixture = 50.00
V_fixture = 0.000
| time   V(typ)   V(min)   V(max)
0s        1.23V      1.02V      1.43V
600ps     1.23V      1.02V      1.38V
800ps     1.16V      1.02V      1.03V
1ns       800mV      950mV      460mV
1.2ns     390mV      740mV      110mV
1.4ns     180mV      510mV      36.8mV
1.6ns     53.73mV    260mV      7.43mV
2ns       3.72mV     40.4mV     1.41mV
2.4ns     1.28mV     5.66mV     680uV
10ns      -1.84uV    -1.9uV     -1.14uV
[Falling Waveform]
R_fixture = 50.00
V_fixture = 0.90
V_fixture_min = 0.85
V_fixture_max = 0.95
| time   V(typ)   V(min)   V(max)
0s        1.55V      1.41V      1.69V
600ps     1.55V      1.41V      1.68V
800ps     1.54V      1.41V      1.52V
1ns       1.37V      1.39V      1.1V
1.2ns     1.09V      1.31V      680mV
1.4ns     870mV      1.17V      480mV
1.8ns     460mV      800mV      310mV
2.4ns     320mV      470mV      290mV
3ns       300mV      380mV      280mV
10ns      300mV      340mV      280mV
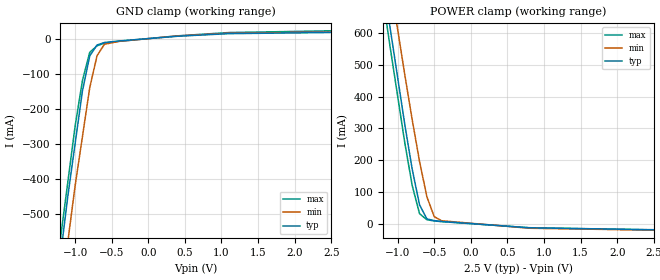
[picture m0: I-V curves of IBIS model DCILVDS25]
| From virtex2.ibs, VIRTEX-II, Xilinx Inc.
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|   Model DCILVDS25
[Model]   DCILVDS25
Model_type   Input
Vinh = 1.4V
Vinl = 1.0V
Polarity   Non-Inverting
C_comp   7.00pF   6.00pF   8.00pF
[Temperature Range]   25.00   100.00   0.000
[Voltage Range]   2.50V   2.30V   2.70V
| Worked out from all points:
|   GND clamp passes 1 mA (typ) near -0.05 V on its own axis
|   POWER clamp passes 1 mA (typ) near -0.05 V on its own axis
[GND_clamp]
| voltage   I(typ)   I(min)   I(max)
-2.5V     -2.88A     -2.94A     -2.84A
-1.2V     -620mA     -740mA     -570mA
-1.1V     -450mA     -580mA     -410mA
-1V       -300mA     -420mA     -250mA
-900mV    -150mA     -280mA     -120mA
-800mV    -49.58mA   -140mA     -39.29mA
-700mV    -18.52mA   -48.89mA   -20.78mA
-600mV    -11.43mA   -16.55mA   -13.11mA
-400mV    -6.99mA    -8.02mA    -8.06mA
400mV     6.48mA     7.14mA     7.65mA
1.1V      13.86mA    14.95mA    16.98mA
2.5V      17.1mA     18.51mA    21.96mA
[POWER_clamp]
| voltage   I(typ)   I(min)   I(max)
-2.5V     2.874A     2.908A     2.817A
-1.3V     926.6mA    1.056A     866.9mA
-1.2V     768.4mA    906.4mA    708.6mA
-1.1V     612mA      757.4mA    552.4mA
-900mV    310mA      466.2mA    252.8mA
-800mV    171.6mA    326.9mA    120.5mA
-700mV    60.3mA     196.4mA    32.57mA
-600mV    16.29mA    85.92mA    13.52mA
-500mV    10.64mA    23.4mA     9.684mA
-400mV    8.258mA    10.33mA    7.537mA
800mV     -11.83mA   -13.13mA   -11.53mA
2.5V      -17.81mA   -19.31mA   -18.45mA
